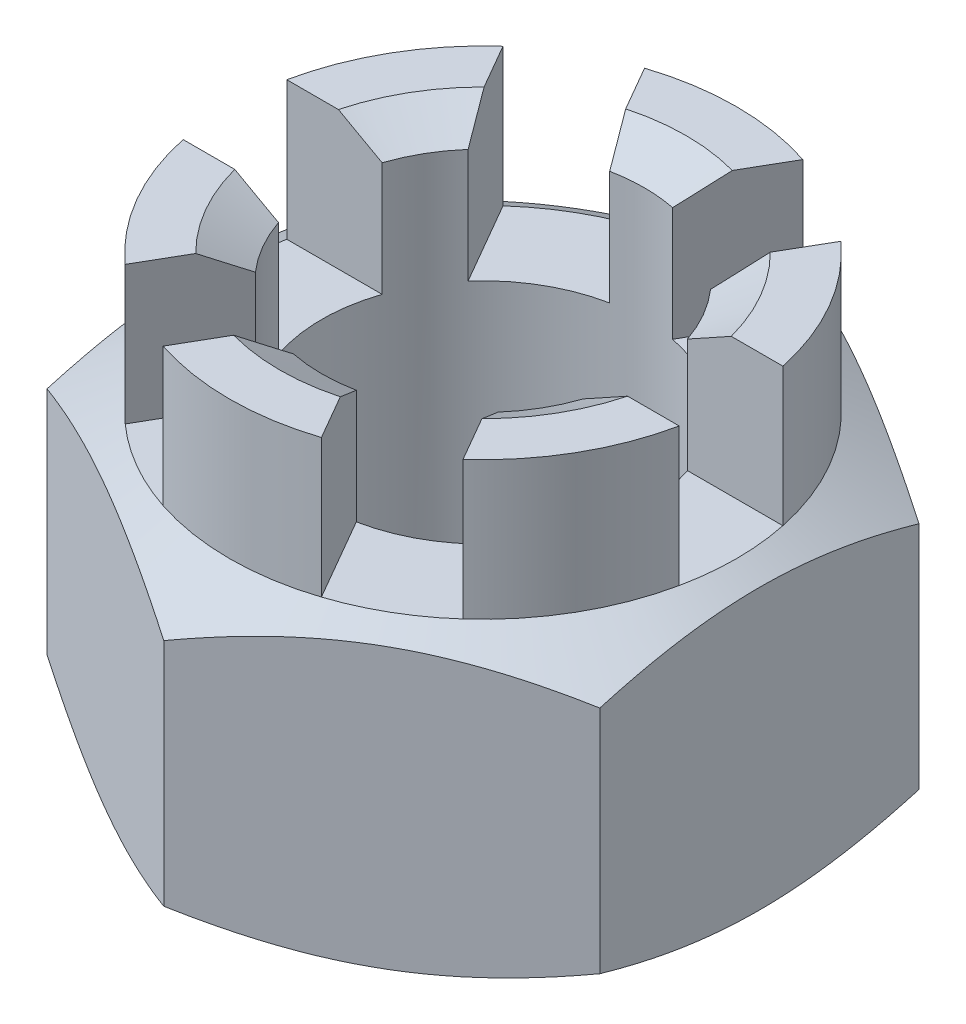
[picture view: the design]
ISO-10303-21;
HEADER;
FILE_DESCRIPTION(('STEP AP214'),'2;1');
FILE_NAME('part.step','',(''),(''),'','','');
FILE_SCHEMA(('AUTOMOTIVE_DESIGN { 1 0 10303 214 1 1 1 1 }'));
ENDSEC;
DATA;
#1=APPLICATION_CONTEXT('core data for automotive mechanical design processes');
#2=APPLICATION_PROTOCOL_DEFINITION('international standard','automotive_design',2000,#1);
#3=PRODUCT_CONTEXT('',#1,'mechanical');
#4=PRODUCT('Part','Part','',(#3));
#5=PRODUCT_RELATED_PRODUCT_CATEGORY('part','',(#4));
#6=PRODUCT_DEFINITION_FORMATION('','',#4);
#7=PRODUCT_DEFINITION_CONTEXT('part definition',#1,'design');
#8=PRODUCT_DEFINITION('design','',#6,#7);
#9=PRODUCT_DEFINITION_SHAPE('','',#8);
#10=(LENGTH_UNIT() NAMED_UNIT(*) SI_UNIT(.MILLI.,.METRE.));
#11=(NAMED_UNIT(*) PLANE_ANGLE_UNIT() SI_UNIT($,.RADIAN.));
#12=(NAMED_UNIT(*) SI_UNIT($,.STERADIAN.) SOLID_ANGLE_UNIT());
#13=UNCERTAINTY_MEASURE_WITH_UNIT(LENGTH_MEASURE(1.E-05),#10,'distance_accuracy_value','');
#14=(GEOMETRIC_REPRESENTATION_CONTEXT(3) GLOBAL_UNCERTAINTY_ASSIGNED_CONTEXT((#13)) GLOBAL_UNIT_ASSIGNED_CONTEXT((#10,
#11,#12)) REPRESENTATION_CONTEXT('',''));
#15=CARTESIAN_POINT('',(0.,0.,0.));
#16=DIRECTION('',(0.,0.,1.));
#17=DIRECTION('',(1.,0.,0.));
#18=AXIS2_PLACEMENT_3D('',#15,#16,#17);
#19=CARTESIAN_POINT('',(12.,19.,-6.92820323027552));
#20=DIRECTION('',(0.,-1.,0.));
#21=DIRECTION('',(0.,0.,-1.));
#22=AXIS2_PLACEMENT_3D('',#19,#20,#21);
#23=PLANE('',#22);
#24=CARTESIAN_POINT('',(0.,19.,0.));
#25=DIRECTION('',(0.,-1.,0.));
#26=DIRECTION('',(0.,0.,-1.));
#27=AXIS2_PLACEMENT_3D('',#24,#25,#26);
#28=CIRCLE('',#27,11.);
#29=CARTESIAN_POINT('',(3.43515670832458,19.,10.4498659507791));
#30=VERTEX_POINT('',#29);
#31=CARTESIAN_POINT('',(-3.4351567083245,19.,10.4498659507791));
#32=VERTEX_POINT('',#31);
#33=EDGE_CURVE('E822',#30,#32,#28,.T.);
#34=ORIENTED_EDGE('',*,*,#33,.F.);
#35=DIRECTION('',(-0.500000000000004,0.,-0.866025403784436));
#36=VECTOR('',#35,1.);
#37=CARTESIAN_POINT('',(-1.94855715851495,19.,1.12500000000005));
#38=LINE('',#37,#36);
#39=CARTESIAN_POINT('',(2.31483781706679,19.,8.50941671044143));
#40=VERTEX_POINT('',#39);
#41=EDGE_CURVE('E392',#30,#40,#38,.T.);
#42=ORIENTED_EDGE('',*,*,#41,.T.);
#43=CARTESIAN_POINT('',(0.,19.,0.));
#44=DIRECTION('',(0.,-1.,0.));
#45=DIRECTION('',(0.,0.,-1.));
#46=AXIS2_PLACEMENT_3D('',#43,#44,#45);
#47=CIRCLE('',#46,8.81865334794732);
#48=CARTESIAN_POINT('',(-2.31483781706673,19.,8.50941671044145));
#49=VERTEX_POINT('',#48);
#50=EDGE_CURVE('E629',#40,#49,#47,.T.);
#51=ORIENTED_EDGE('',*,*,#50,.T.);
#52=DIRECTION('',(-0.499999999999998,0.,0.86602540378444));
#53=VECTOR('',#52,1.);
#54=CARTESIAN_POINT('',(7.94855715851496,19.,-9.26730484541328));
#55=LINE('',#54,#53);
#56=EDGE_CURVE('E407',#49,#32,#55,.T.);
#57=ORIENTED_EDGE('',*,*,#56,.T.);
#58=EDGE_LOOP('',(#34,#42,#51,#57));
#59=FACE_BOUND('',#58,.T.);
#60=ADVANCED_FACE('F43',(#59),#23,.F.);
#61=CARTESIAN_POINT('',(0.,19.,0.));
#62=DIRECTION('',(0.,-1.,0.));
#63=DIRECTION('',(0.,0.,-1.));
#64=AXIS2_PLACEMENT_3D('',#61,#62,#63);
#65=CIRCLE('',#64,11.);
#66=CARTESIAN_POINT('',(-7.33227102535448,19.,8.19986595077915));
#67=VERTEX_POINT('',#66);
#68=CARTESIAN_POINT('',(-10.767427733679,19.,2.25));
#69=VERTEX_POINT('',#68);
#70=EDGE_CURVE('E308',#67,#69,#65,.T.);
#71=ORIENTED_EDGE('',*,*,#70,.F.);
#72=DIRECTION('',(0.499999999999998,0.,-0.86602540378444));
#73=VECTOR('',#72,1.);
#74=CARTESIAN_POINT('',(4.05144284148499,19.,-11.5173048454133));
#75=LINE('',#74,#73);
#76=CARTESIAN_POINT('',(-6.21195213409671,19.,6.25941671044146));
#77=VERTEX_POINT('',#76);
#78=EDGE_CURVE('E397',#67,#77,#75,.T.);
#79=ORIENTED_EDGE('',*,*,#78,.T.);
#80=CARTESIAN_POINT('',(-8.52678995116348,19.,2.25));
#81=VERTEX_POINT('',#80);
#82=EDGE_CURVE('E638',#77,#81,#47,.T.);
#83=ORIENTED_EDGE('',*,*,#82,.T.);
#84=DIRECTION('',(-1.,0.,0.));
#85=VECTOR('',#84,1.);
#86=CARTESIAN_POINT('',(12.,19.,2.25));
#87=LINE('',#86,#85);
#88=EDGE_CURVE('E427',#81,#69,#87,.T.);
#89=ORIENTED_EDGE('',*,*,#88,.T.);
#90=EDGE_LOOP('',(#71,#79,#83,#89));
#91=FACE_BOUND('',#90,.T.);
#92=ADVANCED_FACE('F576',(#91),#23,.F.);
#93=CARTESIAN_POINT('',(0.,19.,0.));
#94=DIRECTION('',(0.,-1.,0.));
#95=DIRECTION('',(0.,0.,-1.));
#96=AXIS2_PLACEMENT_3D('',#93,#94,#95);
#97=CIRCLE('',#96,11.);
#98=CARTESIAN_POINT('',(7.33227102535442,19.,-8.19986595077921));
#99=VERTEX_POINT('',#98);
#100=CARTESIAN_POINT('',(10.767427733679,19.,-2.25000000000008));
#101=VERTEX_POINT('',#100);
#102=EDGE_CURVE('E807',#99,#101,#97,.T.);
#103=ORIENTED_EDGE('',*,*,#102,.F.);
#104=DIRECTION('',(-0.499999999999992,0.,0.866025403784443));
#105=VECTOR('',#104,1.);
#106=CARTESIAN_POINT('',(7.94855715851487,19.,-9.26730484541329));
#107=LINE('',#106,#105);
#108=CARTESIAN_POINT('',(6.21195213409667,19.,-6.2594167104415));
#109=VERTEX_POINT('',#108);
#110=EDGE_CURVE('E354',#99,#109,#107,.T.);
#111=ORIENTED_EDGE('',*,*,#110,.T.);
#112=CARTESIAN_POINT('',(8.52678995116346,19.,-2.25000000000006));
#113=VERTEX_POINT('',#112);
#114=EDGE_CURVE('E630',#109,#113,#47,.T.);
#115=ORIENTED_EDGE('',*,*,#114,.T.);
#116=DIRECTION('',(1.,0.,0.));
#117=VECTOR('',#116,1.);
#118=CARTESIAN_POINT('',(12.,19.,-2.25000000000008));
#119=LINE('',#118,#117);
#120=EDGE_CURVE('E375',#113,#101,#119,.T.);
#121=ORIENTED_EDGE('',*,*,#120,.T.);
#122=EDGE_LOOP('',(#103,#111,#115,#121));
#123=FACE_BOUND('',#122,.T.);
#124=ADVANCED_FACE('F584',(#123),#23,.F.);
#125=CARTESIAN_POINT('',(0.,19.,0.));
#126=DIRECTION('',(0.,-1.,0.));
#127=DIRECTION('',(0.,0.,-1.));
#128=AXIS2_PLACEMENT_3D('',#125,#126,#127);
#129=CIRCLE('',#128,11.);
#130=CARTESIAN_POINT('',(-3.43515670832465,19.,-10.4498659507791));
#131=VERTEX_POINT('',#130);
#132=CARTESIAN_POINT('',(3.43515670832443,19.,-10.4498659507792));
#133=VERTEX_POINT('',#132);
#134=EDGE_CURVE('E284',#131,#133,#129,.T.);
#135=ORIENTED_EDGE('',*,*,#134,.F.);
#136=DIRECTION('',(0.50000000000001,0.,0.866025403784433));
#137=VECTOR('',#136,1.);
#138=CARTESIAN_POINT('',(1.94855715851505,19.,-1.12499999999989));
#139=LINE('',#138,#137);
#140=CARTESIAN_POINT('',(-2.31483781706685,19.,-8.50941671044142));
#141=VERTEX_POINT('',#140);
#142=EDGE_CURVE('E347',#131,#141,#139,.T.);
#143=ORIENTED_EDGE('',*,*,#142,.T.);
#144=CARTESIAN_POINT('',(2.31483781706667,19.,-8.50941671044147));
#145=VERTEX_POINT('',#144);
#146=EDGE_CURVE('E635',#141,#145,#47,.T.);
#147=ORIENTED_EDGE('',*,*,#146,.T.);
#148=DIRECTION('',(0.499999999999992,0.,-0.866025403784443));
#149=VECTOR('',#148,1.);
#150=CARTESIAN_POINT('',(4.05144284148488,19.,-11.5173048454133));
#151=LINE('',#150,#149);
#152=EDGE_CURVE('E358',#145,#133,#151,.T.);
#153=ORIENTED_EDGE('',*,*,#152,.T.);
#154=EDGE_LOOP('',(#135,#143,#147,#153));
#155=FACE_BOUND('',#154,.T.);
#156=ADVANCED_FACE('F592',(#155),#23,.F.);
#157=CARTESIAN_POINT('',(0.,19.,0.));
#158=DIRECTION('',(0.,-1.,0.));
#159=DIRECTION('',(0.,0.,-1.));
#160=AXIS2_PLACEMENT_3D('',#157,#158,#159);
#161=CIRCLE('',#160,11.);
#162=CARTESIAN_POINT('',(-10.767427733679,19.,-2.25));
#163=VERTEX_POINT('',#162);
#164=CARTESIAN_POINT('',(-7.33227102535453,19.,-8.1998659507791));
#165=VERTEX_POINT('',#164);
#166=EDGE_CURVE('E786',#163,#165,#161,.T.);
#167=ORIENTED_EDGE('',*,*,#166,.F.);
#168=DIRECTION('',(1.,0.,0.));
#169=VECTOR('',#168,1.);
#170=CARTESIAN_POINT('',(12.,19.,-2.25));
#171=LINE('',#170,#169);
#172=CARTESIAN_POINT('',(-8.52678995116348,19.,-2.25));
#173=VERTEX_POINT('',#172);
#174=EDGE_CURVE('E421',#163,#173,#171,.T.);
#175=ORIENTED_EDGE('',*,*,#174,.T.);
#176=CARTESIAN_POINT('',(-6.21195213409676,19.,-6.25941671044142));
#177=VERTEX_POINT('',#176);
#178=EDGE_CURVE('E640',#173,#177,#47,.T.);
#179=ORIENTED_EDGE('',*,*,#178,.T.);
#180=DIRECTION('',(-0.500000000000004,0.,-0.866025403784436));
#181=VECTOR('',#180,1.);
#182=CARTESIAN_POINT('',(-1.94855715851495,19.,1.12500000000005));
#183=LINE('',#182,#181);
#184=EDGE_CURVE('E376',#177,#165,#183,.T.);
#185=ORIENTED_EDGE('',*,*,#184,.T.);
#186=EDGE_LOOP('',(#167,#175,#179,#185));
#187=FACE_BOUND('',#186,.T.);
#188=ADVANCED_FACE('F590',(#187),#23,.F.);
#189=CARTESIAN_POINT('',(0.,19.,0.));
#190=DIRECTION('',(0.,-1.,0.));
#191=DIRECTION('',(0.,0.,-1.));
#192=AXIS2_PLACEMENT_3D('',#189,#190,#191);
#193=CIRCLE('',#192,11.);
#194=CARTESIAN_POINT('',(10.767427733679,19.,2.24999999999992));
#195=VERTEX_POINT('',#194);
#196=CARTESIAN_POINT('',(7.33227102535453,19.,8.1998659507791));
#197=VERTEX_POINT('',#196);
#198=EDGE_CURVE('E600',#195,#197,#193,.T.);
#199=ORIENTED_EDGE('',*,*,#198,.F.);
#200=DIRECTION('',(-1.,0.,0.));
#201=VECTOR('',#200,1.);
#202=CARTESIAN_POINT('',(12.0000000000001,19.,2.24999999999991));
#203=LINE('',#202,#201);
#204=CARTESIAN_POINT('',(8.52678995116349,19.,2.24999999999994));
#205=VERTEX_POINT('',#204);
#206=EDGE_CURVE('E366',#195,#205,#203,.T.);
#207=ORIENTED_EDGE('',*,*,#206,.T.);
#208=CARTESIAN_POINT('',(6.21195213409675,19.,6.25941671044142));
#209=VERTEX_POINT('',#208);
#210=EDGE_CURVE('E621',#205,#209,#47,.T.);
#211=ORIENTED_EDGE('',*,*,#210,.T.);
#212=DIRECTION('',(0.500000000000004,0.,0.866025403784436));
#213=VECTOR('',#212,1.);
#214=CARTESIAN_POINT('',(1.94855715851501,19.,-1.12499999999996));
#215=LINE('',#214,#213);
#216=EDGE_CURVE('E390',#209,#197,#215,.T.);
#217=ORIENTED_EDGE('',*,*,#216,.T.);
#218=EDGE_LOOP('',(#199,#207,#211,#217));
#219=FACE_BOUND('',#218,.T.);
#220=ADVANCED_FACE('F577',(#219),#23,.F.);
#221=CARTESIAN_POINT('',(12.,19.,-6.92820323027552));
#222=DIRECTION('',(-0.5,0.,0.866025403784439));
#223=DIRECTION('',(0.866025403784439,0.,0.5));
#224=AXIS2_PLACEMENT_3D('',#221,#222,#223);
#225=PLANE('',#224);
#226=CARTESIAN_POINT('',(12.0002,11.3507862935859,-6.92808776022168));
#227=CARTESIAN_POINT('',(11.7364142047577,11.4387000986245,-7.0803845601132));
#228=CARTESIAN_POINT('',(11.4716448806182,11.5226237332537,-7.23324920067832));
#229=CARTESIAN_POINT('',(10.9399829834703,11.6813835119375,-7.54020434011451));
#230=CARTESIAN_POINT('',(10.6730897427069,11.7562166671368,-7.69429522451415));
#231=CARTESIAN_POINT('',(9.86810959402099,11.9656321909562,-8.15905073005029));
#232=CARTESIAN_POINT('',(9.32684492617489,12.0847464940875,-8.47155003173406));
#233=CARTESIAN_POINT('',(8.51686717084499,12.2244186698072,-8.93919090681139));
#234=CARTESIAN_POINT('',(8.25057389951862,12.2642059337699,-9.09293539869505));
#235=CARTESIAN_POINT('',(7.71675440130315,12.3309263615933,-9.40113622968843));
#236=CARTESIAN_POINT('',(7.44922815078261,12.3578592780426,-9.55559258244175));
#237=CARTESIAN_POINT('',(6.91372963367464,12.3981811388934,-9.86476279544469));
#238=CARTESIAN_POINT('',(6.64575827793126,12.411586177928,-10.0194761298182));
#239=CARTESIAN_POINT('',(6.10956726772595,12.4245666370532,-10.3290461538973));
#240=CARTESIAN_POINT('',(5.84134762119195,12.4241424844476,-10.4839028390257));
#241=CARTESIAN_POINT('',(5.33991062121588,12.4104297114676,-10.7734076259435));
#242=CARTESIAN_POINT('',(5.10665750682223,12.3988137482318,-10.908076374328));
#243=CARTESIAN_POINT('',(4.64068775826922,12.365341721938,-11.1771041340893));
#244=CARTESIAN_POINT('',(4.40797116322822,12.3434849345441,-11.3114631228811));
#245=CARTESIAN_POINT('',(3.94320092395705,12.2899123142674,-11.5797983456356));
#246=CARTESIAN_POINT('',(3.71114798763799,12.2581883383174,-11.7137741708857));
#247=CARTESIAN_POINT('',(3.24813003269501,12.1854379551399,-11.9810977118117));
#248=CARTESIAN_POINT('',(3.01716508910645,12.1444109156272,-12.1144453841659));
#249=CARTESIAN_POINT('',(2.31605804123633,12.0063380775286,-12.5192297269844));
#250=CARTESIAN_POINT('',(1.84794625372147,11.895524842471,-12.789494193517));
#251=CARTESIAN_POINT('',(0.918702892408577,11.6440239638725,-13.3259930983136));
#252=CARTESIAN_POINT('',(0.457559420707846,11.503395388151,-13.5922344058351));
#253=CARTESIAN_POINT('',(-0.000199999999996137,11.3507862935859,-13.8565219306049));
#254=B_SPLINE_CURVE_WITH_KNOTS('',3,(#226,#227,#228,#229,#230,#231,#232,#233,#234,#235,#236,
#237,#238,#239,#240,#241,#242,#243,#244,#245,#246,#247,#248,#249,#250,#251,#252,#253),
.UNSPECIFIED.,.F.,.F.,(4,2,2,2,2,2,2,2,2,2,2,2,2,4),(0.,0.95100487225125,1.90232158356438,
3.8090046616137,4.73894551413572,5.66890426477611,6.59775529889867,7.52657763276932,
8.3351464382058,9.14377244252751,9.95306755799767,10.7624176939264,12.4167102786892,
14.0677556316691),.UNSPECIFIED.);
#255=CARTESIAN_POINT('',(12.,11.3508529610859,-6.92820323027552));
#256=VERTEX_POINT('',#255);
#257=CARTESIAN_POINT('',(0.,11.3508529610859,-13.856406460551));
#258=VERTEX_POINT('',#257);
#259=EDGE_CURVE('E322',#256,#258,#254,.T.);
#260=ORIENTED_EDGE('',*,*,#259,.F.);
#261=DIRECTION('',(0.,-1.,0.));
#262=VECTOR('',#261,1.);
#263=CARTESIAN_POINT('',(12.,19.,-6.92820323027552));
#264=LINE('',#263,#262);
#265=CARTESIAN_POINT('',(12.,1.36047190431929,-6.92820323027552));
#266=VERTEX_POINT('',#265);
#267=EDGE_CURVE('E741',#256,#266,#264,.T.);
#268=ORIENTED_EDGE('',*,*,#267,.T.);
#269=CARTESIAN_POINT('',(-0.000199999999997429,1.36053857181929,-13.8565219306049));
#270=CARTESIAN_POINT('',(0.263585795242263,1.27262476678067,-13.7042251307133));
#271=CARTESIAN_POINT('',(0.528355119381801,1.18870113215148,-13.5513604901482));
#272=CARTESIAN_POINT('',(1.06001701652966,1.02994135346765,-13.244405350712));
#273=CARTESIAN_POINT('',(1.32691025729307,0.955108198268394,-13.0903144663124));
#274=CARTESIAN_POINT('',(2.13189040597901,0.745692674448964,-12.6255589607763));
#275=CARTESIAN_POINT('',(2.6731550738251,0.626578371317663,-12.3130596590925));
#276=CARTESIAN_POINT('',(3.483132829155,0.486906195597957,-11.8454187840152));
#277=CARTESIAN_POINT('',(3.74942610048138,0.447118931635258,-11.6916742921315));
#278=CARTESIAN_POINT('',(4.28324559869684,0.380398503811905,-11.3834734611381));
#279=CARTESIAN_POINT('',(4.55077184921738,0.35346558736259,-11.2290171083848));
#280=CARTESIAN_POINT('',(5.08627036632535,0.313143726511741,-10.9198468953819));
#281=CARTESIAN_POINT('',(5.35424172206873,0.299738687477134,-10.7651335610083));
#282=CARTESIAN_POINT('',(5.89043273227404,0.286758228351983,-10.4555635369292));
#283=CARTESIAN_POINT('',(6.15865237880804,0.287182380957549,-10.3007068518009));
#284=CARTESIAN_POINT('',(6.66008937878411,0.300895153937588,-10.0112020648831));
#285=CARTESIAN_POINT('',(6.89334249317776,0.312511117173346,-9.87653331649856));
#286=CARTESIAN_POINT('',(7.35931224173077,0.345983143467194,-9.60750555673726));
#287=CARTESIAN_POINT('',(7.59202883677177,0.367839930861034,-9.47314656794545));
#288=CARTESIAN_POINT('',(8.05679907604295,0.421412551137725,-9.20481134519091));
#289=CARTESIAN_POINT('',(8.28885201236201,0.453136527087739,-9.07083551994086));
#290=CARTESIAN_POINT('',(8.75186996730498,0.525886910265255,-8.8035119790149));
#291=CARTESIAN_POINT('',(8.98283491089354,0.566913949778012,-8.67016430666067));
#292=CARTESIAN_POINT('',(9.68394195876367,0.704986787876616,-8.26537996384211));
#293=CARTESIAN_POINT('',(10.1520537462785,0.815800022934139,-7.99511549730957));
#294=CARTESIAN_POINT('',(11.0812971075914,1.0673009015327,-7.4586165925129));
#295=CARTESIAN_POINT('',(11.5424405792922,1.20792947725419,-7.19237528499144));
#296=CARTESIAN_POINT('',(12.0002,1.36053857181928,-6.92808776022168));
#297=B_SPLINE_CURVE_WITH_KNOTS('',3,(#269,#270,#271,#272,#273,#274,#275,#276,#277,#278,#279,
#280,#281,#282,#283,#284,#285,#286,#287,#288,#289,#290,#291,#292,#293,#294,#295,#296),
.UNSPECIFIED.,.F.,.F.,(4,2,2,2,2,2,2,2,2,2,2,2,2,4),(0.,0.951004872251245,1.90232158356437,
3.80900466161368,4.7389455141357,5.66890426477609,6.59775529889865,7.5265776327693,
8.33514643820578,9.14377244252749,9.95306755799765,10.7624176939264,12.4167102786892,
14.0677556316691),.UNSPECIFIED.);
#298=CARTESIAN_POINT('',(0.,1.36047190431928,-13.856406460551));
#299=VERTEX_POINT('',#298);
#300=EDGE_CURVE('E493',#299,#266,#297,.T.);
#301=ORIENTED_EDGE('',*,*,#300,.F.);
#302=DIRECTION('',(0.,-1.,0.));
#303=VECTOR('',#302,1.);
#304=CARTESIAN_POINT('',(0.,19.,-13.856406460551));
#305=LINE('',#304,#303);
#306=EDGE_CURVE('E723',#258,#299,#305,.T.);
#307=ORIENTED_EDGE('',*,*,#306,.F.);
#308=EDGE_LOOP('',(#260,#268,#301,#307));
#309=FACE_BOUND('',#308,.T.);
#310=ADVANCED_FACE('F503',(#309),#225,.F.);
#311=CARTESIAN_POINT('',(0.,19.,-13.856406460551));
#312=DIRECTION('',(0.5,0.,0.866025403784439));
#313=DIRECTION('',(0.866025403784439,0.,-0.5));
#314=AXIS2_PLACEMENT_3D('',#311,#312,#313);
#315=PLANE('',#314);
#316=CARTESIAN_POINT('',(0.000200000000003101,11.3507862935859,-13.8565219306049));
#317=CARTESIAN_POINT('',(-0.26358579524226,11.4387000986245,-13.7042251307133));
#318=CARTESIAN_POINT('',(-0.528355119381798,11.5226237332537,-13.5513604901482));
#319=CARTESIAN_POINT('',(-1.06001701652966,11.6813835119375,-13.244405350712));
#320=CARTESIAN_POINT('',(-1.32691025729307,11.7562166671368,-13.0903144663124));
#321=CARTESIAN_POINT('',(-2.13189040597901,11.9656321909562,-12.6255589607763));
#322=CARTESIAN_POINT('',(-2.67315507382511,12.0847464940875,-12.3130596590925));
#323=CARTESIAN_POINT('',(-3.483132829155,12.2244186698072,-11.8454187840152));
#324=CARTESIAN_POINT('',(-3.74942610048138,12.2642059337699,-11.6916742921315));
#325=CARTESIAN_POINT('',(-4.28324559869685,12.3309263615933,-11.3834734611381));
#326=CARTESIAN_POINT('',(-4.55077184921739,12.3578592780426,-11.2290171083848));
#327=CARTESIAN_POINT('',(-5.08627036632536,12.3981811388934,-10.9198468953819));
#328=CARTESIAN_POINT('',(-5.35424172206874,12.411586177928,-10.7651335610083));
#329=CARTESIAN_POINT('',(-5.89043273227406,12.4245666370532,-10.4555635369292));
#330=CARTESIAN_POINT('',(-6.15865237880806,12.4241424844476,-10.3007068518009));
#331=CARTESIAN_POINT('',(-6.66008937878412,12.4104297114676,-10.011202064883));
#332=CARTESIAN_POINT('',(-6.89334249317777,12.3988137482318,-9.87653331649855));
#333=CARTESIAN_POINT('',(-7.35931224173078,12.365341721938,-9.60750555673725));
#334=CARTESIAN_POINT('',(-7.59202883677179,12.3434849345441,-9.47314656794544));
#335=CARTESIAN_POINT('',(-8.05679907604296,12.2899123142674,-9.2048113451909));
#336=CARTESIAN_POINT('',(-8.28885201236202,12.2581883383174,-9.07083551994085));
#337=CARTESIAN_POINT('',(-8.75186996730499,12.1854379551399,-8.80351197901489));
#338=CARTESIAN_POINT('',(-8.98283491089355,12.1444109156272,-8.67016430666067));
#339=CARTESIAN_POINT('',(-9.68394195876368,12.0063380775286,-8.26537996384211));
#340=CARTESIAN_POINT('',(-10.1520537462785,11.895524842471,-7.99511549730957));
#341=CARTESIAN_POINT('',(-11.0812971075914,11.6440239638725,-7.4586165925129));
#342=CARTESIAN_POINT('',(-11.5424405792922,11.503395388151,-7.19237528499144));
#343=CARTESIAN_POINT('',(-12.0002,11.3507862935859,-6.92808776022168));
#344=B_SPLINE_CURVE_WITH_KNOTS('',3,(#316,#317,#318,#319,#320,#321,#322,#323,#324,#325,#326,
#327,#328,#329,#330,#331,#332,#333,#334,#335,#336,#337,#338,#339,#340,#341,#342,#343),
.UNSPECIFIED.,.F.,.F.,(4,2,2,2,2,2,2,2,2,2,2,2,2,4),(0.,0.951004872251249,1.90232158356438,
3.8090046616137,4.73894551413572,5.66890426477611,6.59775529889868,7.52657763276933,
8.33514643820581,9.14377244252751,9.95306755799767,10.7624176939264,12.4167102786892,
14.0677556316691),.UNSPECIFIED.);
#345=CARTESIAN_POINT('',(-12.,11.3508529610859,-6.92820323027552));
#346=VERTEX_POINT('',#345);
#347=EDGE_CURVE('E508',#258,#346,#344,.T.);
#348=ORIENTED_EDGE('',*,*,#347,.F.);
#349=ORIENTED_EDGE('',*,*,#306,.T.);
#350=CARTESIAN_POINT('',(-12.0002,1.36053857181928,-6.92808776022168));
#351=CARTESIAN_POINT('',(-11.7364142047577,1.27262476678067,-7.0803845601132));
#352=CARTESIAN_POINT('',(-11.4716448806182,1.18870113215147,-7.23324920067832));
#353=CARTESIAN_POINT('',(-10.9399829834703,1.02994135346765,-7.5402043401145));
#354=CARTESIAN_POINT('',(-10.6730897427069,0.955108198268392,-7.69429522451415));
#355=CARTESIAN_POINT('',(-9.86810959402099,0.745692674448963,-8.15905073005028));
#356=CARTESIAN_POINT('',(-9.3268449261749,0.626578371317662,-8.47155003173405));
#357=CARTESIAN_POINT('',(-8.51686717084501,0.486906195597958,-8.93919090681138));
#358=CARTESIAN_POINT('',(-8.25057389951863,0.447118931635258,-9.09293539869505));
#359=CARTESIAN_POINT('',(-7.71675440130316,0.380398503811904,-9.40113622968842));
#360=CARTESIAN_POINT('',(-7.44922815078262,0.353465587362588,-9.55559258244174));
#361=CARTESIAN_POINT('',(-6.91372963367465,0.313143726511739,-9.86476279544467));
#362=CARTESIAN_POINT('',(-6.64575827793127,0.299738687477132,-10.0194761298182));
#363=CARTESIAN_POINT('',(-6.10956726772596,0.286758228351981,-10.3290461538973));
#364=CARTESIAN_POINT('',(-5.84134762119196,0.287182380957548,-10.4839028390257));
#365=CARTESIAN_POINT('',(-5.3399106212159,0.300895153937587,-10.7734076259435));
#366=CARTESIAN_POINT('',(-5.10665750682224,0.312511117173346,-10.908076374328));
#367=CARTESIAN_POINT('',(-4.64068775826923,0.345983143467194,-11.1771041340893));
#368=CARTESIAN_POINT('',(-4.40797116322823,0.367839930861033,-11.3114631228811));
#369=CARTESIAN_POINT('',(-3.94320092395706,0.421412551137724,-11.5797983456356));
#370=CARTESIAN_POINT('',(-3.711147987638,0.453136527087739,-11.7137741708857));
#371=CARTESIAN_POINT('',(-3.24813003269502,0.525886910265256,-11.9810977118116));
#372=CARTESIAN_POINT('',(-3.01716508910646,0.566913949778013,-12.1144453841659));
#373=CARTESIAN_POINT('',(-2.31605804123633,0.704986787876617,-12.5192297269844));
#374=CARTESIAN_POINT('',(-1.84794625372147,0.815800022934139,-12.789494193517));
#375=CARTESIAN_POINT('',(-0.918702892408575,1.0673009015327,-13.3259930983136));
#376=CARTESIAN_POINT('',(-0.457559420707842,1.2079294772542,-13.5922344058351));
#377=CARTESIAN_POINT('',(0.000200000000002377,1.36053857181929,-13.8565219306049));
#378=B_SPLINE_CURVE_WITH_KNOTS('',3,(#350,#351,#352,#353,#354,#355,#356,#357,#358,#359,#360,
#361,#362,#363,#364,#365,#366,#367,#368,#369,#370,#371,#372,#373,#374,#375,#376,#377),
.UNSPECIFIED.,.F.,.F.,(4,2,2,2,2,2,2,2,2,2,2,2,2,4),(0.,0.951004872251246,1.90232158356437,
3.80900466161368,4.7389455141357,5.66890426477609,6.59775529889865,7.5265776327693,
8.33514643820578,9.14377244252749,9.95306755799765,10.7624176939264,12.4167102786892,
14.0677556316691),.UNSPECIFIED.);
#379=CARTESIAN_POINT('',(-12.,1.36047190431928,-6.9282032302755));
#380=VERTEX_POINT('',#379);
#381=EDGE_CURVE('E484',#380,#299,#378,.T.);
#382=ORIENTED_EDGE('',*,*,#381,.F.);
#383=DIRECTION('',(0.,-1.,0.));
#384=VECTOR('',#383,1.);
#385=CARTESIAN_POINT('',(-12.,19.,-6.92820323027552));
#386=LINE('',#385,#384);
#387=EDGE_CURVE('E727',#346,#380,#386,.T.);
#388=ORIENTED_EDGE('',*,*,#387,.F.);
#389=EDGE_LOOP('',(#348,#349,#382,#388));
#390=FACE_BOUND('',#389,.T.);
#391=ADVANCED_FACE('F499',(#390),#315,.F.);
#392=CARTESIAN_POINT('',(-12.,19.,-6.92820323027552));
#393=DIRECTION('',(1.,0.,0.));
#394=DIRECTION('',(0.,0.,-1.));
#395=AXIS2_PLACEMENT_3D('',#392,#393,#394);
#396=PLANE('',#395);
#397=CARTESIAN_POINT('',(-12.,6.61631705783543,-18.5068963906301));
#398=CARTESIAN_POINT('',(-12.,6.74309926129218,-18.2451758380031));
#399=CARTESIAN_POINT('',(-12.,6.86924113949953,-17.9831452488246));
#400=CARTESIAN_POINT('',(-12.,7.12009895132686,-17.4583992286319));
#401=CARTESIAN_POINT('',(-12.,7.24481487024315,-17.1956837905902));
#402=CARTESIAN_POINT('',(-12.,7.61663935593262,-16.406341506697));
#403=CARTESIAN_POINT('',(-12.,7.8613861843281,-15.8785978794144));
#404=CARTESIAN_POINT('',(-12.,8.3444197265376,-14.8166225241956));
#405=CARTESIAN_POINT('',(-12.,8.58266313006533,-14.2823710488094));
#406=CARTESIAN_POINT('',(-12.,9.04925865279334,-13.2095807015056));
#407=CARTESIAN_POINT('',(-12.,9.27761124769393,-12.6710420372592));
#408=CARTESIAN_POINT('',(-12.,9.72860337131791,-11.5722513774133));
#409=CARTESIAN_POINT('',(-12.,9.95085446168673,-11.0118391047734));
#410=CARTESIAN_POINT('',(-12.,10.3782855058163,-9.88441748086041));
#411=CARTESIAN_POINT('',(-12.,10.58346353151,-9.31740739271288));
#412=CARTESIAN_POINT('',(-12.,10.9712865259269,-8.17699991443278));
#413=CARTESIAN_POINT('',(-12.,11.1539779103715,-7.60361843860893));
#414=CARTESIAN_POINT('',(-12.,11.4909093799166,-6.44857974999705));
#415=CARTESIAN_POINT('',(-12.,11.6451585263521,-5.86692523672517));
#416=CARTESIAN_POINT('',(-12.,11.8491769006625,-4.98964275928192));
#417=CARTESIAN_POINT('',(-12.,11.9125002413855,-4.69714706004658));
#418=CARTESIAN_POINT('',(-12.,12.0292491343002,-4.1101766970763));
#419=CARTESIAN_POINT('',(-12.,12.0826748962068,-3.81570207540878));
#420=CARTESIAN_POINT('',(-12.,12.178679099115,-3.22498620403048));
#421=CARTESIAN_POINT('',(-12.,12.2212577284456,-2.92874498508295));
#422=CARTESIAN_POINT('',(-12.,12.2947149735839,-2.33481663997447));
#423=CARTESIAN_POINT('',(-12.,12.3255940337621,-2.03712956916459));
#424=CARTESIAN_POINT('',(-12.,12.3746572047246,-1.4445675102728));
#425=CARTESIAN_POINT('',(-12.,12.39299979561,-1.14970572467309));
#426=CARTESIAN_POINT('',(-12.,12.4172064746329,-0.559471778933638));
#427=CARTESIAN_POINT('',(-12.,12.4230707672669,-0.264099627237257));
#428=CARTESIAN_POINT('',(-12.,12.4221816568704,0.326634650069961));
#429=CARTESIAN_POINT('',(-12.,12.4154279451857,0.6219967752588));
#430=CARTESIAN_POINT('',(-12.,12.3894654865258,1.21217665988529));
#431=CARTESIAN_POINT('',(-12.,12.3702561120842,1.50699439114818));
#432=CARTESIAN_POINT('',(-12.,12.3092804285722,2.21836923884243));
#433=CARTESIAN_POINT('',(-12.,12.2614476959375,2.63441698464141));
#434=CARTESIAN_POINT('',(-12.,12.1436078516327,3.46333964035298));
#435=CARTESIAN_POINT('',(-12.,12.0735976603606,3.87621410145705));
#436=CARTESIAN_POINT('',(-12.,11.8340215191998,5.10962525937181));
#437=CARTESIAN_POINT('',(-12.,11.6349533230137,5.92450248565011));
#438=CARTESIAN_POINT('',(-12.,11.29067134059,7.14347200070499));
#439=CARTESIAN_POINT('',(-12.,11.1666089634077,7.5538994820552));
#440=CARTESIAN_POINT('',(-12.,10.9058568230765,8.37076322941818));
#441=CARTESIAN_POINT('',(-12.,10.769166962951,8.7771994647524));
#442=CARTESIAN_POINT('',(-12.,10.485330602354,9.58622174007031));
#443=CARTESIAN_POINT('',(-12.,10.3381875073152,9.98880898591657));
#444=CARTESIAN_POINT('',(-12.,10.0351583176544,10.7906604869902));
#445=CARTESIAN_POINT('',(-12.,9.87927243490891,11.1899248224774));
#446=CARTESIAN_POINT('',(-12.,9.57772538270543,11.9418144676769));
#447=CARTESIAN_POINT('',(-12.,9.43282221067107,12.2947449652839));
#448=CARTESIAN_POINT('',(-12.,9.13806186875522,12.9985340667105));
#449=CARTESIAN_POINT('',(-12.,8.98820461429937,13.3493926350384));
#450=CARTESIAN_POINT('',(-12.,8.53226371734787,14.3992708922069));
#451=CARTESIAN_POINT('',(-12.,8.21983424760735,15.0955357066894));
#452=CARTESIAN_POINT('',(-12.,7.58228245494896,16.4825193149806));
#453=CARTESIAN_POINT('',(-12.,7.25715523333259,17.1732358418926));
#454=CARTESIAN_POINT('',(-12.,6.59733543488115,18.5500383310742));
#455=CARTESIAN_POINT('',(-12.,6.26264326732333,19.2361244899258));
#456=CARTESIAN_POINT('',(-12.,5.58530906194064,20.6057159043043));
#457=CARTESIAN_POINT('',(-12.,5.24265518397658,21.2892152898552));
#458=CARTESIAN_POINT('',(-12.,4.55149468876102,22.653251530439));
#459=CARTESIAN_POINT('',(-12.,4.20298801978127,23.333788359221));
#460=CARTESIAN_POINT('',(-12.,3.50138060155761,24.6922957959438));
#461=CARTESIAN_POINT('',(-12.,3.14828088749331,25.3702669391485));
#462=CARTESIAN_POINT('',(-12.,2.43829526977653,26.7242189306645));
#463=CARTESIAN_POINT('',(-12.,2.08140937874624,27.4001997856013));
#464=CARTESIAN_POINT('',(-12.,1.08478172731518,29.2775044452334));
#465=CARTESIAN_POINT('',(-12.,0.44168723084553,30.4770479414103));
#466=CARTESIAN_POINT('',(-12.,-0.85158493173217,32.8724004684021));
#467=CARTESIAN_POINT('',(-12.,-1.50176304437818,34.0682092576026));
#468=CARTESIAN_POINT('',(-12.,-2.80525676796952,36.4530745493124));
#469=CARTESIAN_POINT('',(-12.,-3.45855534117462,37.6421403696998));
#470=CARTESIAN_POINT('',(-12.,-4.44147274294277,39.4240388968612));
#471=CARTESIAN_POINT('',(-12.,-4.76959400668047,40.0176986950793));
#472=CARTESIAN_POINT('',(-12.,-5.42672288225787,41.2045267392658));
#473=CARTESIAN_POINT('',(-12.,-5.75573049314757,41.7976949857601));
#474=CARTESIAN_POINT('',(-12.,-6.08512571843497,42.3906479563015));
#475=B_SPLINE_CURVE_WITH_KNOTS('',3,(#397,#398,#399,#400,#401,#402,#403,#404,#405,#406,#407,
#408,#409,#410,#411,#412,#413,#414,#415,#416,#417,#418,#419,#420,#421,#422,#423,#424,#425,#426,
#427,#428,#429,#430,#431,#432,#433,#434,#435,#436,#437,#438,#439,#440,#441,#442,#443,#444,#445,
#446,#447,#448,#449,#450,#451,#452,#453,#454,#455,#456,#457,#458,#459,#460,#461,#462,#463,#464,
#465,#466,#467,#468,#469,#470,#471,#472,#473,#474),.UNSPECIFIED.,.F.,.F.,(4,2,2,2,2,2,2,2,2,2,2,
2,2,2,2,2,2,2,2,2,2,2,2,2,2,2,2,2,2,2,2,2,2,2,2,2,2,2,4),(0.,0.872433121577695,1.74487523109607,
3.49002354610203,5.24484180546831,6.99957557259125,8.80798621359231,10.6166008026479,
12.4214172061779,14.2256576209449,15.1233324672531,16.0209882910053,16.9186285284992,
17.8162346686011,18.702272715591,19.5882962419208,20.4743414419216,21.3604312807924,
22.6160857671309,23.871914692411,26.3849145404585,27.6711149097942,28.9573251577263,
30.2431182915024,31.5288802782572,32.6733957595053,33.8179307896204,36.1071867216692,
38.3973347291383,40.6873848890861,42.9810915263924,45.2748184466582,47.568037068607,
49.8612480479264,53.9443807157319,58.0277722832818,62.097907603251,64.1328172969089,
66.1677248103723),.UNSPECIFIED.);
#476=CARTESIAN_POINT('',(-12.,11.3508529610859,6.9282032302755));
#477=VERTEX_POINT('',#476);
#478=EDGE_CURVE('E517',#346,#477,#475,.T.);
#479=ORIENTED_EDGE('',*,*,#478,.F.);
#480=ORIENTED_EDGE('',*,*,#387,.T.);
#481=CARTESIAN_POINT('',(-12.,6.0116615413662,-18.3346065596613));
#482=CARTESIAN_POINT('',(-12.,5.88448426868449,-18.071337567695));
#483=CARTESIAN_POINT('',(-12.,5.75796841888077,-17.8077492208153));
#484=CARTESIAN_POINT('',(-12.,5.50641147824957,-17.2798663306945));
#485=CARTESIAN_POINT('',(-12.,5.38137040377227,-17.0155717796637));
#486=CARTESIAN_POINT('',(-12.,5.00865069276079,-16.221449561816));
#487=CARTESIAN_POINT('',(-12.,4.76341736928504,-15.6904696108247));
#488=CARTESIAN_POINT('',(-12.,4.27965104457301,-14.6217679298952));
#489=CARTESIAN_POINT('',(-12.,4.04116479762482,-14.0840249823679));
#490=CARTESIAN_POINT('',(-12.,3.57448957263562,-13.004105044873));
#491=CARTESIAN_POINT('',(-12.,3.34630005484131,-12.461928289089));
#492=CARTESIAN_POINT('',(-12.,2.90033193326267,-11.3657346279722));
#493=CARTESIAN_POINT('',(-12.,2.68271002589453,-10.8116536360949));
#494=CARTESIAN_POINT('',(-12.,2.26460970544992,-9.69693816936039));
#495=CARTESIAN_POINT('',(-12.,2.06413320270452,-9.13630297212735));
#496=CARTESIAN_POINT('',(-12.,1.68574234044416,-8.00877063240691));
#497=CARTESIAN_POINT('',(-12.,1.50777966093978,-7.44188984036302));
#498=CARTESIAN_POINT('',(-12.,1.1802133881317,-6.30001630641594));
#499=CARTESIAN_POINT('',(-12.,1.03060079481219,-5.72502620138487));
#500=CARTESIAN_POINT('',(-12.,0.832938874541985,-4.85634692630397));
#501=CARTESIAN_POINT('',(-12.,0.771499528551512,-4.56568429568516));
#502=CARTESIAN_POINT('',(-12.,0.658515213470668,-3.98243264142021));
#503=CARTESIAN_POINT('',(-12.,0.606970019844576,-3.68984366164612));
#504=CARTESIAN_POINT('',(-12.,0.514689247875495,-3.10293318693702));
#505=CARTESIAN_POINT('',(-12.,0.473954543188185,-2.80861155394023));
#506=CARTESIAN_POINT('',(-12.,0.404116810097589,-2.21859253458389));
#507=CARTESIAN_POINT('',(-12.,0.375013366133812,-1.92289519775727));
#508=CARTESIAN_POINT('',(-12.,0.329216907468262,-1.33239351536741));
#509=CARTESIAN_POINT('',(-12.,0.312447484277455,-1.03759513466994));
#510=CARTESIAN_POINT('',(-12.,0.291407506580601,-0.44755424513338));
#511=CARTESIAN_POINT('',(-12.,0.28713676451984,-0.152311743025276));
#512=CARTESIAN_POINT('',(-12.,0.291195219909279,0.438005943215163));
#513=CARTESIAN_POINT('',(-12.,0.299520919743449,0.733081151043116));
#514=CARTESIAN_POINT('',(-12.,0.328566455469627,1.32262470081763));
#515=CARTESIAN_POINT('',(-12.,0.349286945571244,1.6170930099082));
#516=CARTESIAN_POINT('',(-12.,0.414195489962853,2.33186551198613));
#517=CARTESIAN_POINT('',(-12.,0.464653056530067,2.75161135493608));
#518=CARTESIAN_POINT('',(-12.,0.587933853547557,3.58778782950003));
#519=CARTESIAN_POINT('',(-12.,0.66076043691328,4.00421795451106));
#520=CARTESIAN_POINT('',(-12.,0.909137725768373,5.24927450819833));
#521=CARTESIAN_POINT('',(-12.,1.11441917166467,6.07203707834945));
#522=CARTESIAN_POINT('',(-12.,1.46805079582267,7.30267412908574));
#523=CARTESIAN_POINT('',(-12.,1.59526318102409,7.71698679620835));
#524=CARTESIAN_POINT('',(-12.,1.86228669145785,8.54160931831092));
#525=CARTESIAN_POINT('',(-12.,2.00209894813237,8.9519188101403));
#526=CARTESIAN_POINT('',(-12.,2.29134955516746,9.76648835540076));
#527=CARTESIAN_POINT('',(-12.,2.44072902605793,10.1707694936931));
#528=CARTESIAN_POINT('',(-12.,2.67122411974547,10.7746497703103));
#529=CARTESIAN_POINT('',(-12.,2.74911366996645,10.9754873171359));
#530=CARTESIAN_POINT('',(-12.,2.90686066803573,11.3763838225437));
#531=CARTESIAN_POINT('',(-12.,2.9867180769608,11.5764427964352));
#532=CARTESIAN_POINT('',(-12.,3.06747047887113,11.7761396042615));
#533=B_SPLINE_CURVE_WITH_KNOTS('',3,(#481,#482,#483,#484,#485,#486,#487,#488,#489,#490,#491,
#492,#493,#494,#495,#496,#497,#498,#499,#500,#501,#502,#503,#504,#505,#506,#507,#508,#509,#510,
#511,#512,#513,#514,#515,#516,#517,#518,#519,#520,#521,#522,#523,#524,#525,#526,#527,#528,#529,
#530,#531,#532),.UNSPECIFIED.,.F.,.F.,(4,2,2,2,2,2,2,2,2,2,2,2,2,2,2,2,2,2,2,2,2,2,2,2,2,4),(0.,
0.877130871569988,1.75427145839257,3.50884023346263,5.2735197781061,7.03810671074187,
8.82374707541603,10.609586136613,12.3915248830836,14.172896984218,15.0640109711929,
15.9551047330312,16.846270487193,17.737404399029,18.6229701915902,19.5085226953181,
20.393829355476,21.2791827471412,22.5467648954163,23.8145371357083,26.3549754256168,
27.6550829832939,28.9553074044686,30.2481822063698,30.8944104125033,31.5406258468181),.UNSPECIFIED.);
#534=CARTESIAN_POINT('',(-12.,1.36047190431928,6.92820323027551));
#535=VERTEX_POINT('',#534);
#536=EDGE_CURVE('E479',#535,#380,#533,.F.);
#537=ORIENTED_EDGE('',*,*,#536,.F.);
#538=DIRECTION('',(0.,-1.,0.));
#539=VECTOR('',#538,1.);
#540=CARTESIAN_POINT('',(-12.,19.,6.9282032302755));
#541=LINE('',#540,#539);
#542=EDGE_CURVE('E734',#477,#535,#541,.T.);
#543=ORIENTED_EDGE('',*,*,#542,.F.);
#544=EDGE_LOOP('',(#479,#480,#537,#543));
#545=FACE_BOUND('',#544,.T.);
#546=ADVANCED_FACE('F502',(#545),#396,.F.);
#547=CARTESIAN_POINT('',(-12.,19.,6.9282032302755));
#548=DIRECTION('',(0.5,0.,-0.866025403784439));
#549=DIRECTION('',(-0.866025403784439,0.,-0.5));
#550=AXIS2_PLACEMENT_3D('',#547,#548,#549);
#551=PLANE('',#550);
#552=CARTESIAN_POINT('',(-12.0002,11.3507862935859,6.92808776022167));
#553=CARTESIAN_POINT('',(-11.7364142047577,11.4387000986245,7.08038456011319));
#554=CARTESIAN_POINT('',(-11.4716448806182,11.5226237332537,7.2332492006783));
#555=CARTESIAN_POINT('',(-10.9399829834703,11.6813835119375,7.54020434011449));
#556=CARTESIAN_POINT('',(-10.6730897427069,11.7562166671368,7.69429522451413));
#557=CARTESIAN_POINT('',(-9.86810959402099,11.9656321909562,8.15905073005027));
#558=CARTESIAN_POINT('',(-9.32684492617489,12.0847464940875,8.47155003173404));
#559=CARTESIAN_POINT('',(-8.516867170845,12.2244186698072,8.93919090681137));
#560=CARTESIAN_POINT('',(-8.25057389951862,12.2642059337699,9.09293539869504));
#561=CARTESIAN_POINT('',(-7.71675440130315,12.3309263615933,9.40113622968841));
#562=CARTESIAN_POINT('',(-7.44922815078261,12.3578592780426,9.55559258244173));
#563=CARTESIAN_POINT('',(-6.91372963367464,12.3981811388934,9.86476279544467));
#564=CARTESIAN_POINT('',(-6.64575827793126,12.4115861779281,10.0194761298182));
#565=CARTESIAN_POINT('',(-6.10956726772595,12.4245666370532,10.3290461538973));
#566=CARTESIAN_POINT('',(-5.84134762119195,12.4241424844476,10.4839028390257));
#567=CARTESIAN_POINT('',(-5.33991062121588,12.4104297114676,10.7734076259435));
#568=CARTESIAN_POINT('',(-5.10665750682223,12.3988137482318,10.908076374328));
#569=CARTESIAN_POINT('',(-4.64068775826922,12.365341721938,11.1771041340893));
#570=CARTESIAN_POINT('',(-4.40797116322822,12.3434849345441,11.3114631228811));
#571=CARTESIAN_POINT('',(-3.94320092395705,12.2899123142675,11.5797983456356));
#572=CARTESIAN_POINT('',(-3.71114798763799,12.2581883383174,11.7137741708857));
#573=CARTESIAN_POINT('',(-3.24813003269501,12.1854379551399,11.9810977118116));
#574=CARTESIAN_POINT('',(-3.01716508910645,12.1444109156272,12.1144453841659));
#575=CARTESIAN_POINT('',(-2.31605804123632,12.0063380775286,12.5192297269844));
#576=CARTESIAN_POINT('',(-1.84794625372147,11.895524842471,12.789494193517));
#577=CARTESIAN_POINT('',(-0.918702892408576,11.6440239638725,13.3259930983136));
#578=CARTESIAN_POINT('',(-0.457559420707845,11.503395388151,13.5922344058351));
#579=CARTESIAN_POINT('',(0.000199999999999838,11.3507862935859,13.8565219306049));
#580=B_SPLINE_CURVE_WITH_KNOTS('',3,(#552,#553,#554,#555,#556,#557,#558,#559,#560,#561,#562,
#563,#564,#565,#566,#567,#568,#569,#570,#571,#572,#573,#574,#575,#576,#577,#578,#579),
.UNSPECIFIED.,.F.,.F.,(4,2,2,2,2,2,2,2,2,2,2,2,2,4),(0.,0.951004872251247,1.90232158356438,
3.8090046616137,4.73894551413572,5.66890426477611,6.59775529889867,7.52657763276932,
8.3351464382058,9.14377244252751,9.95306755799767,10.7624176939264,12.4167102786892,
14.0677556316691),.UNSPECIFIED.);
#581=CARTESIAN_POINT('',(0.,11.3508529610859,13.856406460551));
#582=VERTEX_POINT('',#581);
#583=EDGE_CURVE('E551',#477,#582,#580,.T.);
#584=ORIENTED_EDGE('',*,*,#583,.F.);
#585=ORIENTED_EDGE('',*,*,#542,.T.);
#586=CARTESIAN_POINT('',(0.000199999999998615,1.36053857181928,13.8565219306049));
#587=CARTESIAN_POINT('',(-0.263585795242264,1.27262476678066,13.7042251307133));
#588=CARTESIAN_POINT('',(-0.528355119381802,1.18870113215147,13.5513604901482));
#589=CARTESIAN_POINT('',(-1.06001701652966,1.02994135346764,13.244405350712));
#590=CARTESIAN_POINT('',(-1.32691025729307,0.955108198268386,13.0903144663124));
#591=CARTESIAN_POINT('',(-2.13189040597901,0.745692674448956,12.6255589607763));
#592=CARTESIAN_POINT('',(-2.6731550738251,0.626578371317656,12.3130596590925));
#593=CARTESIAN_POINT('',(-3.48313282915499,0.486906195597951,11.8454187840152));
#594=CARTESIAN_POINT('',(-3.74942610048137,0.447118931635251,11.6916742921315));
#595=CARTESIAN_POINT('',(-4.28324559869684,0.380398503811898,11.3834734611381));
#596=CARTESIAN_POINT('',(-4.55077184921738,0.353465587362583,11.2290171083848));
#597=CARTESIAN_POINT('',(-5.08627036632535,0.313143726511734,10.9198468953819));
#598=CARTESIAN_POINT('',(-5.35424172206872,0.299738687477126,10.7651335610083));
#599=CARTESIAN_POINT('',(-5.89043273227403,0.286758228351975,10.4555635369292));
#600=CARTESIAN_POINT('',(-6.15865237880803,0.287182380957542,10.3007068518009));
#601=CARTESIAN_POINT('',(-6.6600893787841,0.300895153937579,10.011202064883));
#602=CARTESIAN_POINT('',(-6.89334249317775,0.312511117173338,9.87653331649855));
#603=CARTESIAN_POINT('',(-7.35931224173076,0.345983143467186,9.60750555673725));
#604=CARTESIAN_POINT('',(-7.59202883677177,0.367839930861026,9.47314656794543));
#605=CARTESIAN_POINT('',(-8.05679907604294,0.421412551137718,9.20481134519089));
#606=CARTESIAN_POINT('',(-8.288852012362,0.453136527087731,9.07083551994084));
#607=CARTESIAN_POINT('',(-8.75186996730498,0.525886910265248,8.80351197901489));
#608=CARTESIAN_POINT('',(-8.98283491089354,0.566913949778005,8.67016430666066));
#609=CARTESIAN_POINT('',(-9.68394195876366,0.70498678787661,8.2653799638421));
#610=CARTESIAN_POINT('',(-10.1520537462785,0.815800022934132,7.99511549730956));
#611=CARTESIAN_POINT('',(-11.0812971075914,1.06730090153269,7.45861659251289));
#612=CARTESIAN_POINT('',(-11.5424405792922,1.20792947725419,7.19237528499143));
#613=CARTESIAN_POINT('',(-12.0002,1.36053857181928,6.92808776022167));
#614=B_SPLINE_CURVE_WITH_KNOTS('',3,(#586,#587,#588,#589,#590,#591,#592,#593,#594,#595,#596,
#597,#598,#599,#600,#601,#602,#603,#604,#605,#606,#607,#608,#609,#610,#611,#612,#613),
.UNSPECIFIED.,.F.,.F.,(4,2,2,2,2,2,2,2,2,2,2,2,2,4),(0.,0.951004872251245,1.90232158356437,
3.80900466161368,4.7389455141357,5.66890426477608,6.59775529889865,7.52657763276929,
8.33514643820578,9.14377244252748,9.95306755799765,10.7624176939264,12.4167102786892,
14.0677556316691),.UNSPECIFIED.);
#615=CARTESIAN_POINT('',(0.,1.36047190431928,13.856406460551));
#616=VERTEX_POINT('',#615);
#617=EDGE_CURVE('E473',#616,#535,#614,.T.);
#618=ORIENTED_EDGE('',*,*,#617,.F.);
#619=DIRECTION('',(0.,-1.,0.));
#620=VECTOR('',#619,1.);
#621=CARTESIAN_POINT('',(0.,19.,13.856406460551));
#622=LINE('',#621,#620);
#623=EDGE_CURVE('E737',#582,#616,#622,.T.);
#624=ORIENTED_EDGE('',*,*,#623,.F.);
#625=EDGE_LOOP('',(#584,#585,#618,#624));
#626=FACE_BOUND('',#625,.T.);
#627=ADVANCED_FACE('F559',(#626),#551,.F.);
#628=CARTESIAN_POINT('',(0.,19.,13.856406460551));
#629=DIRECTION('',(-0.5,0.,-0.866025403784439));
#630=DIRECTION('',(-0.866025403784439,0.,0.5));
#631=AXIS2_PLACEMENT_3D('',#628,#629,#630);
#632=PLANE('',#631);
#633=CARTESIAN_POINT('',(-0.000200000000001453,11.3507862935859,13.8565219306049));
#634=CARTESIAN_POINT('',(0.263585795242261,11.4387000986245,13.7042251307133));
#635=CARTESIAN_POINT('',(0.528355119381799,11.5226237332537,13.5513604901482));
#636=CARTESIAN_POINT('',(1.06001701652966,11.6813835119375,13.244405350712));
#637=CARTESIAN_POINT('',(1.32691025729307,11.7562166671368,13.0903144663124));
#638=CARTESIAN_POINT('',(2.13189040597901,11.9656321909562,12.6255589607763));
#639=CARTESIAN_POINT('',(2.6731550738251,12.0847464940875,12.3130596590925));
#640=CARTESIAN_POINT('',(3.483132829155,12.2244186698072,11.8454187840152));
#641=CARTESIAN_POINT('',(3.74942610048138,12.2642059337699,11.6916742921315));
#642=CARTESIAN_POINT('',(4.28324559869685,12.3309263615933,11.3834734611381));
#643=CARTESIAN_POINT('',(4.55077184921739,12.3578592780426,11.2290171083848));
#644=CARTESIAN_POINT('',(5.08627036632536,12.3981811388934,10.9198468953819));
#645=CARTESIAN_POINT('',(5.35424172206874,12.4115861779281,10.7651335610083));
#646=CARTESIAN_POINT('',(5.89043273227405,12.4245666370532,10.4555635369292));
#647=CARTESIAN_POINT('',(6.15865237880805,12.4241424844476,10.3007068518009));
#648=CARTESIAN_POINT('',(6.66008937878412,12.4104297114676,10.011202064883));
#649=CARTESIAN_POINT('',(6.89334249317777,12.3988137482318,9.87653331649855));
#650=CARTESIAN_POINT('',(7.35931224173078,12.365341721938,9.60750555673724));
#651=CARTESIAN_POINT('',(7.59202883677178,12.3434849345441,9.47314656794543));
#652=CARTESIAN_POINT('',(8.05679907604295,12.2899123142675,9.20481134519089));
#653=CARTESIAN_POINT('',(8.28885201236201,12.2581883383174,9.07083551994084));
#654=CARTESIAN_POINT('',(8.75186996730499,12.1854379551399,8.80351197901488));
#655=CARTESIAN_POINT('',(8.98283491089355,12.1444109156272,8.67016430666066));
#656=CARTESIAN_POINT('',(9.68394195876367,12.0063380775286,8.2653799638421));
#657=CARTESIAN_POINT('',(10.1520537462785,11.895524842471,7.99511549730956));
#658=CARTESIAN_POINT('',(11.0812971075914,11.6440239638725,7.45861659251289));
#659=CARTESIAN_POINT('',(11.5424405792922,11.503395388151,7.19237528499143));
#660=CARTESIAN_POINT('',(12.0002,11.3507862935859,6.92808776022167));
#661=B_SPLINE_CURVE_WITH_KNOTS('',3,(#633,#634,#635,#636,#637,#638,#639,#640,#641,#642,#643,
#644,#645,#646,#647,#648,#649,#650,#651,#652,#653,#654,#655,#656,#657,#658,#659,#660),
.UNSPECIFIED.,.F.,.F.,(4,2,2,2,2,2,2,2,2,2,2,2,2,4),(0.,0.951004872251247,1.90232158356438,
3.8090046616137,4.73894551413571,5.66890426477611,6.59775529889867,7.52657763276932,
8.3351464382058,9.14377244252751,9.95306755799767,10.7624176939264,12.4167102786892,
14.0677556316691),.UNSPECIFIED.);
#662=CARTESIAN_POINT('',(12.,11.3508529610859,6.92820323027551));
#663=VERTEX_POINT('',#662);
#664=EDGE_CURVE('E56',#582,#663,#661,.T.);
#665=ORIENTED_EDGE('',*,*,#664,.F.);
#666=ORIENTED_EDGE('',*,*,#623,.T.);
#667=CARTESIAN_POINT('',(12.0002,1.36053857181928,6.92808776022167));
#668=CARTESIAN_POINT('',(11.7364142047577,1.27262476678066,7.08038456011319));
#669=CARTESIAN_POINT('',(11.4716448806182,1.18870113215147,7.23324920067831));
#670=CARTESIAN_POINT('',(10.9399829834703,1.02994135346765,7.54020434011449));
#671=CARTESIAN_POINT('',(10.6730897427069,0.955108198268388,7.69429522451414));
#672=CARTESIAN_POINT('',(9.86810959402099,0.745692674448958,8.15905073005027));
#673=CARTESIAN_POINT('',(9.3268449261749,0.626578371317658,8.47155003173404));
#674=CARTESIAN_POINT('',(8.516867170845,0.486906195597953,8.93919090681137));
#675=CARTESIAN_POINT('',(8.25057389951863,0.447118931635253,9.09293539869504));
#676=CARTESIAN_POINT('',(7.71675440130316,0.380398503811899,9.40113622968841));
#677=CARTESIAN_POINT('',(7.44922815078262,0.353465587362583,9.55559258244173));
#678=CARTESIAN_POINT('',(6.91372963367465,0.313143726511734,9.86476279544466));
#679=CARTESIAN_POINT('',(6.64575827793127,0.299738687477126,10.0194761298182));
#680=CARTESIAN_POINT('',(6.10956726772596,0.286758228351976,10.3290461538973));
#681=CARTESIAN_POINT('',(5.84134762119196,0.287182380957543,10.4839028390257));
#682=CARTESIAN_POINT('',(5.3399106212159,0.300895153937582,10.7734076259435));
#683=CARTESIAN_POINT('',(5.10665750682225,0.31251111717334,10.908076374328));
#684=CARTESIAN_POINT('',(4.64068775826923,0.345983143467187,11.1771041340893));
#685=CARTESIAN_POINT('',(4.40797116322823,0.367839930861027,11.3114631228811));
#686=CARTESIAN_POINT('',(3.94320092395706,0.421412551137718,11.5797983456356));
#687=CARTESIAN_POINT('',(3.711147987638,0.453136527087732,11.7137741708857));
#688=CARTESIAN_POINT('',(3.24813003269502,0.525886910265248,11.9810977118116));
#689=CARTESIAN_POINT('',(3.01716508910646,0.566913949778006,12.1144453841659));
#690=CARTESIAN_POINT('',(2.31605804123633,0.704986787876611,12.5192297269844));
#691=CARTESIAN_POINT('',(1.84794625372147,0.815800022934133,12.789494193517));
#692=CARTESIAN_POINT('',(0.918702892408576,1.06730090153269,13.3259930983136));
#693=CARTESIAN_POINT('',(0.457559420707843,1.20792947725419,13.5922344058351));
#694=CARTESIAN_POINT('',(-0.000200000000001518,1.36053857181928,13.8565219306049));
#695=B_SPLINE_CURVE_WITH_KNOTS('',3,(#667,#668,#669,#670,#671,#672,#673,#674,#675,#676,#677,
#678,#679,#680,#681,#682,#683,#684,#685,#686,#687,#688,#689,#690,#691,#692,#693,#694),
.UNSPECIFIED.,.F.,.F.,(4,2,2,2,2,2,2,2,2,2,2,2,2,4),(0.,0.951004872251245,1.90232158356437,
3.80900466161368,4.7389455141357,5.66890426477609,6.59775529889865,7.5265776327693,
8.33514643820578,9.14377244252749,9.95306755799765,10.7624176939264,12.4167102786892,
14.0677556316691),.UNSPECIFIED.);
#696=CARTESIAN_POINT('',(12.,1.36047190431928,6.9282032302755));
#697=VERTEX_POINT('',#696);
#698=EDGE_CURVE('E448',#697,#616,#695,.T.);
#699=ORIENTED_EDGE('',*,*,#698,.F.);
#700=DIRECTION('',(0.,-1.,0.));
#701=VECTOR('',#700,1.);
#702=CARTESIAN_POINT('',(12.,19.,6.92820323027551));
#703=LINE('',#702,#701);
#704=EDGE_CURVE('E736',#663,#697,#703,.T.);
#705=ORIENTED_EDGE('',*,*,#704,.F.);
#706=EDGE_LOOP('',(#665,#666,#699,#705));
#707=FACE_BOUND('',#706,.T.);
#708=ADVANCED_FACE('F561',(#707),#632,.F.);
#709=CARTESIAN_POINT('',(12.,19.,6.92820323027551));
#710=DIRECTION('',(-1.,0.,0.));
#711=DIRECTION('',(0.,0.,1.));
#712=AXIS2_PLACEMENT_3D('',#709,#710,#711);
#713=PLANE('',#712);
#714=CARTESIAN_POINT('',(12.,6.61631705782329,-18.5068963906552));
#715=CARTESIAN_POINT('',(12.,6.7430992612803,-18.2451758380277));
#716=CARTESIAN_POINT('',(12.,6.8692411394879,-17.9831452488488));
#717=CARTESIAN_POINT('',(12.,7.12009895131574,-17.4583992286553));
#718=CARTESIAN_POINT('',(12.,7.24481487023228,-17.1956837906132));
#719=CARTESIAN_POINT('',(12.,7.61663935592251,-16.4063415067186));
#720=CARTESIAN_POINT('',(12.,7.8613861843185,-15.8785978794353));
#721=CARTESIAN_POINT('',(12.,8.34441972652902,-14.8166225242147));
#722=CARTESIAN_POINT('',(12.,8.58266313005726,-14.2823710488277));
#723=CARTESIAN_POINT('',(12.,9.04925865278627,-13.2095807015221));
#724=CARTESIAN_POINT('',(12.,9.27761124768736,-12.6710420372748));
#725=CARTESIAN_POINT('',(12.,9.72860337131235,-11.5722513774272));
#726=CARTESIAN_POINT('',(12.,9.95085446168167,-11.0118391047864));
#727=CARTESIAN_POINT('',(12.,10.3782855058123,-9.88441748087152));
#728=CARTESIAN_POINT('',(12.,10.5834635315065,-9.31740739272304));
#729=CARTESIAN_POINT('',(12.,10.9712865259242,-8.17699991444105));
#730=CARTESIAN_POINT('',(12.,11.1539779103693,-7.60361843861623));
#731=CARTESIAN_POINT('',(12.,11.4909093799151,-6.44857975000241));
#732=CARTESIAN_POINT('',(12.,11.645158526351,-5.86692523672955));
#733=CARTESIAN_POINT('',(12.,11.849176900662,-4.98964275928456));
#734=CARTESIAN_POINT('',(12.,11.9125002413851,-4.69714706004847));
#735=CARTESIAN_POINT('',(12.,12.0292491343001,-4.11017669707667));
#736=CARTESIAN_POINT('',(12.,12.0826748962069,-3.81570207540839));
#737=CARTESIAN_POINT('',(12.,12.1786790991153,-3.22498620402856));
#738=CARTESIAN_POINT('',(12.,12.221257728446,-2.92874498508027));
#739=CARTESIAN_POINT('',(12.,12.2947149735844,-2.33481663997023));
#740=CARTESIAN_POINT('',(12.,12.3255940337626,-2.03712956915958));
#741=CARTESIAN_POINT('',(12.,12.374657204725,-1.44456751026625));
#742=CARTESIAN_POINT('',(12.,12.3929997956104,-1.14970572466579));
#743=CARTESIAN_POINT('',(12.,12.4172064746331,-0.559471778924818));
#744=CARTESIAN_POINT('',(12.,12.423070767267,-0.264099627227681));
#745=CARTESIAN_POINT('',(12.,12.4221816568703,0.326634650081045));
#746=CARTESIAN_POINT('',(12.,12.4154279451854,0.621996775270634));
#747=CARTESIAN_POINT('',(12.,12.389465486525,1.21217665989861));
#748=CARTESIAN_POINT('',(12.,12.3702561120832,1.50699439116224));
#749=CARTESIAN_POINT('',(12.,12.3092804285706,2.21836923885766));
#750=CARTESIAN_POINT('',(12.,12.2614476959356,2.63441698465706));
#751=CARTESIAN_POINT('',(12.,12.14360785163,3.46333964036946));
#752=CARTESIAN_POINT('',(12.,12.0735976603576,3.87621410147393));
#753=CARTESIAN_POINT('',(12.,11.8340215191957,5.10962525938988));
#754=CARTESIAN_POINT('',(12.,11.6349533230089,5.92450248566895));
#755=CARTESIAN_POINT('',(12.,11.2906713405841,7.14347200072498));
#756=CARTESIAN_POINT('',(12.,11.1666089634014,7.55389948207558));
#757=CARTESIAN_POINT('',(12.,10.9058568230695,8.37076322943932));
#758=CARTESIAN_POINT('',(12.,10.7691669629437,8.77719946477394));
#759=CARTESIAN_POINT('',(12.,10.4853306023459,9.58622174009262));
#760=CARTESIAN_POINT('',(12.,10.3381875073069,9.98880898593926));
#761=CARTESIAN_POINT('',(12.,10.0351583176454,10.7906604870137));
#762=CARTESIAN_POINT('',(12.,9.87927243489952,11.1899248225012));
#763=CARTESIAN_POINT('',(12.,9.57772538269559,11.9418144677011));
#764=CARTESIAN_POINT('',(12.,9.43282221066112,12.2947449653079));
#765=CARTESIAN_POINT('',(12.,9.13806186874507,12.9985340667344));
#766=CARTESIAN_POINT('',(12.,8.98820461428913,13.3493926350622));
#767=CARTESIAN_POINT('',(12.,8.53226371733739,14.3992708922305));
#768=CARTESIAN_POINT('',(12.,8.21983424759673,15.0955357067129));
#769=CARTESIAN_POINT('',(12.,7.58228245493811,16.4825193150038));
#770=CARTESIAN_POINT('',(12.,7.25715523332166,17.1732358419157));
#771=CARTESIAN_POINT('',(12.,6.59733543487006,18.5500383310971));
#772=CARTESIAN_POINT('',(12.,6.26264326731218,19.2361244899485));
#773=CARTESIAN_POINT('',(12.,5.58530906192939,20.6057159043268));
#774=CARTESIAN_POINT('',(12.,5.24265518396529,21.2892152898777));
#775=CARTESIAN_POINT('',(12.,4.55149468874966,22.6532515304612));
#776=CARTESIAN_POINT('',(12.,4.2029880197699,23.3337883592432));
#777=CARTESIAN_POINT('',(12.,3.50138060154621,24.6922957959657));
#778=CARTESIAN_POINT('',(12.,3.14828088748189,25.3702669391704));
#779=CARTESIAN_POINT('',(12.,2.4382952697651,26.7242189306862));
#780=CARTESIAN_POINT('',(12.,2.08140937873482,27.4001997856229));
#781=CARTESIAN_POINT('',(12.,1.08478172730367,29.2775044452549));
#782=CARTESIAN_POINT('',(12.,0.441687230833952,30.4770479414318));
#783=CARTESIAN_POINT('',(12.,-0.851584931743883,32.8724004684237));
#784=CARTESIAN_POINT('',(12.,-1.50176304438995,34.0682092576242));
#785=CARTESIAN_POINT('',(12.,-2.80525676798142,36.4530745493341));
#786=CARTESIAN_POINT('',(12.,-3.45855534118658,37.6421403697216));
#787=CARTESIAN_POINT('',(12.,-4.44147274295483,39.424038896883));
#788=CARTESIAN_POINT('',(12.,-4.76959400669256,40.0176986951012));
#789=CARTESIAN_POINT('',(12.,-5.42672288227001,41.2045267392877));
#790=CARTESIAN_POINT('',(12.,-5.75573049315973,41.7976949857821));
#791=CARTESIAN_POINT('',(12.,-6.08512571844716,42.3906479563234));
#792=B_SPLINE_CURVE_WITH_KNOTS('',3,(#714,#715,#716,#717,#718,#719,#720,#721,#722,#723,#724,
#725,#726,#727,#728,#729,#730,#731,#732,#733,#734,#735,#736,#737,#738,#739,#740,#741,#742,#743,
#744,#745,#746,#747,#748,#749,#750,#751,#752,#753,#754,#755,#756,#757,#758,#759,#760,#761,#762,
#763,#764,#765,#766,#767,#768,#769,#770,#771,#772,#773,#774,#775,#776,#777,#778,#779,#780,#781,
#782,#783,#784,#785,#786,#787,#788,#789,#790,#791),.UNSPECIFIED.,.F.,.F.,(4,2,2,2,2,2,2,2,2,2,2,
2,2,2,2,2,2,2,2,2,2,2,2,2,2,2,2,2,2,2,2,2,2,2,2,2,2,2,4),(0.,0.872433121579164,1.74487523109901,
3.49002354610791,5.24484180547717,6.99957557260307,8.80798621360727,10.6166008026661,
12.4214172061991,14.2256576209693,15.1233324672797,16.0209882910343,16.9186285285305,
17.8162346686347,18.7022727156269,19.5882962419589,20.4743414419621,21.3604312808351,
22.616085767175,23.8719146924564,26.3849145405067,27.6711149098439,28.9573251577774,
30.2431182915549,31.5288802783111,32.6733957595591,33.8179307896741,36.1071867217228,
38.3973347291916,40.6873848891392,42.9810915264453,45.2748184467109,47.5680370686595,
49.8612480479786,53.9443807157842,58.0277722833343,62.0979076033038,64.1328172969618,
66.1677248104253),.UNSPECIFIED.);
#793=EDGE_CURVE('E538',#663,#256,#792,.F.);
#794=ORIENTED_EDGE('',*,*,#793,.F.);
#795=ORIENTED_EDGE('',*,*,#704,.T.);
#796=CARTESIAN_POINT('',(12.,6.0116615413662,-18.3346065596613));
#797=CARTESIAN_POINT('',(12.,5.88448426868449,-18.071337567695));
#798=CARTESIAN_POINT('',(12.,5.75796841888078,-17.8077492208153));
#799=CARTESIAN_POINT('',(12.,5.50641147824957,-17.2798663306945));
#800=CARTESIAN_POINT('',(12.,5.38137040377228,-17.0155717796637));
#801=CARTESIAN_POINT('',(12.,5.00865069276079,-16.221449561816));
#802=CARTESIAN_POINT('',(12.,4.76341736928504,-15.6904696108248));
#803=CARTESIAN_POINT('',(12.,4.27965104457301,-14.6217679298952));
#804=CARTESIAN_POINT('',(12.,4.04116479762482,-14.0840249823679));
#805=CARTESIAN_POINT('',(12.,3.57448957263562,-13.004105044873));
#806=CARTESIAN_POINT('',(12.,3.34630005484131,-12.461928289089));
#807=CARTESIAN_POINT('',(12.,2.90033193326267,-11.3657346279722));
#808=CARTESIAN_POINT('',(12.,2.68271002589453,-10.8116536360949));
#809=CARTESIAN_POINT('',(12.,2.26460970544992,-9.69693816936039));
#810=CARTESIAN_POINT('',(12.,2.06413320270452,-9.13630297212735));
#811=CARTESIAN_POINT('',(12.,1.68574234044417,-8.0087706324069));
#812=CARTESIAN_POINT('',(12.,1.50777966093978,-7.44188984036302));
#813=CARTESIAN_POINT('',(12.,1.1802133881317,-6.30001630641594));
#814=CARTESIAN_POINT('',(12.,1.03060079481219,-5.72502620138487));
#815=CARTESIAN_POINT('',(12.,0.832938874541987,-4.85634692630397));
#816=CARTESIAN_POINT('',(12.,0.771499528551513,-4.56568429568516));
#817=CARTESIAN_POINT('',(12.,0.658515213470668,-3.98243264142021));
#818=CARTESIAN_POINT('',(12.,0.606970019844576,-3.68984366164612));
#819=CARTESIAN_POINT('',(12.,0.514689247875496,-3.10293318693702));
#820=CARTESIAN_POINT('',(12.,0.473954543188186,-2.80861155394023));
#821=CARTESIAN_POINT('',(12.,0.404116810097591,-2.21859253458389));
#822=CARTESIAN_POINT('',(12.,0.375013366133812,-1.92289519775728));
#823=CARTESIAN_POINT('',(12.,0.329216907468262,-1.33239351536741));
#824=CARTESIAN_POINT('',(12.,0.312447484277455,-1.03759513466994));
#825=CARTESIAN_POINT('',(12.,0.291407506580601,-0.44755424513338));
#826=CARTESIAN_POINT('',(12.,0.28713676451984,-0.152311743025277));
#827=CARTESIAN_POINT('',(12.,0.291195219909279,0.438005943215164));
#828=CARTESIAN_POINT('',(12.,0.299520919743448,0.733081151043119));
#829=CARTESIAN_POINT('',(12.,0.328566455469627,1.32262470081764));
#830=CARTESIAN_POINT('',(12.,0.349286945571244,1.6170930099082));
#831=CARTESIAN_POINT('',(12.,0.414195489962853,2.33186551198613));
#832=CARTESIAN_POINT('',(12.,0.464653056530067,2.75161135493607));
#833=CARTESIAN_POINT('',(12.,0.587933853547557,3.58778782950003));
#834=CARTESIAN_POINT('',(12.,0.66076043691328,4.00421795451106));
#835=CARTESIAN_POINT('',(12.,0.909137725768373,5.24927450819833));
#836=CARTESIAN_POINT('',(12.,1.11441917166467,6.07203707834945));
#837=CARTESIAN_POINT('',(12.,1.46805079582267,7.30267412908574));
#838=CARTESIAN_POINT('',(12.,1.59526318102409,7.71698679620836));
#839=CARTESIAN_POINT('',(12.,1.86228669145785,8.54160931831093));
#840=CARTESIAN_POINT('',(12.,2.00209894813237,8.95191881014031));
#841=CARTESIAN_POINT('',(12.,2.29134955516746,9.76648835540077));
#842=CARTESIAN_POINT('',(12.,2.44072902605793,10.1707694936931));
#843=CARTESIAN_POINT('',(12.,2.67122411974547,10.7746497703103));
#844=CARTESIAN_POINT('',(12.,2.74911366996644,10.9754873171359));
#845=CARTESIAN_POINT('',(12.,2.90686066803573,11.3763838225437));
#846=CARTESIAN_POINT('',(12.,2.9867180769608,11.5764427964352));
#847=CARTESIAN_POINT('',(12.,3.06747047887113,11.7761396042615));
#848=B_SPLINE_CURVE_WITH_KNOTS('',3,(#796,#797,#798,#799,#800,#801,#802,#803,#804,#805,#806,
#807,#808,#809,#810,#811,#812,#813,#814,#815,#816,#817,#818,#819,#820,#821,#822,#823,#824,#825,
#826,#827,#828,#829,#830,#831,#832,#833,#834,#835,#836,#837,#838,#839,#840,#841,#842,#843,#844,
#845,#846,#847),.UNSPECIFIED.,.F.,.F.,(4,2,2,2,2,2,2,2,2,2,2,2,2,2,2,2,2,2,2,2,2,2,2,2,2,4),(0.,
0.877130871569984,1.75427145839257,3.50884023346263,5.2735197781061,7.03810671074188,
8.82374707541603,10.609586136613,12.3915248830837,14.172896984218,15.0640109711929,
15.9551047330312,16.846270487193,17.737404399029,18.6229701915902,19.5085226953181,
20.393829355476,21.2791827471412,22.5467648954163,23.8145371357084,26.3549754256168,
27.6550829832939,28.9553074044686,30.2481822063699,30.8944104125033,31.5406258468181),.UNSPECIFIED.);
#849=EDGE_CURVE('E437',#266,#697,#848,.T.);
#850=ORIENTED_EDGE('',*,*,#849,.F.);
#851=ORIENTED_EDGE('',*,*,#267,.F.);
#852=EDGE_LOOP('',(#794,#795,#850,#851));
#853=FACE_BOUND('',#852,.T.);
#854=ADVANCED_FACE('F454',(#853),#713,.F.);
#855=CARTESIAN_POINT('',(-28.8,13.,2.25));
#856=DIRECTION('',(0.,-1.,0.));
#857=DIRECTION('',(0.,0.,-1.));
#858=AXIS2_PLACEMENT_3D('',#855,#856,#857);
#859=PLANE('',#858);
#860=CARTESIAN_POINT('',(0.,13.,0.));
#861=DIRECTION('',(0.,-1.,0.));
#862=DIRECTION('',(0.,0.,-1.));
#863=AXIS2_PLACEMENT_3D('',#860,#861,#862);
#864=CIRCLE('',#863,11.);
#865=CARTESIAN_POINT('',(-10.767427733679,13.,2.25));
#866=VERTEX_POINT('',#865);
#867=CARTESIAN_POINT('',(-10.767427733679,13.,-2.25));
#868=VERTEX_POINT('',#867);
#869=EDGE_CURVE('E1067',#866,#868,#864,.T.);
#870=ORIENTED_EDGE('',*,*,#869,.F.);
#871=DIRECTION('',(1.,0.,0.));
#872=VECTOR('',#871,1.);
#873=CARTESIAN_POINT('',(-28.8,13.,2.25));
#874=LINE('',#873,#872);
#875=CARTESIAN_POINT('',(-6.62853679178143,13.,2.25));
#876=VERTEX_POINT('',#875);
#877=EDGE_CURVE('E413',#866,#876,#874,.T.);
#878=ORIENTED_EDGE('',*,*,#877,.T.);
#879=CARTESIAN_POINT('',(0.,13.,0.));
#880=DIRECTION('',(0.,-1.,0.));
#881=DIRECTION('',(0.,0.,-1.));
#882=AXIS2_PLACEMENT_3D('',#879,#880,#881);
#883=CIRCLE('',#882,7.);
#884=CARTESIAN_POINT('',(-6.62853679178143,13.,-2.25));
#885=VERTEX_POINT('',#884);
#886=EDGE_CURVE('E963',#876,#885,#883,.T.);
#887=ORIENTED_EDGE('',*,*,#886,.T.);
#888=DIRECTION('',(1.,0.,0.));
#889=VECTOR('',#888,1.);
#890=CARTESIAN_POINT('',(-28.8,13.,-2.25));
#891=LINE('',#890,#889);
#892=EDGE_CURVE('E415',#868,#885,#891,.T.);
#893=ORIENTED_EDGE('',*,*,#892,.F.);
#894=EDGE_LOOP('',(#870,#878,#887,#893));
#895=FACE_BOUND('',#894,.T.);
#896=ADVANCED_FACE('F573',(#895),#859,.F.);
#897=CARTESIAN_POINT('',(-28.8,32.,2.25));
#898=DIRECTION('',(0.,0.,1.));
#899=DIRECTION('',(0.,-1.,0.));
#900=AXIS2_PLACEMENT_3D('',#897,#898,#899);
#901=PLANE('',#900);
#902=DIRECTION('',(0.,-1.,0.));
#903=VECTOR('',#902,1.);
#904=CARTESIAN_POINT('',(-10.767427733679,0.,2.25));
#905=LINE('',#904,#903);
#906=EDGE_CURVE('E684',#69,#866,#905,.T.);
#907=ORIENTED_EDGE('',*,*,#906,.F.);
#908=ORIENTED_EDGE('',*,*,#88,.F.);
#909=CARTESIAN_POINT('',(-14.147419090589,22.1792185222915,2.25));
#910=CARTESIAN_POINT('',(-13.8443868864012,22.0064365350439,2.25));
#911=CARTESIAN_POINT('',(-13.5412977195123,21.8337543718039,2.25));
#912=CARTESIAN_POINT('',(-12.9349753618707,21.4886424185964,2.25));
#913=CARTESIAN_POINT('',(-12.63174217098,21.3162126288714,2.25));
#914=CARTESIAN_POINT('',(-11.7217390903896,20.799356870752,2.25));
#915=CARTESIAN_POINT('',(-11.1147088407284,20.4553891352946,2.25));
#916=CARTESIAN_POINT('',(-9.90132730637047,19.7703569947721,2.25));
#917=CARTESIAN_POINT('',(-9.29497914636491,19.4292870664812,2.25));
#918=CARTESIAN_POINT('',(-8.3840753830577,18.9201863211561,2.25));
#919=CARTESIAN_POINT('',(-8.08021770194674,18.7509073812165,2.25));
#920=CARTESIAN_POINT('',(-7.47185991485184,18.4135078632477,2.25));
#921=CARTESIAN_POINT('',(-7.16735981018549,18.2453872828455,2.25));
#922=CARTESIAN_POINT('',(-6.5551718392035,17.909531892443,2.25));
#923=CARTESIAN_POINT('',(-6.24747719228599,17.7418094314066,2.25));
#924=CARTESIAN_POINT('',(-5.63072550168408,17.408810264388,2.25));
#925=CARTESIAN_POINT('',(-5.32166833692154,17.2435337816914,2.25));
#926=CARTESIAN_POINT('',(-4.85613880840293,16.9983482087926,2.25));
#927=CARTESIAN_POINT('',(-4.70043929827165,16.9169729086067,2.25));
#928=CARTESIAN_POINT('',(-4.38837610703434,16.7555073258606,2.25));
#929=CARTESIAN_POINT('',(-4.23201243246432,16.6754170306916,2.25));
#930=CARTESIAN_POINT('',(-3.91845474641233,16.5169347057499,2.25));
#931=CARTESIAN_POINT('',(-3.76126086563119,16.4385424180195,2.25));
#932=CARTESIAN_POINT('',(-3.44576161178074,16.2840328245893,2.25));
#933=CARTESIAN_POINT('',(-3.28745627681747,16.2079154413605,2.25));
#934=CARTESIAN_POINT('',(-2.96384426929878,16.0562302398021,2.25));
#935=CARTESIAN_POINT('',(-2.79848534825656,15.9807732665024,2.25));
#936=CARTESIAN_POINT('',(-2.46565316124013,15.8347040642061,2.25));
#937=CARTESIAN_POINT('',(-2.29818026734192,15.7640909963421,2.25));
#938=CARTESIAN_POINT('',(-1.96074475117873,15.6301755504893,2.25));
#939=CARTESIAN_POINT('',(-1.79078870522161,15.5668568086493,2.25));
#940=CARTESIAN_POINT('',(-1.44719648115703,15.4509970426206,2.25));
#941=CARTESIAN_POINT('',(-1.27356197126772,15.3984512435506,2.25));
#942=CARTESIAN_POINT('',(-0.975070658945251,15.3228966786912,2.25));
#943=CARTESIAN_POINT('',(-0.851276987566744,15.2957584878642,2.25));
#944=CARTESIAN_POINT('',(-0.601900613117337,15.2515224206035,2.25));
#945=CARTESIAN_POINT('',(-0.476318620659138,15.234420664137,2.25));
#946=CARTESIAN_POINT('',(-0.224633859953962,15.2120819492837,2.25));
#947=CARTESIAN_POINT('',(-0.0985359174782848,15.2067923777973,2.25));
#948=CARTESIAN_POINT('',(0.153582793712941,15.2085744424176,2.25));
#949=CARTESIAN_POINT('',(0.279603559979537,15.2156464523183,2.25));
#950=CARTESIAN_POINT('',(0.488082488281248,15.2369545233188,2.25));
#951=CARTESIAN_POINT('',(0.57089230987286,15.2479682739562,2.25));
#952=CARTESIAN_POINT('',(0.735789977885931,15.2745187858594,2.25));
#953=CARTESIAN_POINT('',(0.81787770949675,15.2900562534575,2.25));
#954=CARTESIAN_POINT('',(1.06301846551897,15.3425895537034,2.25));
#955=CARTESIAN_POINT('',(1.22481290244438,15.3854905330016,2.25));
#956=CARTESIAN_POINT('',(1.46622297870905,15.4585497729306,2.25));
#957=CARTESIAN_POINT('',(1.54715205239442,15.4846103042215,2.25));
#958=CARTESIAN_POINT('',(1.70815790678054,15.5390959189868,2.25));
#959=CARTESIAN_POINT('',(1.78823520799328,15.5675194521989,2.25));
#960=CARTESIAN_POINT('',(2.0273570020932,15.6556945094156,2.25));
#961=CARTESIAN_POINT('',(2.18532270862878,15.7183603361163,2.25));
#962=CARTESIAN_POINT('',(2.4732801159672,15.8382652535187,2.25));
#963=CARTESIAN_POINT('',(2.60360939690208,15.894707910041,2.25));
#964=CARTESIAN_POINT('',(2.86303828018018,16.0103477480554,2.25));
#965=CARTESIAN_POINT('',(2.99213787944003,16.0695449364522,2.25));
#966=CARTESIAN_POINT('',(3.24941407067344,16.1900344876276,2.25));
#967=CARTESIAN_POINT('',(3.37759027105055,16.2513276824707,2.25));
#968=CARTESIAN_POINT('',(3.63316929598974,16.3755069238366,2.25));
#969=CARTESIAN_POINT('',(3.76057210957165,16.438392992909,2.25));
#970=CARTESIAN_POINT('',(4.00870358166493,16.5623838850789,2.25));
#971=CARTESIAN_POINT('',(4.12946117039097,16.6234309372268,2.25));
#972=CARTESIAN_POINT('',(4.37051475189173,16.7464300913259,2.25));
#973=CARTESIAN_POINT('',(4.49081074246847,16.80838219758,2.25));
#974=CARTESIAN_POINT('',(4.7308989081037,16.9329560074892,2.25));
#975=CARTESIAN_POINT('',(4.85069147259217,16.9955769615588,2.25));
#976=CARTESIAN_POINT('',(5.08995439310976,17.1214250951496,2.25));
#977=CARTESIAN_POINT('',(5.20942475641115,17.184652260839,2.25));
#978=CARTESIAN_POINT('',(5.32876574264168,17.2481211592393,2.25));
#979=B_SPLINE_CURVE_WITH_KNOTS('',3,(#909,#910,#911,#912,#913,#914,#915,#916,#917,#918,#919,
#920,#921,#922,#923,#924,#925,#926,#927,#928,#929,#930,#931,#932,#933,#934,#935,#936,#937,#938,
#939,#940,#941,#942,#943,#944,#945,#946,#947,#948,#949,#950,#951,#952,#953,#954,#955,#956,#957,
#958,#959,#960,#961,#962,#963,#964,#965,#966,#967,#968,#969,#970,#971,#972,#973,#974,#975,#976,
#977,#978),.UNSPECIFIED.,.F.,.F.,(4,2,2,2,2,2,2,2,2,2,2,2,2,2,2,2,2,2,2,2,2,2,2,2,2,2,2,2,2,2,2,
2,2,2,4),(0.,1.04648901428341,2.09297903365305,4.18610810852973,6.27317553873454,
7.31666018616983,8.36014269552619,9.41145093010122,10.4628545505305,10.9898971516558,
11.5169345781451,12.0438913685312,12.5708301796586,13.1160648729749,13.661204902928,
14.2050971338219,14.7487477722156,15.128625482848,15.5083562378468,15.8863922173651,
16.2644396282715,16.5149309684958,16.765461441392,17.266931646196,17.5219788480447,
17.7768600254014,18.2865240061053,18.7125707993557,19.138618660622,19.5648376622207,
19.991062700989,20.3969919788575,20.8029231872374,21.208439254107,21.6139460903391),.UNSPECIFIED.);
#980=CARTESIAN_POINT('',(-6.62853679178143,17.95,2.25));
#981=VERTEX_POINT('',#980);
#982=EDGE_CURVE('E660',#81,#981,#979,.T.);
#983=ORIENTED_EDGE('',*,*,#982,.T.);
#984=DIRECTION('',(0.,-1.,0.));
#985=VECTOR('',#984,1.);
#986=CARTESIAN_POINT('',(-6.62853679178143,19.,2.25));
#987=LINE('',#986,#985);
#988=EDGE_CURVE('E422',#981,#876,#987,.T.);
#989=ORIENTED_EDGE('',*,*,#988,.T.);
#990=ORIENTED_EDGE('',*,*,#877,.F.);
#991=EDGE_LOOP('',(#907,#908,#983,#989,#990));
#992=FACE_BOUND('',#991,.T.);
#993=ADVANCED_FACE('F667',(#992),#901,.F.);
#994=CARTESIAN_POINT('',(-28.8,32.,-2.25));
#995=DIRECTION('',(0.,0.,-1.));
#996=DIRECTION('',(0.,1.,0.));
#997=AXIS2_PLACEMENT_3D('',#994,#995,#996);
#998=PLANE('',#997);
#999=DIRECTION('',(0.,-1.,0.));
#1000=VECTOR('',#999,1.);
#1001=CARTESIAN_POINT('',(-10.767427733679,0.,-2.25));
#1002=LINE('',#1001,#1000);
#1003=EDGE_CURVE('E784',#868,#163,#1002,.F.);
#1004=ORIENTED_EDGE('',*,*,#1003,.F.);
#1005=ORIENTED_EDGE('',*,*,#892,.T.);
#1006=DIRECTION('',(0.,-1.,0.));
#1007=VECTOR('',#1006,1.);
#1008=CARTESIAN_POINT('',(-6.62853679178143,19.,-2.25));
#1009=LINE('',#1008,#1007);
#1010=CARTESIAN_POINT('',(-6.62853679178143,17.95,-2.25));
#1011=VERTEX_POINT('',#1010);
#1012=EDGE_CURVE('E412',#885,#1011,#1009,.F.);
#1013=ORIENTED_EDGE('',*,*,#1012,.T.);
#1014=CARTESIAN_POINT('',(5.32876574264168,17.2481211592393,-2.25));
#1015=CARTESIAN_POINT('',(5.20800255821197,17.1838961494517,-2.25));
#1016=CARTESIAN_POINT('',(5.08710701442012,17.1199183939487,-2.25));
#1017=CARTESIAN_POINT('',(4.84498706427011,16.9925860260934,-2.25));
#1018=CARTESIAN_POINT('',(4.72376265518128,16.9292314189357,-2.25));
#1019=CARTESIAN_POINT('',(4.48078757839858,16.8032048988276,-2.25));
#1020=CARTESIAN_POINT('',(4.35903647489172,16.7405338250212,-2.25));
#1021=CARTESIAN_POINT('',(4.11505637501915,16.6161246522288,-2.25));
#1022=CARTESIAN_POINT('',(3.99282737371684,16.5543865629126,-2.25));
#1023=CARTESIAN_POINT('',(3.74137518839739,16.4288777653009,-2.25));
#1024=CARTESIAN_POINT('',(3.61212066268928,16.3651697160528,-2.25));
#1025=CARTESIAN_POINT('',(3.35280551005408,16.2394170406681,-2.25));
#1026=CARTESIAN_POINT('',(3.22274489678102,16.1773723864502,-2.25));
#1027=CARTESIAN_POINT('',(2.9616556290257,16.0554838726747,-2.25));
#1028=CARTESIAN_POINT('',(2.83062738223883,15.9956391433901,-2.25));
#1029=CARTESIAN_POINT('',(2.5672866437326,15.8788567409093,-2.25));
#1030=CARTESIAN_POINT('',(2.43497424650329,15.8219188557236,-2.25));
#1031=CARTESIAN_POINT('',(2.15820021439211,15.7076425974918,-2.25));
#1032=CARTESIAN_POINT('',(2.01360386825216,15.6506272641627,-2.25));
#1033=CARTESIAN_POINT('',(1.72203264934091,15.5431033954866,-2.25));
#1034=CARTESIAN_POINT('',(1.5750586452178,15.4925925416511,-2.25));
#1035=CARTESIAN_POINT('',(1.28071025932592,15.4015916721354,-2.25));
#1036=CARTESIAN_POINT('',(1.13338503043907,15.3609460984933,-2.25));
#1037=CARTESIAN_POINT('',(0.83582854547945,15.2920980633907,-2.25));
#1038=CARTESIAN_POINT('',(0.685599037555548,15.2638883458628,-2.25));
#1039=CARTESIAN_POINT('',(0.408772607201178,15.2269698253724,-2.25));
#1040=CARTESIAN_POINT('',(0.282518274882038,15.2157544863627,-2.25));
#1041=CARTESIAN_POINT('',(0.0295399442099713,15.2056574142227,-2.25));
#1042=CARTESIAN_POINT('',(-0.0971838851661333,15.2067716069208,-2.25));
#1043=CARTESIAN_POINT('',(-0.35078504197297,15.2212424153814,-2.25));
#1044=CARTESIAN_POINT('',(-0.477657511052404,15.2346825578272,-2.25));
#1045=CARTESIAN_POINT('',(-0.666704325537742,15.2629558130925,-2.25));
#1046=CARTESIAN_POINT('',(-0.729524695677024,15.2737360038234,-2.25));
#1047=CARTESIAN_POINT('',(-0.854693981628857,15.2977354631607,-2.25));
#1048=CARTESIAN_POINT('',(-0.917042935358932,15.3109545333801,-2.25));
#1049=CARTESIAN_POINT('',(-1.09019656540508,15.3508435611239,-2.25));
#1050=CARTESIAN_POINT('',(-1.20045176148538,15.3799019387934,-2.25));
#1051=CARTESIAN_POINT('',(-1.41938596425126,15.4434959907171,-2.25));
#1052=CARTESIAN_POINT('',(-1.52806432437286,15.4780338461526,-2.25));
#1053=CARTESIAN_POINT('',(-1.74413694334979,15.5513980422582,-2.25));
#1054=CARTESIAN_POINT('',(-1.85152897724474,15.590230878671,-2.25));
#1055=CARTESIAN_POINT('',(-2.065048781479,15.6711640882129,-2.25));
#1056=CARTESIAN_POINT('',(-2.1711767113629,15.7132640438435,-2.25));
#1057=CARTESIAN_POINT('',(-2.3829241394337,15.8002193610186,-2.25));
#1058=CARTESIAN_POINT('',(-2.48853829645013,15.845087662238,-2.25));
#1059=CARTESIAN_POINT('',(-2.69889363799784,15.9368309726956,-2.25));
#1060=CARTESIAN_POINT('',(-2.8036347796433,15.9837060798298,-2.25));
#1061=CARTESIAN_POINT('',(-3.11660279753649,16.126603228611,-2.25));
#1062=CARTESIAN_POINT('',(-3.32375573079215,16.2249734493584,-2.25));
#1063=CARTESIAN_POINT('',(-3.74071978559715,16.4279892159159,-2.25));
#1064=CARTESIAN_POINT('',(-3.95048595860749,16.5327261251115,-2.25));
#1065=CARTESIAN_POINT('',(-4.36860995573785,16.7450586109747,-2.25));
#1066=CARTESIAN_POINT('',(-4.57696752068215,16.8526546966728,-2.25));
#1067=CARTESIAN_POINT('',(-4.9919765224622,17.0694856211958,-2.25));
#1068=CARTESIAN_POINT('',(-5.19863128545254,17.1787141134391,-2.25));
#1069=CARTESIAN_POINT('',(-5.61117614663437,17.3986073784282,-2.25));
#1070=CARTESIAN_POINT('',(-5.81706623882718,17.5092721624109,-2.25));
#1071=CARTESIAN_POINT('',(-6.37287583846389,17.809869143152,-2.25));
#1072=CARTESIAN_POINT('',(-6.72224904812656,18.0008105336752,-2.25));
#1073=CARTESIAN_POINT('',(-7.41992205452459,18.3846578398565,-2.25));
#1074=CARTESIAN_POINT('',(-7.76822182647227,18.577563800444,-2.25));
#1075=CARTESIAN_POINT('',(-8.46449444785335,18.9649472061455,-2.25));
#1076=CARTESIAN_POINT('',(-8.81246640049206,19.1594262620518,-2.25));
#1077=CARTESIAN_POINT('',(-9.50787790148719,19.54933368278,-2.25));
#1078=CARTESIAN_POINT('',(-9.85531744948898,19.7447620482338,-2.25));
#1079=CARTESIAN_POINT('',(-10.5320210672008,20.1262900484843,-2.25));
#1080=CARTESIAN_POINT('',(-10.8613047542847,20.3123549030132,-2.25));
#1081=CARTESIAN_POINT('',(-11.519600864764,20.6849656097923,-2.25));
#1082=CARTESIAN_POINT('',(-11.8486132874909,20.8715114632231,-2.25));
#1083=CARTESIAN_POINT('',(-12.5060215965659,21.2447483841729,-2.25));
#1084=CARTESIAN_POINT('',(-12.8344177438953,21.4314389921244,-2.25));
#1085=CARTESIAN_POINT('',(-13.4910374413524,21.8051210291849,-2.25));
#1086=CARTESIAN_POINT('',(-13.8192609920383,21.992112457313,-2.25));
#1087=CARTESIAN_POINT('',(-14.147419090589,22.1792185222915,-2.25));
#1088=B_SPLINE_CURVE_WITH_KNOTS('',3,(#1014,#1015,#1016,#1017,#1018,#1019,#1020,#1021,#1022,
#1023,#1024,#1025,#1026,#1027,#1028,#1029,#1030,#1031,#1032,#1033,#1034,#1035,#1036,#1037,#1038,
#1039,#1040,#1041,#1042,#1043,#1044,#1045,#1046,#1047,#1048,#1049,#1050,#1051,#1052,#1053,#1054,
#1055,#1056,#1057,#1058,#1059,#1060,#1061,#1062,#1063,#1064,#1065,#1066,#1067,#1068,#1069,#1070,
#1071,#1072,#1073,#1074,#1075,#1076,#1077,#1078,#1079,#1080,#1081,#1082,#1083,#1084,#1085,#1086,
#1087),.UNSPECIFIED.,.F.,.F.,(4,2,2,2,2,2,2,2,2,2,2,2,2,2,2,2,2,2,2,2,2,2,2,2,2,2,2,2,2,2,2,2,2,
2,2,2,4),(0.,0.410338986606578,0.820681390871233,1.23148091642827,1.64228469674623,
2.07458218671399,2.50687237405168,2.93898977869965,3.37107562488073,3.83726250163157,
4.3032827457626,4.76139179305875,5.21923318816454,5.59893411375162,5.97850957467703,
6.3606763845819,6.5518525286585,6.74301312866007,7.08487496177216,7.42687322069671,
7.76939598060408,8.11187504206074,8.45609811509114,8.80033799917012,9.48822743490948,
10.19158267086,10.8950639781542,11.5962939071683,12.2975293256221,13.4919560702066,
14.6864101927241,15.8823006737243,17.0781919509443,18.2128415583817,19.3474939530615,
20.4807531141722,21.6140085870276),.UNSPECIFIED.);
#1089=EDGE_CURVE('E648',#1011,#173,#1088,.T.);
#1090=ORIENTED_EDGE('',*,*,#1089,.T.);
#1091=ORIENTED_EDGE('',*,*,#174,.F.);
#1092=EDGE_LOOP('',(#1004,#1005,#1013,#1090,#1091));
#1093=FACE_BOUND('',#1092,.T.);
#1094=ADVANCED_FACE('F661',(#1093),#998,.F.);
#1095=CARTESIAN_POINT('',(-12.4514428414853,32.,-26.0665316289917));
#1096=DIRECTION('',(0.866025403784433,0.,-0.50000000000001));
#1097=DIRECTION('',(-0.50000000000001,0.,-0.866025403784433));
#1098=AXIS2_PLACEMENT_3D('',#1095,#1096,#1097);
#1099=PLANE('',#1098);
#1100=DIRECTION('',(0.,-1.,0.));
#1101=VECTOR('',#1100,1.);
#1102=CARTESIAN_POINT('',(-3.43515670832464,0.,-10.4498659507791));
#1103=LINE('',#1102,#1101);
#1104=CARTESIAN_POINT('',(-3.43515670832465,13.,-10.4498659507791));
#1105=VERTEX_POINT('',#1104);
#1106=EDGE_CURVE('E794',#1105,#131,#1103,.F.);
#1107=ORIENTED_EDGE('',*,*,#1106,.F.);
#1108=DIRECTION('',(0.50000000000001,0.,0.866025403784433));
#1109=VECTOR('',#1108,1.);
#1110=CARTESIAN_POINT('',(-12.4514428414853,13.,-26.0665316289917));
#1111=LINE('',#1110,#1109);
#1112=CARTESIAN_POINT('',(-1.36571123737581,13.,-6.8654812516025));
#1113=VERTEX_POINT('',#1112);
#1114=EDGE_CURVE('E320',#1105,#1113,#1111,.T.);
#1115=ORIENTED_EDGE('',*,*,#1114,.T.);
#1116=DIRECTION('',(0.,-1.,0.));
#1117=VECTOR('',#1116,1.);
#1118=CARTESIAN_POINT('',(-1.36571123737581,19.,-6.8654812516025));
#1119=LINE('',#1118,#1117);
#1120=CARTESIAN_POINT('',(-1.36571123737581,17.95,-6.8654812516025));
#1121=VERTEX_POINT('',#1120);
#1122=EDGE_CURVE('E342',#1113,#1121,#1119,.F.);
#1123=ORIENTED_EDGE('',*,*,#1122,.T.);
#1124=CARTESIAN_POINT('',(3.33105071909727,15.9666745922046,1.26954908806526));
#1125=CARTESIAN_POINT('',(3.29073882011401,15.93057980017,1.19972683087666));
#1126=CARTESIAN_POINT('',(3.25031150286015,15.8949915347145,1.12970466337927));
#1127=CARTESIAN_POINT('',(3.16917661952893,15.8250727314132,0.989174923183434));
#1128=CARTESIAN_POINT('',(3.12846899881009,15.7907424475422,0.91866725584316));
#1129=CARTESIAN_POINT('',(3.04655270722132,15.7234449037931,0.77678407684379));
#1130=CARTESIAN_POINT('',(3.00534259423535,15.6904846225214,0.705406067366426));
#1131=CARTESIAN_POINT('',(2.92256240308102,15.6264422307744,0.562026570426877));
#1132=CARTESIAN_POINT('',(2.8809923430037,15.5953600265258,0.490025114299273));
#1133=CARTESIAN_POINT('',(2.75587250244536,15.5056655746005,0.273311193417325));
#1134=CARTESIAN_POINT('',(2.67170171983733,15.4504275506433,0.127523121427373));
#1135=CARTESIAN_POINT('',(2.50149967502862,15.3535060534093,-0.167275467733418));
#1136=CARTESIAN_POINT('',(2.415471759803,15.3118000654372,-0.316280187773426));
#1137=CARTESIAN_POINT('',(2.26503784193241,15.2562252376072,-0.576839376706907));
#1138=CARTESIAN_POINT('',(2.2010544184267,15.2378830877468,-0.687661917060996));
#1139=CARTESIAN_POINT('',(2.07250368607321,15.2134011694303,-0.910318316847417));
#1140=CARTESIAN_POINT('',(2.00793657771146,15.2072573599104,-1.02215182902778));
#1141=CARTESIAN_POINT('',(1.87920357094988,15.2079405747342,-1.24512393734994));
#1142=CARTESIAN_POINT('',(1.81503756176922,15.2146909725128,-1.35626272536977));
#1143=CARTESIAN_POINT('',(1.68730609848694,15.2401679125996,-1.57750010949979));
#1144=CARTESIAN_POINT('',(1.62374083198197,15.2588980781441,-1.68759838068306));
#1145=CARTESIAN_POINT('',(1.49253882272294,15.3082717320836,-1.91484692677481));
#1146=CARTESIAN_POINT('',(1.42498254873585,15.3397474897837,-2.03185782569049));
#1147=CARTESIAN_POINT('',(1.29104908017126,15.4116189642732,-2.26383739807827));
#1148=CARTESIAN_POINT('',(1.22467272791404,15.4520207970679,-2.37880461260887));
#1149=CARTESIAN_POINT('',(1.09285152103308,15.5394740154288,-2.60712564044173));
#1150=CARTESIAN_POINT('',(1.02740951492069,15.5865423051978,-2.72047451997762));
#1151=CARTESIAN_POINT('',(0.897461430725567,15.6854526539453,-2.94555120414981));
#1152=CARTESIAN_POINT('',(0.832955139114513,15.7372936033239,-3.057279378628));
#1153=CARTESIAN_POINT('',(0.702687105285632,15.8461533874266,-3.28291023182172));
#1154=CARTESIAN_POINT('',(0.636948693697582,15.9032831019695,-3.3967725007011));
#1155=CARTESIAN_POINT('',(0.506089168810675,16.020301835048,-3.62342784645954));
#1156=CARTESIAN_POINT('',(0.440968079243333,16.0801909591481,-3.73622088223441));
#1157=CARTESIAN_POINT('',(0.31132605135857,16.2019389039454,-3.96076746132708));
#1158=CARTESIAN_POINT('',(0.246804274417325,16.2637941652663,-4.07252245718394));
#1159=CARTESIAN_POINT('',(0.118150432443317,16.3890924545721,-4.29535744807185));
#1160=CARTESIAN_POINT('',(0.0540183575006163,16.45253544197,-4.40643746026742));
#1161=CARTESIAN_POINT('',(-0.142838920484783,16.6496292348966,-4.74740426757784));
#1162=CARTESIAN_POINT('',(-0.275055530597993,16.7853095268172,-4.97641015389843));
#1163=CARTESIAN_POINT('',(-0.538633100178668,17.059961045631,-5.43293989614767));
#1164=CARTESIAN_POINT('',(-0.669994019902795,17.1989324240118,-5.66046368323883));
#1165=CARTESIAN_POINT('',(-0.932143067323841,17.4790933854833,-6.11451915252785));
#1166=CARTESIAN_POINT('',(-1.0629311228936,17.6202832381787,-6.34105070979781));
#1167=CARTESIAN_POINT('',(-1.32408994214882,17.904199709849,-6.79339105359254));
#1168=CARTESIAN_POINT('',(-1.45446070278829,18.0469263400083,-7.0191998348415));
#1169=CARTESIAN_POINT('',(-1.84539963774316,18.4770484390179,-7.69632593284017));
#1170=CARTESIAN_POINT('',(-2.10551587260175,18.7660856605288,-8.14686046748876));
#1171=CARTESIAN_POINT('',(-2.62504170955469,19.3465903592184,-9.04670561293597));
#1172=CARTESIAN_POINT('',(-2.88445136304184,19.6380576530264,-9.49601631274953));
#1173=CARTESIAN_POINT('',(-3.36763009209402,20.1828498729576,-10.3329064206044));
#1174=CARTESIAN_POINT('',(-3.59145450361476,20.4359785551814,-10.7205816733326));
#1175=CARTESIAN_POINT('',(-4.03887884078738,20.9430521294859,-11.4955433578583));
#1176=CARTESIAN_POINT('',(-4.26247876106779,21.1969970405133,-11.8828297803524));
#1177=CARTESIAN_POINT('',(-4.70921022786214,21.7051292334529,-12.6565913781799));
#1178=CARTESIAN_POINT('',(-4.93234199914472,21.9593157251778,-13.0430669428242));
#1179=CARTESIAN_POINT('',(-5.37847269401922,22.4681285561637,-13.8157879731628));
#1180=CARTESIAN_POINT('',(-5.60147162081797,22.7227548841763,-14.2020334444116));
#1181=CARTESIAN_POINT('',(-5.82442639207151,22.9775354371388,-14.5882024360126));
#1182=B_SPLINE_CURVE_WITH_KNOTS('',3,(#1124,#1125,#1126,#1127,#1128,#1129,#1130,#1131,#1132,
#1133,#1134,#1135,#1136,#1137,#1138,#1139,#1140,#1141,#1142,#1143,#1144,#1145,#1146,#1147,#1148,
#1149,#1150,#1151,#1152,#1153,#1154,#1155,#1156,#1157,#1158,#1159,#1160,#1161,#1162,#1163,#1164,
#1165,#1166,#1167,#1168,#1169,#1170,#1171,#1172,#1173,#1174,#1175,#1176,#1177,#1178,#1179,#1180,
#1181),.UNSPECIFIED.,.F.,.F.,(4,2,2,2,2,2,2,2,2,2,2,2,2,2,2,2,2,2,2,2,2,2,2,2,2,2,2,2,4),(0.,
0.265007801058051,0.530068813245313,0.796346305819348,1.0626104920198,1.59376454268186,
2.12403026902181,2.5113581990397,2.89855779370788,3.2834635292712,3.66848573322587,
4.08426984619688,4.50033973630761,4.91748420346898,5.33453193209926,5.76454742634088,
6.19457938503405,6.62387281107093,7.05315527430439,7.94474247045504,8.83637078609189,
9.72810830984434,10.619852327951,12.4052393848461,14.1904929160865,15.7332723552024,
17.2760878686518,18.8168202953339,20.3575138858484),.UNSPECIFIED.);
#1183=EDGE_CURVE('E960',#1121,#141,#1182,.T.);
#1184=ORIENTED_EDGE('',*,*,#1183,.T.);
#1185=ORIENTED_EDGE('',*,*,#142,.F.);
#1186=EDGE_LOOP('',(#1107,#1115,#1123,#1184,#1185));
#1187=FACE_BOUND('',#1186,.T.);
#1188=ADVANCED_FACE('F534',(#1187),#1099,.F.);
#1189=CARTESIAN_POINT('',(12.4514428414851,32.,26.0665316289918));
#1190=DIRECTION('',(-0.866025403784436,0.,0.500000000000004));
#1191=DIRECTION('',(0.500000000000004,0.,0.866025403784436));
#1192=AXIS2_PLACEMENT_3D('',#1189,#1190,#1191);
#1193=PLANE('',#1192);
#1194=DIRECTION('',(0.,-1.,0.));
#1195=VECTOR('',#1194,1.);
#1196=CARTESIAN_POINT('',(-7.33227102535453,0.,-8.1998659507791));
#1197=LINE('',#1196,#1195);
#1198=CARTESIAN_POINT('',(-7.33227102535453,13.,-8.1998659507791));
#1199=VERTEX_POINT('',#1198);
#1200=EDGE_CURVE('E791',#165,#1199,#1197,.T.);
#1201=ORIENTED_EDGE('',*,*,#1200,.F.);
#1202=ORIENTED_EDGE('',*,*,#184,.F.);
#1203=CARTESIAN_POINT('',(-11.3886292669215,24.8861365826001,-15.2256845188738));
#1204=CARTESIAN_POINT('',(-11.188322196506,24.6564687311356,-14.8787424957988));
#1205=CARTESIAN_POINT('',(-10.9879937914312,24.4268752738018,-14.5317635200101));
#1206=CARTESIAN_POINT('',(-10.5872830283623,23.9678764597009,-13.8377121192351));
#1207=CARTESIAN_POINT('',(-10.3869006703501,23.738471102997,-13.4906396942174));
#1208=CARTESIAN_POINT('',(-9.78564480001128,23.0505836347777,-12.4492339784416));
#1209=CARTESIAN_POINT('',(-9.38467362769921,22.5924428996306,-11.7547315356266));
#1210=CARTESIAN_POINT('',(-8.58120917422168,21.6763096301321,-10.363090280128));
#1211=CARTESIAN_POINT('',(-8.1787147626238,21.2183210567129,-9.66594950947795));
#1212=CARTESIAN_POINT('',(-7.57444263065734,20.5332279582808,-8.61931947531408));
#1213=CARTESIAN_POINT('',(-7.37293216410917,20.3051807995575,-8.27029310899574));
#1214=CARTESIAN_POINT('',(-6.96966364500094,19.849964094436,-7.57181154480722));
#1215=CARTESIAN_POINT('',(-6.76790559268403,19.6227945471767,-7.22235634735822));
#1216=CARTESIAN_POINT('',(-6.36433776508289,19.1700390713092,-6.52335636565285));
#1217=CARTESIAN_POINT('',(-6.16252850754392,18.9444512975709,-6.1738124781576));
#1218=CARTESIAN_POINT('',(-5.75838769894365,18.4951114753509,-5.47382006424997));
#1219=CARTESIAN_POINT('',(-5.55605612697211,18.2713595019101,-5.12337150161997));
#1220=CARTESIAN_POINT('',(-5.25210093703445,17.9381112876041,-4.59690566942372));
#1221=CARTESIAN_POINT('',(-5.15078139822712,17.8275061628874,-4.42141508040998));
#1222=CARTESIAN_POINT('',(-4.94788037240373,17.6072617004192,-4.06998019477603));
#1223=CARTESIAN_POINT('',(-4.84629888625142,17.4976223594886,-3.89403589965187));
#1224=CARTESIAN_POINT('',(-4.64280198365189,17.2796284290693,-3.54156892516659));
#1225=CARTESIAN_POINT('',(-4.54088659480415,17.1712737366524,-3.36504629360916));
#1226=CARTESIAN_POINT('',(-4.33659948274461,16.9563008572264,-3.01121063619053));
#1227=CARTESIAN_POINT('',(-4.23422776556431,16.8496826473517,-2.83389762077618));
#1228=CARTESIAN_POINT('',(-4.02993905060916,16.6399964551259,-2.48005918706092));
#1229=CARTESIAN_POINT('',(-3.92802862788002,16.5369029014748,-2.30354515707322));
#1230=CARTESIAN_POINT('',(-3.72332951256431,16.3341484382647,-1.94899588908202));
#1231=CARTESIAN_POINT('',(-3.62054067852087,16.2344880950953,-1.77096040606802));
#1232=CARTESIAN_POINT('',(-3.46519356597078,16.0887334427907,-1.50189131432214));
#1233=CARTESIAN_POINT('',(-3.41309843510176,16.0406670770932,-1.41165990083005));
#1234=CARTESIAN_POINT('',(-3.30852822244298,15.9462205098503,-1.23053897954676));
#1235=CARTESIAN_POINT('',(-3.2560531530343,15.8998402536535,-1.13964949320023));
#1236=CARTESIAN_POINT('',(-3.15065145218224,15.8092209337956,-0.957088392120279));
#1237=CARTESIAN_POINT('',(-3.09772490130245,15.7649814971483,-0.865416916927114));
#1238=CARTESIAN_POINT('',(-2.99132130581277,15.6792468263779,-0.681120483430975));
#1239=CARTESIAN_POINT('',(-2.93784430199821,15.6377513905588,-0.588495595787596));
#1240=CARTESIAN_POINT('',(-2.81759088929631,15.5489658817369,-0.380210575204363));
#1241=CARTESIAN_POINT('',(-2.75064075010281,15.5026037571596,-0.264249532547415));
#1242=CARTESIAN_POINT('',(-2.61553722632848,15.417318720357,-0.0302433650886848));
#1243=CARTESIAN_POINT('',(-2.54738374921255,15.3783963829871,0.0878019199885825));
#1244=CARTESIAN_POINT('',(-2.41061860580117,15.3110932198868,0.324686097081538));
#1245=CARTESIAN_POINT('',(-2.34202209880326,15.2825922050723,0.44349873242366));
#1246=CARTESIAN_POINT('',(-2.20378856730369,15.2384041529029,0.682926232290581));
#1247=CARTESIAN_POINT('',(-2.13415212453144,15.2227102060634,0.803540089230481));
#1248=CARTESIAN_POINT('',(-2.02904533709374,15.2102707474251,0.985590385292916));
#1249=CARTESIAN_POINT('',(-1.99372549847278,15.2079911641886,1.04676614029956));
#1250=CARTESIAN_POINT('',(-1.9230737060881,15.2072807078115,1.16913863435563));
#1251=CARTESIAN_POINT('',(-1.88774175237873,15.2088498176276,1.23033537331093));
#1252=CARTESIAN_POINT('',(-1.81717050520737,15.2157846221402,1.35256835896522));
#1253=CARTESIAN_POINT('',(-1.78193121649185,15.2211505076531,1.4136045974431));
#1254=CARTESIAN_POINT('',(-1.71163382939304,15.2354790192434,1.53536324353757));
#1255=CARTESIAN_POINT('',(-1.67657576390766,15.2444422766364,1.59608559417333));
#1256=CARTESIAN_POINT('',(-1.57021807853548,15.2767703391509,1.78030250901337));
#1257=CARTESIAN_POINT('',(-1.49930858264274,15.305399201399,1.90312135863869));
#1258=CARTESIAN_POINT('',(-1.39396069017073,15.356387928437,2.08558926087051));
#1259=CARTESIAN_POINT('',(-1.35900448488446,15.3747313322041,2.14613518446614));
#1260=CARTESIAN_POINT('',(-1.2894140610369,15.4137262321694,2.26666933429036));
#1261=CARTESIAN_POINT('',(-1.25477983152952,15.4343776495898,2.32665757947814));
#1262=CARTESIAN_POINT('',(-1.16651161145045,15.4897616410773,2.47954262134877));
#1263=CARTESIAN_POINT('',(-1.11309960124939,15.5259031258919,2.57205493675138));
#1264=CARTESIAN_POINT('',(-1.00693372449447,15.6018862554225,2.755939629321));
#1265=CARTESIAN_POINT('',(-0.954179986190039,15.6417286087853,2.84731178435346));
#1266=CARTESIAN_POINT('',(-0.849203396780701,15.7243034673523,3.02913657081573));
#1267=CARTESIAN_POINT('',(-0.796980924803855,15.7670378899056,3.11958854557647));
#1268=CARTESIAN_POINT('',(-0.693007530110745,15.8547492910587,3.29967574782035));
#1269=CARTESIAN_POINT('',(-0.641256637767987,15.8997264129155,3.38931092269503));
#1270=CARTESIAN_POINT('',(-0.486304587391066,16.0375318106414,3.65769574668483));
#1271=CARTESIAN_POINT('',(-0.383691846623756,16.1330012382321,3.8354262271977));
#1272=CARTESIAN_POINT('',(-0.179537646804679,16.3284159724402,4.1890316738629));
#1273=CARTESIAN_POINT('',(-0.0779962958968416,16.4283617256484,4.36490645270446));
#1274=CARTESIAN_POINT('',(0.0686653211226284,16.5754588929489,4.61893182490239));
#1275=CARTESIAN_POINT('',(0.114089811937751,16.6214021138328,4.69760935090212));
#1276=CARTESIAN_POINT('',(0.204802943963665,16.7138116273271,4.85472910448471));
#1277=CARTESIAN_POINT('',(0.250091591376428,16.7602778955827,4.93317134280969));
#1278=CARTESIAN_POINT('',(0.385797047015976,16.9003562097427,5.16822008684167));
#1279=CARTESIAN_POINT('',(0.476041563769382,16.9946358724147,5.32452817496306));
#1280=CARTESIAN_POINT('',(0.655565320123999,17.1838582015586,5.63547244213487));
#1281=CARTESIAN_POINT('',(0.744846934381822,17.2787918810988,5.79011273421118));
#1282=CARTESIAN_POINT('',(0.923126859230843,17.4696539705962,6.09890262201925));
#1283=CARTESIAN_POINT('',(1.01212521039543,17.5655822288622,6.25305228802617));
#1284=CARTESIAN_POINT('',(1.10102495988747,17.6618712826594,6.40703117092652));
#1285=B_SPLINE_CURVE_WITH_KNOTS('',3,(#1203,#1204,#1205,#1206,#1207,#1208,#1209,#1210,#1211,
#1212,#1213,#1214,#1215,#1216,#1217,#1218,#1219,#1220,#1221,#1222,#1223,#1224,#1225,#1226,#1227,
#1228,#1229,#1230,#1231,#1232,#1233,#1234,#1235,#1236,#1237,#1238,#1239,#1240,#1241,#1242,#1243,
#1244,#1245,#1246,#1247,#1248,#1249,#1250,#1251,#1252,#1253,#1254,#1255,#1256,#1257,#1258,#1259,
#1260,#1261,#1262,#1263,#1264,#1265,#1266,#1267,#1268,#1269,#1270,#1271,#1272,#1273,#1274,#1275,
#1276,#1277,#1278,#1279,#1280,#1281,#1282,#1283,#1284),.UNSPECIFIED.,.F.,.F.,(4,2,2,2,2,2,2,2,2,
2,2,2,2,2,2,2,2,2,2,2,2,2,2,2,2,2,2,2,2,2,2,2,2,2,2,2,2,2,2,2,4),(0.,1.38533430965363,
2.77066908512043,5.54141566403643,8.31987338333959,9.70907475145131,11.0982747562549,
12.4854203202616,13.8726223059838,14.565198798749,15.2577730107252,15.9502913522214,
16.6428005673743,17.328012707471,18.0133373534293,18.3575554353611,18.7017623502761,
19.0459090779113,19.3900304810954,19.8149727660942,20.2399478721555,20.6598544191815,
21.0795342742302,21.2914719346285,21.5034086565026,21.715356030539,21.9273406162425,
22.3607245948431,22.5775378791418,22.7943437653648,23.1325669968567,23.4708551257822,
23.8093697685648,24.1479060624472,24.8268402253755,25.5058422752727,25.8112567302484,
26.1166570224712,26.7275369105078,27.334225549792,27.9408229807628),.UNSPECIFIED.);
#1286=CARTESIAN_POINT('',(-5.26282555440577,17.95,-4.61548125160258));
#1287=VERTEX_POINT('',#1286);
#1288=EDGE_CURVE('E1001',#177,#1287,#1285,.T.);
#1289=ORIENTED_EDGE('',*,*,#1288,.T.);
#1290=DIRECTION('',(0.,-1.,0.));
#1291=VECTOR('',#1290,1.);
#1292=CARTESIAN_POINT('',(-5.26282555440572,19.,-4.61548125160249));
#1293=LINE('',#1292,#1291);
#1294=CARTESIAN_POINT('',(-5.26282555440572,13.,-4.61548125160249));
#1295=VERTEX_POINT('',#1294);
#1296=EDGE_CURVE('E377',#1287,#1295,#1293,.T.);
#1297=ORIENTED_EDGE('',*,*,#1296,.T.);
#1298=DIRECTION('',(-0.500000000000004,0.,-0.866025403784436));
#1299=VECTOR('',#1298,1.);
#1300=CARTESIAN_POINT('',(12.4514428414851,13.,26.0665316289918));
#1301=LINE('',#1300,#1299);
#1302=EDGE_CURVE('E336',#1295,#1199,#1301,.T.);
#1303=ORIENTED_EDGE('',*,*,#1302,.T.);
#1304=EDGE_LOOP('',(#1201,#1202,#1289,#1297,#1303));
#1305=FACE_BOUND('',#1304,.T.);
#1306=ADVANCED_FACE('F889',(#1305),#1193,.F.);
#1307=CARTESIAN_POINT('',(-12.451442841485,13.,26.0665316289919));
#1308=DIRECTION('',(0.,-1.,0.));
#1309=DIRECTION('',(0.,0.,-1.));
#1310=AXIS2_PLACEMENT_3D('',#1307,#1308,#1309);
#1311=PLANE('',#1310);
#1312=EDGE_CURVE('E296',#1199,#1105,#864,.T.);
#1313=ORIENTED_EDGE('',*,*,#1312,.F.);
#1314=ORIENTED_EDGE('',*,*,#1302,.F.);
#1315=CARTESIAN_POINT('',(0.,13.,0.));
#1316=DIRECTION('',(0.,-1.,0.));
#1317=DIRECTION('',(0.,0.,-1.));
#1318=AXIS2_PLACEMENT_3D('',#1315,#1316,#1317);
#1319=CIRCLE('',#1318,7.);
#1320=EDGE_CURVE('E852',#1295,#1113,#1319,.T.);
#1321=ORIENTED_EDGE('',*,*,#1320,.T.);
#1322=ORIENTED_EDGE('',*,*,#1114,.F.);
#1323=EDGE_LOOP('',(#1313,#1314,#1321,#1322));
#1324=FACE_BOUND('',#1323,.T.);
#1325=ADVANCED_FACE('F883',(#1324),#1311,.F.);
#1326=CARTESIAN_POINT('',(16.3485571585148,32.,-23.816531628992));
#1327=DIRECTION('',(0.866025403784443,0.,0.499999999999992));
#1328=DIRECTION('',(0.499999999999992,0.,-0.866025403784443));
#1329=AXIS2_PLACEMENT_3D('',#1326,#1327,#1328);
#1330=PLANE('',#1329);
#1331=DIRECTION('',(0.,-1.,0.));
#1332=VECTOR('',#1331,1.);
#1333=CARTESIAN_POINT('',(7.33227102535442,0.,-8.1998659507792));
#1334=LINE('',#1333,#1332);
#1335=CARTESIAN_POINT('',(7.33227102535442,13.,-8.1998659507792));
#1336=VERTEX_POINT('',#1335);
#1337=EDGE_CURVE('E289',#1336,#99,#1334,.F.);
#1338=ORIENTED_EDGE('',*,*,#1337,.F.);
#1339=DIRECTION('',(-0.499999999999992,0.,0.866025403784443));
#1340=VECTOR('',#1339,1.);
#1341=CARTESIAN_POINT('',(16.3485571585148,13.,-23.816531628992));
#1342=LINE('',#1341,#1340);
#1343=CARTESIAN_POINT('',(5.26282555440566,13.,-4.61548125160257));
#1344=VERTEX_POINT('',#1343);
#1345=EDGE_CURVE('E306',#1336,#1344,#1342,.T.);
#1346=ORIENTED_EDGE('',*,*,#1345,.T.);
#1347=DIRECTION('',(0.,-1.,0.));
#1348=VECTOR('',#1347,1.);
#1349=CARTESIAN_POINT('',(5.26282555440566,19.,-4.61548125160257));
#1350=LINE('',#1349,#1348);
#1351=CARTESIAN_POINT('',(5.26282555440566,17.95,-4.61548125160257));
#1352=VERTEX_POINT('',#1351);
#1353=EDGE_CURVE('E355',#1344,#1352,#1350,.F.);
#1354=ORIENTED_EDGE('',*,*,#1353,.T.);
#1355=CARTESIAN_POINT('',(1.03054626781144,15.585199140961,2.71504150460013));
#1356=CARTESIAN_POINT('',(1.06965629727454,15.5566602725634,2.64730094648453));
#1357=CARTESIAN_POINT('',(1.10894535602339,15.529060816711,2.57925030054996));
#1358=CARTESIAN_POINT('',(1.18793974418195,15.4761871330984,2.44242800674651));
#1359=CARTESIAN_POINT('',(1.22764532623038,15.450914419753,2.37365592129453));
#1360=CARTESIAN_POINT('',(1.3077272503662,15.4030311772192,2.23494995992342));
#1361=CARTESIAN_POINT('',(1.348106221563,15.3804380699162,2.16501153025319));
#1362=CARTESIAN_POINT('',(1.42929987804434,15.338668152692,2.02437999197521));
#1363=CARTESIAN_POINT('',(1.47011448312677,15.3194907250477,1.95368702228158));
#1364=CARTESIAN_POINT('',(1.55029265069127,15.2859412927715,1.81481436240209));
#1365=CARTESIAN_POINT('',(1.58963724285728,15.2713896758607,1.74666752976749));
#1366=CARTESIAN_POINT('',(1.66865514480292,15.2464702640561,1.60980450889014));
#1367=CARTESIAN_POINT('',(1.70832841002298,15.2361019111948,1.54108839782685));
#1368=CARTESIAN_POINT('',(1.78780661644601,15.2200053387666,1.4034281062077));
#1369=CARTESIAN_POINT('',(1.82761093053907,15.2142649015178,1.3344850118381));
#1370=CARTESIAN_POINT('',(1.90732044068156,15.2076482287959,1.19642409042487));
#1371=CARTESIAN_POINT('',(1.94722563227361,15.2067717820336,1.12730627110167));
#1372=CARTESIAN_POINT('',(2.02448777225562,15.2098266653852,0.993484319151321));
#1373=CARTESIAN_POINT('',(2.06184773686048,15.2134602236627,0.928774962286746));
#1374=CARTESIAN_POINT('',(2.13641072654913,15.2248794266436,0.799628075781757));
#1375=CARTESIAN_POINT('',(2.1736137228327,15.2326658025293,0.735190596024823));
#1376=CARTESIAN_POINT('',(2.28492006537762,15.2618407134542,0.542402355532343));
#1377=CARTESIAN_POINT('',(2.35865445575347,15.2890415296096,0.41469064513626));
#1378=CARTESIAN_POINT('',(2.46853417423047,15.3390931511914,0.224373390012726));
#1379=CARTESIAN_POINT('',(2.50523009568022,15.3574392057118,0.160814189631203));
#1380=CARTESIAN_POINT('',(2.57826915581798,15.3967778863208,0.0343068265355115));
#1381=CARTESIAN_POINT('',(2.61461229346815,15.4177705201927,-0.0286413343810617));
#1382=CARTESIAN_POINT('',(2.6869401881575,15.4619926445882,-0.153916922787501));
#1383=CARTESIAN_POINT('',(2.72292505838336,15.4852214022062,-0.216244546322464));
#1384=CARTESIAN_POINT('',(2.79457259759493,15.5335706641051,-0.340341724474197));
#1385=CARTESIAN_POINT('',(2.83023527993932,15.5586910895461,-0.402111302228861));
#1386=CARTESIAN_POINT('',(2.9366055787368,15.6362972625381,-0.586350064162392));
#1387=CARTESIAN_POINT('',(3.00688211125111,15.691145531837,-0.70807258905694));
#1388=CARTESIAN_POINT('',(3.14652331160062,15.805325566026,-0.949938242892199));
#1389=CARTESIAN_POINT('',(3.21588777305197,15.8646583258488,-1.07008101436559));
#1390=CARTESIAN_POINT('',(3.35394240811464,15.9866102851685,-1.30919865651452));
#1391=CARTESIAN_POINT('',(3.42263210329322,16.0492316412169,-1.42817269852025));
#1392=CARTESIAN_POINT('',(3.5594526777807,16.1768769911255,-1.66515288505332));
#1393=CARTESIAN_POINT('',(3.6275835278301,16.2419011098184,-1.78315897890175));
#1394=CARTESIAN_POINT('',(3.76354338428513,16.3738927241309,-2.01864835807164));
#1395=CARTESIAN_POINT('',(3.83137149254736,16.440863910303,-2.1361300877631));
#1396=CARTESIAN_POINT('',(3.96667810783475,16.5762061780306,-2.37048802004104));
#1397=CARTESIAN_POINT('',(4.0341566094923,16.6445772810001,-2.48736421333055));
#1398=CARTESIAN_POINT('',(4.23611939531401,16.851256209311,-2.83717401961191));
#1399=CARTESIAN_POINT('',(4.37018832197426,16.9911860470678,-3.0693882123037));
#1400=CARTESIAN_POINT('',(4.63808878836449,17.274319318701,-3.53340543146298));
#1401=CARTESIAN_POINT('',(4.7719176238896,17.4175329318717,-3.76520377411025));
#1402=CARTESIAN_POINT('',(5.03907883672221,17.7058621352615,-4.22794056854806));
#1403=CARTESIAN_POINT('',(5.17241116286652,17.8509779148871,-4.45887893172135));
#1404=CARTESIAN_POINT('',(5.43854143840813,18.1423541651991,-4.91983009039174));
#1405=CARTESIAN_POINT('',(5.57133985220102,18.2886129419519,-5.14984369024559));
#1406=CARTESIAN_POINT('',(5.83666793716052,18.5821028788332,-5.60940541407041));
#1407=CARTESIAN_POINT('',(5.96919760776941,18.729334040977,-5.83895353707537));
#1408=CARTESIAN_POINT('',(6.2890166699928,19.0857806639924,-6.39289640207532));
#1409=CARTESIAN_POINT('',(6.47620446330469,19.2953605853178,-6.71711517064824));
#1410=CARTESIAN_POINT('',(6.85029740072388,19.7155344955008,-7.36506314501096));
#1411=CARTESIAN_POINT('',(7.03720254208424,19.9261284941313,-7.68879234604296));
#1412=CARTESIAN_POINT('',(7.59778389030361,20.5591852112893,-8.65974772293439));
#1413=CARTESIAN_POINT('',(7.97115434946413,20.9827305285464,-9.30644432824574));
#1414=CARTESIAN_POINT('',(8.71336446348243,21.8268176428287,-10.5919899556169));
#1415=CARTESIAN_POINT('',(9.08220913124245,22.2473418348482,-11.2308476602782));
#1416=CARTESIAN_POINT('',(9.63517089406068,22.8787890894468,-12.1886055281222));
#1417=CARTESIAN_POINT('',(9.81939671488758,23.0893313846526,-12.5076940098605));
#1418=CARTESIAN_POINT('',(10.1877882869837,23.5106250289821,-13.1457669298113));
#1419=CARTESIAN_POINT('',(10.3719540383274,23.7213763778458,-13.4647513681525));
#1420=CARTESIAN_POINT('',(10.5560961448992,23.9322102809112,-13.7836948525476));
#1421=B_SPLINE_CURVE_WITH_KNOTS('',3,(#1355,#1356,#1357,#1358,#1359,#1360,#1361,#1362,#1363,
#1364,#1365,#1366,#1367,#1368,#1369,#1370,#1371,#1372,#1373,#1374,#1375,#1376,#1377,#1378,#1379,
#1380,#1381,#1382,#1383,#1384,#1385,#1386,#1387,#1388,#1389,#1390,#1391,#1392,#1393,#1394,#1395,
#1396,#1397,#1398,#1399,#1400,#1401,#1402,#1403,#1404,#1405,#1406,#1407,#1408,#1409,#1410,#1411,
#1412,#1413,#1414,#1415,#1416,#1417,#1418,#1419,#1420),.UNSPECIFIED.,.F.,.F.,(4,2,2,2,2,2,2,2,2,
2,2,2,2,2,2,2,2,2,2,2,2,2,2,2,2,2,2,2,2,2,2,2,4),(0.,0.249806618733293,0.499774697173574,
0.751287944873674,1.00275566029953,1.24272666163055,1.48266564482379,1.72196909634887,
1.96126215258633,2.18556326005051,2.40990387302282,2.85898103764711,3.08590177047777,
3.31282317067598,3.53967044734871,3.7665082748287,4.21901087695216,4.67161416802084,
5.12451806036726,5.57744551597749,6.03129604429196,6.48515352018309,7.39248502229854,
8.30316661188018,9.21393958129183,10.1235521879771,11.0331666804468,12.320303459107,
13.6074526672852,16.1829313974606,18.7303283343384,20.0034197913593,21.2765096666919),.UNSPECIFIED.);
#1422=EDGE_CURVE('E961',#1352,#109,#1421,.T.);
#1423=ORIENTED_EDGE('',*,*,#1422,.T.);
#1424=ORIENTED_EDGE('',*,*,#110,.F.);
#1425=EDGE_LOOP('',(#1338,#1346,#1354,#1423,#1424));
#1426=FACE_BOUND('',#1425,.T.);
#1427=ADVANCED_FACE('F890',(#1426),#1330,.F.);
#1428=CARTESIAN_POINT('',(12.4514428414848,32.,-26.0665316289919));
#1429=DIRECTION('',(-0.866025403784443,0.,-0.499999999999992));
#1430=DIRECTION('',(-0.499999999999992,0.,0.866025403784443));
#1431=AXIS2_PLACEMENT_3D('',#1428,#1429,#1430);
#1432=PLANE('',#1431);
#1433=DIRECTION('',(0.,-1.,0.));
#1434=VECTOR('',#1433,1.);
#1435=CARTESIAN_POINT('',(3.43515670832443,0.,-10.4498659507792));
#1436=LINE('',#1435,#1434);
#1437=CARTESIAN_POINT('',(3.43515670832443,13.,-10.4498659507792));
#1438=VERTEX_POINT('',#1437);
#1439=EDGE_CURVE('E280',#133,#1438,#1436,.T.);
#1440=ORIENTED_EDGE('',*,*,#1439,.F.);
#1441=ORIENTED_EDGE('',*,*,#152,.F.);
#1442=CARTESIAN_POINT('',(5.91440178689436,23.0803707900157,-14.7440443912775));
#1443=CARTESIAN_POINT('',(5.746663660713,22.8886380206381,-14.453513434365));
#1444=CARTESIAN_POINT('',(5.57889991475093,22.6969948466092,-14.1629381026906));
#1445=CARTESIAN_POINT('',(5.24330763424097,22.3139350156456,-13.5816752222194));
#1446=CARTESIAN_POINT('',(5.0754790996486,22.1225183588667,-13.2909876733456));
#1447=CARTESIAN_POINT('',(4.571859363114,21.5486602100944,-12.4186927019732));
#1448=CARTESIAN_POINT('',(4.23595098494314,21.1666299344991,-11.8368823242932));
#1449=CARTESIAN_POINT('',(3.56380511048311,20.4044609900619,-10.6726915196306));
#1450=CARTESIAN_POINT('',(3.22756784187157,20.024321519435,-10.0903114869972));
#1451=CARTESIAN_POINT('',(2.72258387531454,19.4563720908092,-9.21565359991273));
#1452=CARTESIAN_POINT('',(2.55415409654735,19.2674354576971,-8.92392466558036));
#1453=CARTESIAN_POINT('',(2.2170020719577,18.8906093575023,-8.33996022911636));
#1454=CARTESIAN_POINT('',(2.04827982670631,18.702719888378,-8.04772472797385));
#1455=CARTESIAN_POINT('',(1.70981257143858,18.3277499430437,-7.46148224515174));
#1456=CARTESIAN_POINT('',(1.54006606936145,18.1406748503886,-7.16747267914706));
#1457=CARTESIAN_POINT('',(1.19995390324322,17.7687264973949,-6.57838112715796));
#1458=CARTESIAN_POINT('',(1.02958819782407,17.5838533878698,-6.28329906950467));
#1459=CARTESIAN_POINT('',(0.773261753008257,17.3091221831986,-5.83932864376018));
#1460=CARTESIAN_POINT('',(0.687656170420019,17.2179395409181,-5.69105542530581));
#1461=CARTESIAN_POINT('',(0.516139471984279,17.0367320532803,-5.39397978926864));
#1462=CARTESIAN_POINT('',(0.430228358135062,16.9467072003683,-5.24517737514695));
#1463=CARTESIAN_POINT('',(0.258020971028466,16.7681919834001,-4.94690543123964));
#1464=CARTESIAN_POINT('',(0.171724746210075,16.6797014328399,-4.7974359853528));
#1465=CARTESIAN_POINT('',(-0.00138795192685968,16.5047850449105,-4.49759599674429));
#1466=CARTESIAN_POINT('',(-0.0882044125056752,16.4183591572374,-4.34722547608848));
#1467=CARTESIAN_POINT('',(-0.263843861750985,16.2471034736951,-4.04300902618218));
#1468=CARTESIAN_POINT('',(-0.352677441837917,16.1623168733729,-3.88914475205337));
#1469=CARTESIAN_POINT('',(-0.531357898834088,15.9969976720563,-3.57966112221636));
#1470=CARTESIAN_POINT('',(-0.621205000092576,15.9164660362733,-3.42404137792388));
#1471=CARTESIAN_POINT('',(-0.80233777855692,15.7617278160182,-3.11031020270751));
#1472=CARTESIAN_POINT('',(-0.89362423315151,15.6875247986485,-2.95219742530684));
#1473=CARTESIAN_POINT('',(-1.03195229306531,15.5836905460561,-2.7126061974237));
#1474=CARTESIAN_POINT('',(-1.07829072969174,15.5503266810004,-2.63234567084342));
#1475=CARTESIAN_POINT('',(-1.17150113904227,15.4867428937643,-2.47090050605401));
#1476=CARTESIAN_POINT('',(-1.21837305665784,15.4565226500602,-2.38971596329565));
#1477=CARTESIAN_POINT('',(-1.32791743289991,15.3908773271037,-2.19997953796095));
#1478=CARTESIAN_POINT('',(-1.39081370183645,15.3569137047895,-2.09104000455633));
#1479=CARTESIAN_POINT('',(-1.51766354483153,15.2979993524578,-1.87132963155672));
#1480=CARTESIAN_POINT('',(-1.58161687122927,15.273046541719,-1.76055922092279));
#1481=CARTESIAN_POINT('',(-1.70996246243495,15.2345694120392,-1.53825813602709));
#1482=CARTESIAN_POINT('',(-1.77434880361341,15.2209686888,-1.42673772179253));
#1483=CARTESIAN_POINT('',(-1.90347554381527,15.2065139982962,-1.20308364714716));
#1484=CARTESIAN_POINT('',(-1.96821584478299,15.2056566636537,-1.09095015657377));
#1485=CARTESIAN_POINT('',(-2.0973607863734,15.2167877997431,-0.867264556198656));
#1486=CARTESIAN_POINT('',(-2.16176563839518,15.2287668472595,-0.755712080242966));
#1487=CARTESIAN_POINT('',(-2.28979031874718,15.2641234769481,-0.533966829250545));
#1488=CARTESIAN_POINT('',(-2.35340977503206,15.2875062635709,-0.423774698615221));
#1489=CARTESIAN_POINT('',(-2.4802640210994,15.3437548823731,-0.204056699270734));
#1490=CARTESIAN_POINT('',(-2.54348779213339,15.3767175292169,-0.0945499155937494));
#1491=CARTESIAN_POINT('',(-2.66887194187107,15.4497796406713,0.122621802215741));
#1492=CARTESIAN_POINT('',(-2.73103238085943,15.4898786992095,0.230286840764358));
#1493=CARTESIAN_POINT('',(-2.84674559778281,15.5700747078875,0.430708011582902));
#1494=CARTESIAN_POINT('',(-2.90040736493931,15.6095515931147,0.523652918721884));
#1495=CARTESIAN_POINT('',(-3.00712084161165,15.6916540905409,0.708486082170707));
#1496=CARTESIAN_POINT('',(-3.06017256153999,15.7342796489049,0.800374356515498));
#1497=CARTESIAN_POINT('',(-3.16475616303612,15.821126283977,0.981518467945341));
#1498=CARTESIAN_POINT('',(-3.21629769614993,15.8653011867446,1.07079102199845));
#1499=CARTESIAN_POINT('',(-3.31895637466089,15.9555068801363,1.24860106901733));
#1500=CARTESIAN_POINT('',(-3.37007363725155,16.0015371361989,1.33713876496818));
#1501=CARTESIAN_POINT('',(-3.42102611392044,16.0482645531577,1.42539104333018));
#1502=B_SPLINE_CURVE_WITH_KNOTS('',3,(#1442,#1443,#1444,#1445,#1446,#1447,#1448,#1449,#1450,
#1451,#1452,#1453,#1454,#1455,#1456,#1457,#1458,#1459,#1460,#1461,#1462,#1463,#1464,#1465,#1466,
#1467,#1468,#1469,#1470,#1471,#1472,#1473,#1474,#1475,#1476,#1477,#1478,#1479,#1480,#1481,#1482,
#1483,#1484,#1485,#1486,#1487,#1488,#1489,#1490,#1491,#1492,#1493,#1494,#1495,#1496,#1497,#1498,
#1499,#1500,#1501),.UNSPECIFIED.,.F.,.F.,(4,2,2,2,2,2,2,2,2,2,2,2,2,2,2,2,2,2,2,2,2,2,2,2,2,2,2,
2,2,4),(0.,1.15920317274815,2.31840714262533,4.63693228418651,6.9543720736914,8.11305231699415,
9.27173030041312,10.4345988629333,11.5975466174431,12.1794779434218,12.7614054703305,
13.3432617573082,13.92510385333,14.5156469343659,15.1063234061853,15.6973306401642,
15.9927842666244,16.2882076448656,16.6788413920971,17.0693848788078,17.457278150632,
17.8450689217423,18.2325752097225,18.6202585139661,19.0120047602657,19.4037287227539,
19.7467308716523,20.089727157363,20.4261563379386,20.7624892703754),.UNSPECIFIED.);
#1503=CARTESIAN_POINT('',(1.36571123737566,17.95,-6.86548125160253));
#1504=VERTEX_POINT('',#1503);
#1505=EDGE_CURVE('E619',#145,#1504,#1502,.T.);
#1506=ORIENTED_EDGE('',*,*,#1505,.T.);
#1507=DIRECTION('',(0.,-1.,0.));
#1508=VECTOR('',#1507,1.);
#1509=CARTESIAN_POINT('',(1.36571123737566,19.,-6.86548125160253));
#1510=LINE('',#1509,#1508);
#1511=CARTESIAN_POINT('',(1.36571123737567,13.,-6.86548125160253));
#1512=VERTEX_POINT('',#1511);
#1513=EDGE_CURVE('E311',#1504,#1512,#1510,.T.);
#1514=ORIENTED_EDGE('',*,*,#1513,.T.);
#1515=DIRECTION('',(-0.499999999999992,0.,0.866025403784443));
#1516=VECTOR('',#1515,1.);
#1517=CARTESIAN_POINT('',(12.4514428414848,13.,-26.0665316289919));
#1518=LINE('',#1517,#1516);
#1519=EDGE_CURVE('E307',#1438,#1512,#1518,.T.);
#1520=ORIENTED_EDGE('',*,*,#1519,.F.);
#1521=EDGE_LOOP('',(#1440,#1441,#1506,#1514,#1520));
#1522=FACE_BOUND('',#1521,.T.);
#1523=ADVANCED_FACE('F315',(#1522),#1432,.F.);
#1524=EDGE_CURVE('E292',#1438,#1336,#864,.T.);
#1525=ORIENTED_EDGE('',*,*,#1524,.F.);
#1526=ORIENTED_EDGE('',*,*,#1519,.T.);
#1527=EDGE_CURVE('E936',#1512,#1344,#1319,.T.);
#1528=ORIENTED_EDGE('',*,*,#1527,.T.);
#1529=ORIENTED_EDGE('',*,*,#1345,.F.);
#1530=EDGE_LOOP('',(#1525,#1526,#1528,#1529));
#1531=FACE_BOUND('',#1530,.T.);
#1532=ADVANCED_FACE('F301',(#1531),#1311,.F.);
#1533=CARTESIAN_POINT('',(28.8,32.,2.2499999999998));
#1534=DIRECTION('',(0.,0.,1.));
#1535=DIRECTION('',(1.,0.,0.));
#1536=AXIS2_PLACEMENT_3D('',#1533,#1534,#1535);
#1537=PLANE('',#1536);
#1538=DIRECTION('',(0.,-1.,0.));
#1539=VECTOR('',#1538,1.);
#1540=CARTESIAN_POINT('',(10.767427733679,0.,2.24999999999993));
#1541=LINE('',#1540,#1539);
#1542=CARTESIAN_POINT('',(10.767427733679,13.,2.24999999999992));
#1543=VERTEX_POINT('',#1542);
#1544=EDGE_CURVE('E601',#1543,#195,#1541,.F.);
#1545=ORIENTED_EDGE('',*,*,#1544,.F.);
#1546=DIRECTION('',(-1.,0.,0.));
#1547=VECTOR('',#1546,1.);
#1548=CARTESIAN_POINT('',(28.8,13.,2.2499999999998));
#1549=LINE('',#1548,#1547);
#1550=CARTESIAN_POINT('',(6.62853679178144,13.,2.24999999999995));
#1551=VERTEX_POINT('',#1550);
#1552=EDGE_CURVE('E329',#1543,#1551,#1549,.T.);
#1553=ORIENTED_EDGE('',*,*,#1552,.T.);
#1554=DIRECTION('',(0.,-1.,0.));
#1555=VECTOR('',#1554,1.);
#1556=CARTESIAN_POINT('',(6.62853679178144,19.,2.24999999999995));
#1557=LINE('',#1556,#1555);
#1558=CARTESIAN_POINT('',(6.62853679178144,17.95,2.24999999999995));
#1559=VERTEX_POINT('',#1558);
#1560=EDGE_CURVE('E364',#1551,#1559,#1557,.F.);
#1561=ORIENTED_EDGE('',*,*,#1560,.T.);
#1562=CARTESIAN_POINT('',(3.26198979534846,16.1964203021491,2.24999999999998));
#1563=CARTESIAN_POINT('',(3.34388579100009,16.2353459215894,2.24999999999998));
#1564=CARTESIAN_POINT('',(3.42560068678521,16.2746498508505,2.24999999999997));
#1565=CARTESIAN_POINT('',(3.58871135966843,16.353910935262,2.24999999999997));
#1566=CARTESIAN_POINT('',(3.67010714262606,16.3938680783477,2.24999999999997));
#1567=CARTESIAN_POINT('',(3.91387335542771,16.5145606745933,2.24999999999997));
#1568=CARTESIAN_POINT('',(4.07583433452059,16.59612288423,2.24999999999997));
#1569=CARTESIAN_POINT('',(4.39889503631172,16.7608601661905,2.24999999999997));
#1570=CARTESIAN_POINT('',(4.55999490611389,16.8440349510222,2.24999999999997));
#1571=CARTESIAN_POINT('',(4.88155104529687,17.0116259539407,2.24999999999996));
#1572=CARTESIAN_POINT('',(5.04200730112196,17.096042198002,2.24999999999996));
#1573=CARTESIAN_POINT('',(5.52254780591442,17.3506757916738,2.24999999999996));
#1574=CARTESIAN_POINT('',(5.84187748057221,17.5223159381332,2.24999999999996));
#1575=CARTESIAN_POINT('',(6.47925812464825,17.8679870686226,2.24999999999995));
#1576=CARTESIAN_POINT('',(6.79730902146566,18.0420181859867,2.24999999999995));
#1577=CARTESIAN_POINT('',(7.40682951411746,18.377548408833,2.24999999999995));
#1578=CARTESIAN_POINT('',(7.69836803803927,18.5389224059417,2.24999999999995));
#1579=CARTESIAN_POINT('',(8.28089704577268,18.8626562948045,2.24999999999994));
#1580=CARTESIAN_POINT('',(8.57188752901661,19.0250161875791,2.24999999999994));
#1581=CARTESIAN_POINT('',(9.44424004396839,19.5131733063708,2.24999999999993));
#1582=CARTESIAN_POINT('',(10.0249951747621,19.8400546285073,2.24999999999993));
#1583=CARTESIAN_POINT('',(11.1857225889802,20.4956217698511,2.24999999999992));
#1584=CARTESIAN_POINT('',(11.7656945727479,20.8243081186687,2.24999999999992));
#1585=CARTESIAN_POINT('',(12.6351800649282,21.3181726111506,2.24999999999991));
#1586=CARTESIAN_POINT('',(12.9249305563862,21.4829336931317,2.24999999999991));
#1587=CARTESIAN_POINT('',(13.5042994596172,21.8126874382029,2.2499999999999));
#1588=CARTESIAN_POINT('',(13.7939178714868,21.9776801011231,2.2499999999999));
#1589=CARTESIAN_POINT('',(14.0834834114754,22.1427654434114,2.2499999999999));
#1590=B_SPLINE_CURVE_WITH_KNOTS('',3,(#1562,#1563,#1564,#1565,#1566,#1567,#1568,#1569,#1570,
#1571,#1572,#1573,#1574,#1575,#1576,#1577,#1578,#1579,#1580,#1581,#1582,#1583,#1584,#1585,#1586,
#1587,#1588,#1589),.UNSPECIFIED.,.F.,.F.,(4,2,2,2,2,2,2,2,2,2,2,2,2,4),(0.,0.272025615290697,
0.544046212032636,1.08804854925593,1.63195477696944,2.17587240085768,3.26345902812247,
4.35110655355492,5.35076704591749,6.35042857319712,8.34971037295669,10.349613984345,
11.3495709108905,12.349527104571),.UNSPECIFIED.);
#1591=EDGE_CURVE('E615',#1559,#205,#1590,.T.);
#1592=ORIENTED_EDGE('',*,*,#1591,.T.);
#1593=ORIENTED_EDGE('',*,*,#206,.F.);
#1594=EDGE_LOOP('',(#1545,#1553,#1561,#1592,#1593));
#1595=FACE_BOUND('',#1594,.T.);
#1596=ADVANCED_FACE('F609',(#1595),#1537,.F.);
#1597=CARTESIAN_POINT('',(28.8,32.,-2.2500000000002));
#1598=DIRECTION('',(0.,0.,-1.));
#1599=DIRECTION('',(-1.,0.,0.));
#1600=AXIS2_PLACEMENT_3D('',#1597,#1598,#1599);
#1601=PLANE('',#1600);
#1602=DIRECTION('',(0.,-1.,0.));
#1603=VECTOR('',#1602,1.);
#1604=CARTESIAN_POINT('',(10.767427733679,0.,-2.25000000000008));
#1605=LINE('',#1604,#1603);
#1606=CARTESIAN_POINT('',(10.767427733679,13.,-2.25000000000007));
#1607=VERTEX_POINT('',#1606);
#1608=EDGE_CURVE('E808',#101,#1607,#1605,.T.);
#1609=ORIENTED_EDGE('',*,*,#1608,.F.);
#1610=ORIENTED_EDGE('',*,*,#120,.F.);
#1611=CARTESIAN_POINT('',(14.0834834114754,22.1427654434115,-2.2500000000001));
#1612=CARTESIAN_POINT('',(13.7939178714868,21.9776801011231,-2.25000000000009));
#1613=CARTESIAN_POINT('',(13.5042994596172,21.8126874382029,-2.25000000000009));
#1614=CARTESIAN_POINT('',(12.9249305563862,21.4829336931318,-2.25000000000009));
#1615=CARTESIAN_POINT('',(12.6351800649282,21.3181726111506,-2.25000000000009));
#1616=CARTESIAN_POINT('',(11.7656945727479,20.8243081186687,-2.25000000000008));
#1617=CARTESIAN_POINT('',(11.1857225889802,20.4956217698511,-2.25000000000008));
#1618=CARTESIAN_POINT('',(10.0249951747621,19.8400546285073,-2.25000000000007));
#1619=CARTESIAN_POINT('',(9.44424004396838,19.5131733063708,-2.25000000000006));
#1620=CARTESIAN_POINT('',(8.57188752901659,19.0250161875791,-2.25000000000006));
#1621=CARTESIAN_POINT('',(8.28089704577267,18.8626562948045,-2.25000000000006));
#1622=CARTESIAN_POINT('',(7.69836803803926,18.5389224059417,-2.25000000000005));
#1623=CARTESIAN_POINT('',(7.40682951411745,18.377548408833,-2.25000000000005));
#1624=CARTESIAN_POINT('',(6.79730902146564,18.0420181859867,-2.25000000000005));
#1625=CARTESIAN_POINT('',(6.47925812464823,17.8679870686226,-2.25000000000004));
#1626=CARTESIAN_POINT('',(5.8418774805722,17.5223159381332,-2.25000000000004));
#1627=CARTESIAN_POINT('',(5.5225478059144,17.3506757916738,-2.25000000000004));
#1628=CARTESIAN_POINT('',(5.04200730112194,17.096042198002,-2.25000000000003));
#1629=CARTESIAN_POINT('',(4.88155104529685,17.0116259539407,-2.25000000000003));
#1630=CARTESIAN_POINT('',(4.55999490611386,16.8440349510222,-2.25000000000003));
#1631=CARTESIAN_POINT('',(4.3988950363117,16.7608601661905,-2.25000000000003));
#1632=CARTESIAN_POINT('',(4.07583433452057,16.59612288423,-2.25000000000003));
#1633=CARTESIAN_POINT('',(3.91387335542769,16.5145606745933,-2.25000000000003));
#1634=CARTESIAN_POINT('',(3.67010714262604,16.3938680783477,-2.25000000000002));
#1635=CARTESIAN_POINT('',(3.5887113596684,16.353910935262,-2.25000000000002));
#1636=CARTESIAN_POINT('',(3.42560068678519,16.2746498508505,-2.25000000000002));
#1637=CARTESIAN_POINT('',(3.34388579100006,16.2353459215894,-2.25000000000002));
#1638=CARTESIAN_POINT('',(3.26198979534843,16.1964203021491,-2.25000000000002));
#1639=B_SPLINE_CURVE_WITH_KNOTS('',3,(#1611,#1612,#1613,#1614,#1615,#1616,#1617,#1618,#1619,
#1620,#1621,#1622,#1623,#1624,#1625,#1626,#1627,#1628,#1629,#1630,#1631,#1632,#1633,#1634,#1635,
#1636,#1637,#1638),.UNSPECIFIED.,.F.,.F.,(4,2,2,2,2,2,2,2,2,2,2,2,2,4),(0.,0.999956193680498,
1.99991312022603,3.9998167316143,5.99909853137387,6.99876005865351,7.99842055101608,
9.08606807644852,10.1736547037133,10.7175723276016,11.2614785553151,11.8054808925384,
12.0775014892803,12.349527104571),.UNSPECIFIED.);
#1640=CARTESIAN_POINT('',(6.62853679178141,17.95,-2.25000000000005));
#1641=VERTEX_POINT('',#1640);
#1642=EDGE_CURVE('E617',#113,#1641,#1639,.T.);
#1643=ORIENTED_EDGE('',*,*,#1642,.T.);
#1644=DIRECTION('',(0.,-1.,0.));
#1645=VECTOR('',#1644,1.);
#1646=CARTESIAN_POINT('',(6.62853679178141,19.,-2.25000000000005));
#1647=LINE('',#1646,#1645);
#1648=CARTESIAN_POINT('',(6.62853679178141,13.,-2.25000000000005));
#1649=VERTEX_POINT('',#1648);
#1650=EDGE_CURVE('E368',#1641,#1649,#1647,.T.);
#1651=ORIENTED_EDGE('',*,*,#1650,.T.);
#1652=DIRECTION('',(-1.,0.,0.));
#1653=VECTOR('',#1652,1.);
#1654=CARTESIAN_POINT('',(28.8,13.,-2.2500000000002));
#1655=LINE('',#1654,#1653);
#1656=EDGE_CURVE('E325',#1607,#1649,#1655,.T.);
#1657=ORIENTED_EDGE('',*,*,#1656,.F.);
#1658=EDGE_LOOP('',(#1609,#1610,#1643,#1651,#1657));
#1659=FACE_BOUND('',#1658,.T.);
#1660=ADVANCED_FACE('F914',(#1659),#1601,.F.);
#1661=EDGE_CURVE('E924',#1607,#1543,#864,.T.);
#1662=ORIENTED_EDGE('',*,*,#1661,.F.);
#1663=ORIENTED_EDGE('',*,*,#1656,.T.);
#1664=EDGE_CURVE('E938',#1649,#1551,#1319,.T.);
#1665=ORIENTED_EDGE('',*,*,#1664,.T.);
#1666=ORIENTED_EDGE('',*,*,#1552,.F.);
#1667=EDGE_LOOP('',(#1662,#1663,#1665,#1666));
#1668=FACE_BOUND('',#1667,.T.);
#1669=ADVANCED_FACE('F899',(#1668),#1311,.F.);
#1670=DIRECTION('',(0.,-1.,0.));
#1671=VECTOR('',#1670,1.);
#1672=CARTESIAN_POINT('',(3.43515670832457,0.,10.4498659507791));
#1673=LINE('',#1672,#1671);
#1674=CARTESIAN_POINT('',(3.43515670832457,13.,10.4498659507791));
#1675=VERTEX_POINT('',#1674);
#1676=EDGE_CURVE('E823',#1675,#30,#1673,.F.);
#1677=ORIENTED_EDGE('',*,*,#1676,.F.);
#1678=CARTESIAN_POINT('',(1.36571123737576,13.,6.86548125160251));
#1679=VERTEX_POINT('',#1678);
#1680=EDGE_CURVE('E335',#1675,#1679,#1301,.T.);
#1681=ORIENTED_EDGE('',*,*,#1680,.T.);
#1682=DIRECTION('',(0.,-1.,0.));
#1683=VECTOR('',#1682,1.);
#1684=CARTESIAN_POINT('',(1.36571123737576,19.,6.86548125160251));
#1685=LINE('',#1684,#1683);
#1686=CARTESIAN_POINT('',(1.36571123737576,17.95,6.86548125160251));
#1687=VERTEX_POINT('',#1686);
#1688=EDGE_CURVE('E391',#1679,#1687,#1685,.F.);
#1689=ORIENTED_EDGE('',*,*,#1688,.T.);
#1690=CARTESIAN_POINT('',(-3.42102611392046,16.0482645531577,-1.42539104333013));
#1691=CARTESIAN_POINT('',(-3.38059593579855,16.011176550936,-1.35536392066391));
#1692=CARTESIAN_POINT('',(-3.34006094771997,15.974538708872,-1.28515526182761));
#1693=CARTESIAN_POINT('',(-3.258736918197,15.9023759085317,-1.1442979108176));
#1694=CARTESIAN_POINT('',(-3.21794783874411,15.8668511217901,-1.07364915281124));
#1695=CARTESIAN_POINT('',(-3.13592786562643,15.7970059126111,-0.931586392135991));
#1696=CARTESIAN_POINT('',(-3.09469588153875,15.7626905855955,-0.860170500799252));
#1697=CARTESIAN_POINT('',(-3.01190107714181,15.6957082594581,-0.716765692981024));
#1698=CARTESIAN_POINT('',(-2.97033826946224,15.6630411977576,-0.644776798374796));
#1699=CARTESIAN_POINT('',(-2.84354349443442,15.5668552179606,-0.425161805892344));
#1700=CARTESIAN_POINT('',(-2.75770610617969,15.5064583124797,-0.276487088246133));
#1701=CARTESIAN_POINT('',(-2.58412848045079,15.3981863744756,0.0241581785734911));
#1702=CARTESIAN_POINT('',(-2.4963909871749,15.3502944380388,0.17612397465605));
#1703=CARTESIAN_POINT('',(-2.34514178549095,15.2843240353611,0.43809527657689));
#1704=CARTESIAN_POINT('',(-2.28214506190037,15.2616169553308,0.547208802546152));
#1705=CARTESIAN_POINT('',(-2.15538966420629,15.2274458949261,0.766755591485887));
#1706=CARTESIAN_POINT('',(-2.09163128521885,15.2159776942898,0.877188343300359));
#1707=CARTESIAN_POINT('',(-1.96459137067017,15.2056824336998,1.09722792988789));
#1708=CARTESIAN_POINT('',(-1.90131286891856,15.2067104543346,1.2068295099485));
#1709=CARTESIAN_POINT('',(-1.77509997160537,15.2209308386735,1.42543666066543));
#1710=CARTESIAN_POINT('',(-1.71216563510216,15.2341252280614,1.53444212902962));
#1711=CARTESIAN_POINT('',(-1.59256710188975,15.2695773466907,1.74159286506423));
#1712=CARTESIAN_POINT('',(-1.53583446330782,15.2909449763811,1.83985667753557));
#1713=CARTESIAN_POINT('',(-1.42317095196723,15.3410043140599,2.03499560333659));
#1714=CARTESIAN_POINT('',(-1.36724046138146,15.3696993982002,2.13187005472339));
#1715=CARTESIAN_POINT('',(-1.25609685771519,15.4329191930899,2.32437642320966));
#1716=CARTESIAN_POINT('',(-1.20088547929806,15.4674559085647,2.42000533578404));
#1717=CARTESIAN_POINT('',(-1.09122639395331,15.540989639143,2.60994044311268));
#1718=CARTESIAN_POINT('',(-1.03677859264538,15.5799860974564,2.70424680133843));
#1719=CARTESIAN_POINT('',(-0.92744900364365,15.6622233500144,2.89361120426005));
#1720=CARTESIAN_POINT('',(-0.872580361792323,15.7055335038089,2.98864647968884));
#1721=CARTESIAN_POINT('',(-0.763406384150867,15.7948941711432,3.17774135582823));
#1722=CARTESIAN_POINT('',(-0.709101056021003,15.8409447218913,3.27180094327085));
#1723=CARTESIAN_POINT('',(-0.601024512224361,15.9351094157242,3.45899500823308));
#1724=CARTESIAN_POINT('',(-0.547252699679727,15.9832208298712,3.55213051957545));
#1725=CARTESIAN_POINT('',(-0.44009264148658,16.0811106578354,3.73773718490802));
#1726=CARTESIAN_POINT('',(-0.386704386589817,16.1308890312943,3.83020835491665));
#1727=CARTESIAN_POINT('',(-0.215396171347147,16.2931876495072,4.1269228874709));
#1728=CARTESIAN_POINT('',(-0.0980850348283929,16.4082750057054,4.33011173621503));
#1729=CARTESIAN_POINT('',(0.135533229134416,16.6424665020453,4.73475043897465));
#1730=CARTESIAN_POINT('',(0.251840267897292,16.7615709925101,4.93620013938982));
#1731=CARTESIAN_POINT('',(0.48378361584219,17.0024867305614,5.33793780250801));
#1732=CARTESIAN_POINT('',(0.599419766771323,17.1242985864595,5.53822549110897));
#1733=CARTESIAN_POINT('',(0.830198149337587,17.369780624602,5.9379453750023));
#1734=CARTESIAN_POINT('',(0.94534037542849,17.4934508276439,6.13737756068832));
#1735=CARTESIAN_POINT('',(1.17537082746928,17.7422458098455,6.53580199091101));
#1736=CARTESIAN_POINT('',(1.29025871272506,17.8673718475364,6.73479364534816));
#1737=CARTESIAN_POINT('',(1.51976232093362,18.1186218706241,7.13230555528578));
#1738=CARTESIAN_POINT('',(1.63437804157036,18.2447458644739,7.33082580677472));
#1739=CARTESIAN_POINT('',(1.97788141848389,18.6242041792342,7.92579110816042));
#1740=CARTESIAN_POINT('',(2.2064588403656,18.8786613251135,8.32169881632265));
#1741=CARTESIAN_POINT('',(2.66091036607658,19.3869544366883,9.10883194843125));
#1742=CARTESIAN_POINT('',(2.88678936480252,19.6407729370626,9.50006585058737));
#1743=CARTESIAN_POINT('',(3.33821757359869,20.1496179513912,10.2819624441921));
#1744=CARTESIAN_POINT('',(3.5637667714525,20.4046445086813,10.6726251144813));
#1745=CARTESIAN_POINT('',(4.01455001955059,20.9154399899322,11.4534046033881));
#1746=CARTESIAN_POINT('',(4.23978415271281,21.1712086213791,11.8435215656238));
#1747=CARTESIAN_POINT('',(4.69007935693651,21.6833457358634,12.6234557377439));
#1748=CARTESIAN_POINT('',(4.9151404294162,21.9397142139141,13.0132729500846));
#1749=CARTESIAN_POINT('',(5.20460906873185,22.2698328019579,13.5146473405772));
#1750=CARTESIAN_POINT('',(5.26907547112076,22.343376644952,13.6263064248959));
#1751=CARTESIAN_POINT('',(5.39800089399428,22.4905015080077,13.8496118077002));
#1752=CARTESIAN_POINT('',(5.46245991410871,22.5640825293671,13.9612581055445));
#1753=CARTESIAN_POINT('',(5.59150553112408,22.711432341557,14.1847716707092));
#1754=CARTESIAN_POINT('',(5.65609210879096,22.7852011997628,14.2966389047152));
#1755=CARTESIAN_POINT('',(5.78525435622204,22.932765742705,14.5203544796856));
#1756=CARTESIAN_POINT('',(5.84983002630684,23.0065614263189,14.6322028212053));
#1757=CARTESIAN_POINT('',(5.9144017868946,23.0803707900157,14.7440443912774));
#1758=B_SPLINE_CURVE_WITH_KNOTS('',3,(#1690,#1691,#1692,#1693,#1694,#1695,#1696,#1697,#1698,
#1699,#1700,#1701,#1702,#1703,#1704,#1705,#1706,#1707,#1708,#1709,#1710,#1711,#1712,#1713,#1714,
#1715,#1716,#1717,#1718,#1719,#1720,#1721,#1722,#1723,#1724,#1725,#1726,#1727,#1728,#1729,#1730,
#1731,#1732,#1733,#1734,#1735,#1736,#1737,#1738,#1739,#1740,#1741,#1742,#1743,#1744,#1745,#1746,
#1747,#1748,#1749,#1750,#1751,#1752,#1753,#1754,#1755,#1756,#1757),.UNSPECIFIED.,.F.,.F.,(4,2,2,
2,2,2,2,2,2,2,2,2,2,2,2,2,2,2,2,2,2,2,2,2,2,2,2,2,2,2,2,2,2,4),(0.,0.266883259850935,
0.533807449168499,0.801747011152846,1.06967639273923,1.61534861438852,2.16027934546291,
2.54393793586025,2.92745240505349,3.30652351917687,3.68565775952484,4.03174990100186,
4.37800179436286,4.72497408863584,5.07190311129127,5.42577994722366,5.77966158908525,
6.1330883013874,6.48650646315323,7.27041860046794,8.05439927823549,8.83855792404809,
9.62272535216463,10.4076302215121,11.1925417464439,12.7621356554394,14.3166696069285,
15.8712597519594,17.4253033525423,18.9793340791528,19.4246331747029,19.8699490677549,
20.3162090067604,20.7624520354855),.UNSPECIFIED.);
#1759=EDGE_CURVE('E858',#1687,#40,#1758,.T.);
#1760=ORIENTED_EDGE('',*,*,#1759,.T.);
#1761=ORIENTED_EDGE('',*,*,#41,.F.);
#1762=EDGE_LOOP('',(#1677,#1681,#1689,#1760,#1761));
#1763=FACE_BOUND('',#1762,.T.);
#1764=ADVANCED_FACE('F896',(#1763),#1193,.F.);
#1765=CARTESIAN_POINT('',(16.3485571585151,32.,23.8165316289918));
#1766=DIRECTION('',(0.866025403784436,0.,-0.500000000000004));
#1767=DIRECTION('',(-0.500000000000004,0.,-0.866025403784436));
#1768=AXIS2_PLACEMENT_3D('',#1765,#1766,#1767);
#1769=PLANE('',#1768);
#1770=DIRECTION('',(0.,-1.,0.));
#1771=VECTOR('',#1770,1.);
#1772=CARTESIAN_POINT('',(7.33227102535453,0.,8.1998659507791));
#1773=LINE('',#1772,#1771);
#1774=CARTESIAN_POINT('',(7.33227102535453,13.,8.1998659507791));
#1775=VERTEX_POINT('',#1774);
#1776=EDGE_CURVE('E603',#197,#1775,#1773,.T.);
#1777=ORIENTED_EDGE('',*,*,#1776,.F.);
#1778=ORIENTED_EDGE('',*,*,#216,.F.);
#1779=CARTESIAN_POINT('',(10.5560961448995,23.9322102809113,13.7836948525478));
#1780=CARTESIAN_POINT('',(10.3729618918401,23.7225302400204,13.4664970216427));
#1781=CARTESIAN_POINT('',(10.189804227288,23.5129319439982,13.1492586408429));
#1782=CARTESIAN_POINT('',(9.82342969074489,23.093942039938,12.5146793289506));
#1783=CARTESIAN_POINT('',(9.64021281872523,22.884550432,12.1973383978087));
#1784=CARTESIAN_POINT('',(9.09044124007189,22.256734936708,11.2451060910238));
#1785=CARTESIAN_POINT('',(8.72377940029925,21.8386862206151,10.6100291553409));
#1786=CARTESIAN_POINT('',(7.98970714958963,21.0038061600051,9.33857872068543));
#1787=CARTESIAN_POINT('',(7.62229637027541,20.58697610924,8.70220458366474));
#1788=CARTESIAN_POINT('',(7.07060233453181,19.9637992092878,7.74664248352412));
#1789=CARTESIAN_POINT('',(6.88661043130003,19.7564209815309,7.42795915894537));
#1790=CARTESIAN_POINT('',(6.51835720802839,19.3426239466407,6.79012586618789));
#1791=CARTESIAN_POINT('',(6.33409588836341,19.136205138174,6.47097589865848));
#1792=CARTESIAN_POINT('',(5.96501756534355,18.7245351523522,5.83171349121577));
#1793=CARTESIAN_POINT('',(5.78020020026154,18.5192852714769,5.51160042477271));
#1794=CARTESIAN_POINT('',(5.40999605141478,18.1107971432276,4.87038802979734));
#1795=CARTESIAN_POINT('',(5.22460923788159,17.9075590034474,4.54928864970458));
#1796=CARTESIAN_POINT('',(4.94588541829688,17.6051425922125,4.06652483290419));
#1797=CARTESIAN_POINT('',(4.85287752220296,17.5047516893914,3.90543043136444));
#1798=CARTESIAN_POINT('',(4.66657816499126,17.3050285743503,3.58275047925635));
#1799=CARTESIAN_POINT('',(4.57328670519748,17.2056963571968,3.42116493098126));
#1800=CARTESIAN_POINT('',(4.3863443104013,17.0084382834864,3.09737120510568));
#1801=CARTESIAN_POINT('',(4.29269341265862,16.9105122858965,2.93516309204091));
#1802=CARTESIAN_POINT('',(4.10490262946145,16.7165564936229,2.60989991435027));
#1803=CARTESIAN_POINT('',(4.01076275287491,16.6205266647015,2.44684486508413));
#1804=CARTESIAN_POINT('',(3.82160291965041,16.430905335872,2.11921042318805));
#1805=CARTESIAN_POINT('',(3.72658145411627,16.3373198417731,1.95462841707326));
#1806=CARTESIAN_POINT('',(3.53558771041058,16.1539742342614,1.62381754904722));
#1807=CARTESIAN_POINT('',(3.43961524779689,16.0642148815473,1.4575883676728));
#1808=CARTESIAN_POINT('',(3.29456763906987,15.9338730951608,1.20635853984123));
#1809=CARTESIAN_POINT('',(3.24598544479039,15.8910994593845,1.122211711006));
#1810=CARTESIAN_POINT('',(3.14842500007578,15.8074033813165,0.953232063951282));
#1811=CARTESIAN_POINT('',(3.09944676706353,15.7664808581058,0.868399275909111));
#1812=CARTESIAN_POINT('',(3.00102762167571,15.6869680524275,0.697932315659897));
#1813=CARTESIAN_POINT('',(2.95158680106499,15.6483773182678,0.612298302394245));
#1814=CARTESIAN_POINT('',(2.85215613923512,15.5741523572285,0.440079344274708));
#1815=CARTESIAN_POINT('',(2.80216634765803,15.538517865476,0.353494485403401));
#1816=CARTESIAN_POINT('',(2.68791870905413,15.4618535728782,0.155611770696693));
#1817=CARTESIAN_POINT('',(2.62346392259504,15.4219769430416,0.0439728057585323));
#1818=CARTESIAN_POINT('',(2.49340652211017,15.3504094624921,-0.181293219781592));
#1819=CARTESIAN_POINT('',(2.42780395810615,15.3187182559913,-0.294920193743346));
#1820=CARTESIAN_POINT('',(2.29596307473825,15.2662542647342,-0.523275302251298));
#1821=CARTESIAN_POINT('',(2.22973248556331,15.2454061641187,-0.637990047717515));
#1822=CARTESIAN_POINT('',(2.09658064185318,15.2166126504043,-0.868615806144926));
#1823=CARTESIAN_POINT('',(2.02965976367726,15.2086605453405,-0.984526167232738));
#1824=CARTESIAN_POINT('',(1.89519574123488,15.206709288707,-1.21742468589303));
#1825=CARTESIAN_POINT('',(1.82765213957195,15.2128292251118,-1.33441363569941));
#1826=CARTESIAN_POINT('',(1.69318897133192,15.2384225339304,-1.56731067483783));
#1827=CARTESIAN_POINT('',(1.62626977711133,15.2579034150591,-1.68321811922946));
#1828=CARTESIAN_POINT('',(1.49315005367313,15.3080855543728,-1.91378824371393));
#1829=CARTESIAN_POINT('',(1.42695542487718,15.338847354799,-2.02844070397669));
#1830=CARTESIAN_POINT('',(1.2957473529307,15.4089467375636,-2.25569975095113));
#1831=CARTESIAN_POINT('',(1.23073371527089,15.4482828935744,-2.3683066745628));
#1832=CARTESIAN_POINT('',(1.14346443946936,15.505817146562,-2.51946149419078));
#1833=CARTESIAN_POINT('',(1.12073843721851,15.5212403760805,-2.55882408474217));
#1834=CARTESIAN_POINT('',(1.07550504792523,15.5527381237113,-2.63717061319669));
#1835=CARTESIAN_POINT('',(1.05299714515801,15.56880967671,-2.67615544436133));
#1836=CARTESIAN_POINT('',(1.03054626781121,15.5851991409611,-2.71504150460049));
#1837=B_SPLINE_CURVE_WITH_KNOTS('',3,(#1779,#1780,#1781,#1782,#1783,#1784,#1785,#1786,#1787,
#1788,#1789,#1790,#1791,#1792,#1793,#1794,#1795,#1796,#1797,#1798,#1799,#1800,#1801,#1802,#1803,
#1804,#1805,#1806,#1807,#1808,#1809,#1810,#1811,#1812,#1813,#1814,#1815,#1816,#1817,#1818,#1819,
#1820,#1821,#1822,#1823,#1824,#1825,#1826,#1827,#1828,#1829,#1830,#1831,#1832,#1833,#1834,#1835,
#1836),.UNSPECIFIED.,.F.,.F.,(4,2,2,2,2,2,2,2,2,2,2,2,2,2,2,2,2,2,2,2,2,2,2,2,2,2,2,2,4),(0.,
1.26612206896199,2.53224474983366,5.0645857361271,7.59902238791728,8.86620743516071,
10.1333907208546,11.4017785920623,12.6702339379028,13.3043622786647,13.9384876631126,
14.5725489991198,15.2065988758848,15.8420827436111,16.4776923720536,16.7961656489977,
17.1146249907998,17.4330224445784,17.751391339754,18.1559985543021,18.5605881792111,
18.9623286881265,19.3638606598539,19.7688031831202,20.1739734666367,20.5813508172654,
20.9886604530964,21.1326499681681,21.2760425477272),.UNSPECIFIED.);
#1838=CARTESIAN_POINT('',(5.26282555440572,17.95,4.61548125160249));
#1839=VERTEX_POINT('',#1838);
#1840=EDGE_CURVE('E622',#209,#1839,#1837,.T.);
#1841=ORIENTED_EDGE('',*,*,#1840,.T.);
#1842=DIRECTION('',(0.,-1.,0.));
#1843=VECTOR('',#1842,1.);
#1844=CARTESIAN_POINT('',(5.26282555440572,19.,4.61548125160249));
#1845=LINE('',#1844,#1843);
#1846=CARTESIAN_POINT('',(5.26282555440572,13.,4.61548125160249));
#1847=VERTEX_POINT('',#1846);
#1848=EDGE_CURVE('E381',#1839,#1847,#1845,.T.);
#1849=ORIENTED_EDGE('',*,*,#1848,.T.);
#1850=DIRECTION('',(-0.500000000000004,0.,-0.866025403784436));
#1851=VECTOR('',#1850,1.);
#1852=CARTESIAN_POINT('',(16.3485571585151,13.,23.8165316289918));
#1853=LINE('',#1852,#1851);
#1854=EDGE_CURVE('E333',#1775,#1847,#1853,.T.);
#1855=ORIENTED_EDGE('',*,*,#1854,.F.);
#1856=EDGE_LOOP('',(#1777,#1778,#1841,#1849,#1855));
#1857=FACE_BOUND('',#1856,.T.);
#1858=ADVANCED_FACE('F884',(#1857),#1769,.F.);
#1859=EDGE_CURVE('E1116',#1775,#1675,#864,.T.);
#1860=ORIENTED_EDGE('',*,*,#1859,.F.);
#1861=ORIENTED_EDGE('',*,*,#1854,.T.);
#1862=EDGE_CURVE('E847',#1847,#1679,#1319,.T.);
#1863=ORIENTED_EDGE('',*,*,#1862,.T.);
#1864=ORIENTED_EDGE('',*,*,#1680,.F.);
#1865=EDGE_LOOP('',(#1860,#1861,#1863,#1864));
#1866=FACE_BOUND('',#1865,.T.);
#1867=ADVANCED_FACE('F897',(#1866),#1311,.F.);
#1868=CARTESIAN_POINT('',(-3.4351567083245,13.,10.4498659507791));
#1869=VERTEX_POINT('',#1868);
#1870=CARTESIAN_POINT('',(-7.33227102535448,13.,8.19986595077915));
#1871=VERTEX_POINT('',#1870);
#1872=EDGE_CURVE('E70',#1869,#1871,#864,.T.);
#1873=ORIENTED_EDGE('',*,*,#1872,.F.);
#1874=DIRECTION('',(0.499999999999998,0.,-0.86602540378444));
#1875=VECTOR('',#1874,1.);
#1876=CARTESIAN_POINT('',(-12.451442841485,13.,26.0665316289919));
#1877=LINE('',#1876,#1875);
#1878=CARTESIAN_POINT('',(-1.36571123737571,13.,6.86548125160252));
#1879=VERTEX_POINT('',#1878);
#1880=EDGE_CURVE('E340',#1869,#1879,#1877,.T.);
#1881=ORIENTED_EDGE('',*,*,#1880,.T.);
#1882=CARTESIAN_POINT('',(-5.26282555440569,13.,4.61548125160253));
#1883=VERTEX_POINT('',#1882);
#1884=EDGE_CURVE('E55',#1879,#1883,#1319,.T.);
#1885=ORIENTED_EDGE('',*,*,#1884,.T.);
#1886=DIRECTION('',(0.499999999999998,0.,-0.86602540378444));
#1887=VECTOR('',#1886,1.);
#1888=CARTESIAN_POINT('',(-16.3485571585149,13.,23.8165316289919));
#1889=LINE('',#1888,#1887);
#1890=EDGE_CURVE('E341',#1871,#1883,#1889,.T.);
#1891=ORIENTED_EDGE('',*,*,#1890,.F.);
#1892=EDGE_LOOP('',(#1873,#1881,#1885,#1891));
#1893=FACE_BOUND('',#1892,.T.);
#1894=ADVANCED_FACE('F844',(#1893),#1311,.F.);
#1895=CARTESIAN_POINT('',(-12.451442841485,32.,26.0665316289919));
#1896=DIRECTION('',(0.86602540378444,0.,0.499999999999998));
#1897=DIRECTION('',(0.499999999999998,0.,-0.86602540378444));
#1898=AXIS2_PLACEMENT_3D('',#1895,#1896,#1897);
#1899=PLANE('',#1898);
#1900=DIRECTION('',(0.,-1.,0.));
#1901=VECTOR('',#1900,1.);
#1902=CARTESIAN_POINT('',(-3.4351567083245,0.,10.4498659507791));
#1903=LINE('',#1902,#1901);
#1904=EDGE_CURVE('E689',#32,#1869,#1903,.T.);
#1905=ORIENTED_EDGE('',*,*,#1904,.F.);
#1906=ORIENTED_EDGE('',*,*,#56,.F.);
#1907=CARTESIAN_POINT('',(-5.82442639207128,22.9775354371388,14.5882024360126));
#1908=CARTESIAN_POINT('',(-5.65854217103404,22.7879660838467,14.3008825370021));
#1909=CARTESIAN_POINT('',(-5.49263203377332,22.5984873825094,14.0135177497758));
#1910=CARTESIAN_POINT('',(-5.1607462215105,22.2197591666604,13.4386746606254));
#1911=CARTESIAN_POINT('',(-4.99477054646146,22.0305096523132,13.1511963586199));
#1912=CARTESIAN_POINT('',(-4.49670758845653,21.4631572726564,12.2885260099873));
#1913=CARTESIAN_POINT('',(-4.1645017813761,21.0854704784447,11.7131286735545));
#1914=CARTESIAN_POINT('',(-3.49982856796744,20.3320915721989,10.5618808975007));
#1915=CARTESIAN_POINT('',(-3.16736150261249,19.9563982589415,9.98603104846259));
#1916=CARTESIAN_POINT('',(-2.66802623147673,19.3951435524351,9.12115698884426));
#1917=CARTESIAN_POINT('',(-2.50147831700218,19.2084428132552,8.83268753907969));
#1918=CARTESIAN_POINT('',(-2.16808699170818,18.8361001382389,8.25523682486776));
#1919=CARTESIAN_POINT('',(-2.00124358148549,18.6504582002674,7.966255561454));
#1920=CARTESIAN_POINT('',(-1.66647304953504,18.2799372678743,7.38641599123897));
#1921=CARTESIAN_POINT('',(-1.49854426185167,18.0950642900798,7.09555479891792));
#1922=CARTESIAN_POINT('',(-1.16206097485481,17.727545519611,6.51274864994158));
#1923=CARTESIAN_POINT('',(-0.993506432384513,17.5448998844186,6.22080361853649));
#1924=CARTESIAN_POINT('',(-0.739876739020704,17.2735258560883,5.78150410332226));
#1925=CARTESIAN_POINT('',(-0.655160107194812,17.1834580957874,5.63477059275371));
#1926=CARTESIAN_POINT('',(-0.485418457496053,17.0044936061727,5.3407694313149));
#1927=CARTESIAN_POINT('',(-0.400393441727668,16.9155968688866,5.19350178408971));
#1928=CARTESIAN_POINT('',(-0.229955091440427,16.739355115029,4.89829390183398));
#1929=CARTESIAN_POINT('',(-0.144541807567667,16.6520099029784,4.75035375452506));
#1930=CARTESIAN_POINT('',(0.0268091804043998,16.4794061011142,4.45356513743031));
#1931=CARTESIAN_POINT('',(0.112746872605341,16.3941474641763,4.30471668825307));
#1932=CARTESIAN_POINT('',(0.28678651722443,16.2251109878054,4.00327118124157));
#1933=CARTESIAN_POINT('',(0.374900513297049,16.1413824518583,3.85065326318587));
#1934=CARTESIAN_POINT('',(0.55215027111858,15.9782366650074,3.5436476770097));
#1935=CARTESIAN_POINT('',(0.641286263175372,15.8988204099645,3.38925960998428));
#1936=CARTESIAN_POINT('',(0.820977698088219,15.7464165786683,3.07802491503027));
#1937=CARTESIAN_POINT('',(0.911533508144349,15.6734306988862,2.92117765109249));
#1938=CARTESIAN_POINT('',(1.04875480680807,15.5715003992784,2.68350338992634));
#1939=CARTESIAN_POINT('',(1.09471770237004,15.5387871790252,2.60389331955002));
#1940=CARTESIAN_POINT('',(1.1871927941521,15.476513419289,2.44372176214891));
#1941=CARTESIAN_POINT('',(1.23370515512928,15.4469538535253,2.36315998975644));
#1942=CARTESIAN_POINT('',(1.34273833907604,15.3826707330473,2.17430897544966));
#1943=CARTESIAN_POINT('',(1.40548617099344,15.3494529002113,2.06562654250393));
#1944=CARTESIAN_POINT('',(1.53200170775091,15.2921510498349,1.84649520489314));
#1945=CARTESIAN_POINT('',(1.59576876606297,15.2680614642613,1.73604742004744));
#1946=CARTESIAN_POINT('',(1.72374753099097,15.2313519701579,1.51438169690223));
#1947=CARTESIAN_POINT('',(1.78795402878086,15.2186618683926,1.40317278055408));
#1948=CARTESIAN_POINT('',(1.91667748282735,15.20600018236,1.1802172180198));
#1949=CARTESIAN_POINT('',(1.98119436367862,15.2060256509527,1.06847070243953));
#1950=CARTESIAN_POINT('',(2.10982144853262,15.2187765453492,0.845682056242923));
#1951=CARTESIAN_POINT('',(2.1739320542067,15.2314863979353,0.734639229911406));
#1952=CARTESIAN_POINT('',(2.30135143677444,15.2680911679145,0.513942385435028));
#1953=CARTESIAN_POINT('',(2.36465984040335,15.2919911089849,0.404289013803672));
#1954=CARTESIAN_POINT('',(2.49082727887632,15.3490451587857,0.185760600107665));
#1955=CARTESIAN_POINT('',(2.55367642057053,15.3822845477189,0.0769026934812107));
#1956=CARTESIAN_POINT('',(2.67832595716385,15.4557223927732,-0.138996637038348));
#1957=CARTESIAN_POINT('',(2.74012643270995,15.4959203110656,-0.246038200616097));
#1958=CARTESIAN_POINT('',(2.84678353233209,15.5703283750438,-0.430773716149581));
#1959=CARTESIAN_POINT('',(2.89184905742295,15.6033595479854,-0.508829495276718));
#1960=CARTESIAN_POINT('',(2.98154013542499,15.6717057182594,-0.664178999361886));
#1961=CARTESIAN_POINT('',(3.02616572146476,15.7070205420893,-0.741472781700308));
#1962=CARTESIAN_POINT('',(3.11434482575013,15.7789222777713,-0.894203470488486));
#1963=CARTESIAN_POINT('',(3.15790419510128,15.815480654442,-0.969650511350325));
#1964=CARTESIAN_POINT('',(3.24470318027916,15.8900592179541,-1.11999076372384));
#1965=CARTESIAN_POINT('',(3.28794283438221,15.9280792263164,-1.19488404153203));
#1966=CARTESIAN_POINT('',(3.33105071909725,15.9666745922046,-1.2695490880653));
#1967=B_SPLINE_CURVE_WITH_KNOTS('',3,(#1907,#1908,#1909,#1910,#1911,#1912,#1913,#1914,#1915,
#1916,#1917,#1918,#1919,#1920,#1921,#1922,#1923,#1924,#1925,#1926,#1927,#1928,#1929,#1930,#1931,
#1932,#1933,#1934,#1935,#1936,#1937,#1938,#1939,#1940,#1941,#1942,#1943,#1944,#1945,#1946,#1947,
#1948,#1949,#1950,#1951,#1952,#1953,#1954,#1955,#1956,#1957,#1958,#1959,#1960,#1961,#1962,#1963,
#1964,#1965,#1966),.UNSPECIFIED.,.F.,.F.,(4,2,2,2,2,2,2,2,2,2,2,2,2,2,2,2,2,2,2,2,2,2,2,2,2,2,2,
2,2,4),(0.,1.14632526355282,2.29265134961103,4.58542384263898,6.87660698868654,8.02215799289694,
9.16770668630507,10.3178348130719,11.4680437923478,12.0436952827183,12.6193428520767,
13.1949173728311,13.7704788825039,14.3557577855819,14.941171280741,15.5267387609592,
15.8194121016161,16.112175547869,16.5013629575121,16.8903125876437,17.2768504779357,
17.6632987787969,18.0492732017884,18.4354210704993,18.8252163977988,19.2149816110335,
19.5029282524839,19.7908530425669,20.0742745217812,20.3576615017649),.UNSPECIFIED.);
#1968=CARTESIAN_POINT('',(-1.36571123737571,17.95,6.86548125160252));
#1969=VERTEX_POINT('',#1968);
#1970=EDGE_CURVE('E853',#49,#1969,#1967,.T.);
#1971=ORIENTED_EDGE('',*,*,#1970,.T.);
#1972=DIRECTION('',(0.,-1.,0.));
#1973=VECTOR('',#1972,1.);
#1974=CARTESIAN_POINT('',(-1.36571123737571,19.,6.86548125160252));
#1975=LINE('',#1974,#1973);
#1976=EDGE_CURVE('E404',#1969,#1879,#1975,.T.);
#1977=ORIENTED_EDGE('',*,*,#1976,.T.);
#1978=ORIENTED_EDGE('',*,*,#1880,.F.);
#1979=EDGE_LOOP('',(#1905,#1906,#1971,#1977,#1978));
#1980=FACE_BOUND('',#1979,.T.);
#1981=ADVANCED_FACE('F673',(#1980),#1899,.F.);
#1982=CARTESIAN_POINT('',(-16.3485571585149,32.,23.8165316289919));
#1983=DIRECTION('',(-0.86602540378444,0.,-0.499999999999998));
#1984=DIRECTION('',(-0.499999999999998,0.,0.86602540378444));
#1985=AXIS2_PLACEMENT_3D('',#1982,#1983,#1984);
#1986=PLANE('',#1985);
#1987=DIRECTION('',(0.,-1.,0.));
#1988=VECTOR('',#1987,1.);
#1989=CARTESIAN_POINT('',(-7.33227102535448,0.,8.19986595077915));
#1990=LINE('',#1989,#1988);
#1991=EDGE_CURVE('E11',#1871,#67,#1990,.F.);
#1992=ORIENTED_EDGE('',*,*,#1991,.F.);
#1993=ORIENTED_EDGE('',*,*,#1890,.T.);
#1994=DIRECTION('',(0.,-1.,0.));
#1995=VECTOR('',#1994,1.);
#1996=CARTESIAN_POINT('',(-5.26282555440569,19.,4.61548125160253));
#1997=LINE('',#1996,#1995);
#1998=CARTESIAN_POINT('',(-5.26282555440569,17.95,4.61548125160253));
#1999=VERTEX_POINT('',#1998);
#2000=EDGE_CURVE('E400',#1883,#1999,#1997,.F.);
#2001=ORIENTED_EDGE('',*,*,#2000,.T.);
#2002=CARTESIAN_POINT('',(1.1010249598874,17.6618712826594,-6.40703117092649));
#2003=CARTESIAN_POINT('',(1.03279892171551,17.5879658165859,-6.28886020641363));
#2004=CARTESIAN_POINT('',(0.964512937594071,17.5142805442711,-6.17058541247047));
#2005=CARTESIAN_POINT('',(0.827789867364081,17.3674663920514,-5.93377410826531));
#2006=CARTESIAN_POINT('',(0.759352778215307,17.2943375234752,-5.81523759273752));
#2007=CARTESIAN_POINT('',(0.622244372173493,17.1486971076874,-5.57775886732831));
#2008=CARTESIAN_POINT('',(0.553572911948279,17.0761860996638,-5.4588164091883));
#2009=CARTESIAN_POINT('',(0.416010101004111,16.932005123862,-5.220550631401));
#2010=CARTESIAN_POINT('',(0.34711875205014,16.8603351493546,-5.10122731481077));
#2011=CARTESIAN_POINT('',(0.206719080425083,16.7156352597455,-4.85804795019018));
#2012=CARTESIAN_POINT('',(0.135201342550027,16.6426418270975,-4.73417559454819));
#2013=CARTESIAN_POINT('',(-0.00820106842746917,16.4981120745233,-4.48579533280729));
#2014=CARTESIAN_POINT('',(-0.0800857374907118,16.4265757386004,-4.36128743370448));
#2015=CARTESIAN_POINT('',(-0.224302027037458,16.2854408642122,-4.11149749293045));
#2016=CARTESIAN_POINT('',(-0.29663349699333,16.2158417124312,-3.98621571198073));
#2017=CARTESIAN_POINT('',(-0.441900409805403,16.0792198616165,-3.73460603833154));
#2018=CARTESIAN_POINT('',(-0.514835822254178,16.0121970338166,-3.60827819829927));
#2019=CARTESIAN_POINT('',(-0.664950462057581,15.8786143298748,-3.34827201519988));
#2020=CARTESIAN_POINT('',(-0.742167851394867,15.812224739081,-3.21452757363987));
#2021=CARTESIAN_POINT('',(-0.897772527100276,15.6849682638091,-2.94501236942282));
#2022=CARTESIAN_POINT('',(-0.976160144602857,15.6241029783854,-2.80924103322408));
#2023=CARTESIAN_POINT('',(-1.13369367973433,15.5109845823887,-2.53638494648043));
#2024=CARTESIAN_POINT('',(-1.2128262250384,15.458658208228,-2.39932335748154));
#2025=CARTESIAN_POINT('',(-1.37280299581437,15.3656500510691,-2.12223546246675));
#2026=CARTESIAN_POINT('',(-1.45364627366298,15.3249619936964,-1.98221079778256));
#2027=CARTESIAN_POINT('',(-1.59674379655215,15.2680003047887,-1.73435861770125));
#2028=CARTESIAN_POINT('',(-1.65863734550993,15.2481746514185,-1.62715584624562));
#2029=CARTESIAN_POINT('',(-1.78306000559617,15.2196836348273,-1.41164947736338));
#2030=CARTESIAN_POINT('',(-1.8455888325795,15.2110134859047,-1.30334637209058));
#2031=CARTESIAN_POINT('',(-1.97067203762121,15.2058358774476,-1.08669590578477));
#2032=CARTESIAN_POINT('',(-2.03322619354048,15.2093078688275,-0.978348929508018));
#2033=CARTESIAN_POINT('',(-2.15788909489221,15.2279503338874,-0.762426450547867));
#2034=CARTESIAN_POINT('',(-2.21999774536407,15.2431232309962,-0.654851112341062));
#2035=CARTESIAN_POINT('',(-2.40347402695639,15.303258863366,-0.337060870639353));
#2036=CARTESIAN_POINT('',(-2.52363364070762,15.3628427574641,-0.128938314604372));
#2037=CARTESIAN_POINT('',(-2.70101445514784,15.4702860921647,0.178294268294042));
#2038=CARTESIAN_POINT('',(-2.75975354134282,15.5091859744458,0.280033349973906));
#2039=CARTESIAN_POINT('',(-2.8764267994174,15.591577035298,0.48211736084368));
#2040=CARTESIAN_POINT('',(-2.93436110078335,15.6350674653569,0.582462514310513));
#2041=CARTESIAN_POINT('',(-3.05047532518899,15.7262415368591,0.783578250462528));
#2042=CARTESIAN_POINT('',(-3.10864392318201,15.7739818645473,0.884329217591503));
#2043=CARTESIAN_POINT('',(-3.22440579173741,15.8721753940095,1.08483465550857));
#2044=CARTESIAN_POINT('',(-3.28199905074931,15.9226286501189,1.18458910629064));
#2045=CARTESIAN_POINT('',(-3.39663195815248,16.025542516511,1.38313912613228));
#2046=CARTESIAN_POINT('',(-3.45367229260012,16.0780000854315,1.48193588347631));
#2047=CARTESIAN_POINT('',(-3.56737126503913,16.1845333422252,1.67886828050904));
#2048=CARTESIAN_POINT('',(-3.62402991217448,16.2386089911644,1.77700393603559));
#2049=CARTESIAN_POINT('',(-3.74476543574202,16.3555227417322,1.986123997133));
#2050=CARTESIAN_POINT('',(-3.80879699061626,16.4185477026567,2.09702990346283));
#2051=CARTESIAN_POINT('',(-3.93653938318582,16.5458860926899,2.31828621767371));
#2052=CARTESIAN_POINT('',(-4.00025021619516,16.6101995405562,2.42863661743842));
#2053=CARTESIAN_POINT('',(-4.19100385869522,16.8046604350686,2.75903161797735));
#2054=CARTESIAN_POINT('',(-4.31766064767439,16.9363214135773,2.97840761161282));
#2055=CARTESIAN_POINT('',(-4.57030689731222,17.2022847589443,3.41600375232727));
#2056=CARTESIAN_POINT('',(-4.69629622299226,17.3365876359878,3.63422366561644));
#2057=CARTESIAN_POINT('',(-4.94778962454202,17.6070020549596,4.06982301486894));
#2058=CARTESIAN_POINT('',(-5.07329369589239,17.7431136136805,4.28720244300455));
#2059=CARTESIAN_POINT('',(-5.32406686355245,18.0167530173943,4.72155431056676));
#2060=CARTESIAN_POINT('',(-5.44933563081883,18.1542820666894,4.93852618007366));
#2061=CARTESIAN_POINT('',(-5.69961043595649,18.4302967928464,5.37201485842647));
#2062=CARTESIAN_POINT('',(-5.82461647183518,18.5687824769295,5.58853166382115));
#2063=CARTESIAN_POINT('',(-6.19930564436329,18.9852755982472,6.23751234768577));
#2064=CARTESIAN_POINT('',(-6.44869117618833,19.2643534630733,6.66946075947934));
#2065=CARTESIAN_POINT('',(-6.94463610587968,19.8216119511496,7.52846257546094));
#2066=CARTESIAN_POINT('',(-7.19120005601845,20.0997764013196,7.95552386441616));
#2067=CARTESIAN_POINT('',(-7.68401611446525,20.657243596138,8.80910631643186));
#2068=CARTESIAN_POINT('',(-7.9302682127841,20.936546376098,9.23562746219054));
#2069=CARTESIAN_POINT('',(-8.42246505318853,21.4958360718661,10.0881373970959));
#2070=CARTESIAN_POINT('',(-8.66840987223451,21.7758227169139,10.5141263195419));
#2071=CARTESIAN_POINT('',(-9.16013707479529,22.336357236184,11.3658228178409));
#2072=CARTESIAN_POINT('',(-9.40591945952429,22.6169051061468,11.7915303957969));
#2073=CARTESIAN_POINT('',(-9.79618538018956,23.0628156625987,12.4674907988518));
#2074=CARTESIAN_POINT('',(-9.94070814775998,23.2280410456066,12.7178115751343));
#2075=CARTESIAN_POINT('',(-10.2297271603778,23.5586264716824,13.2184071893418));
#2076=CARTESIAN_POINT('',(-10.3742234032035,23.7239865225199,13.4686820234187));
#2077=CARTESIAN_POINT('',(-10.6637244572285,24.0554300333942,13.9701125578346));
#2078=CARTESIAN_POINT('',(-10.8087291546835,24.2215138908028,14.2212680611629));
#2079=CARTESIAN_POINT('',(-11.0987027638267,24.5537641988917,14.7235170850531));
#2080=CARTESIAN_POINT('',(-11.2436716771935,24.7199306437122,14.9746106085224));
#2081=CARTESIAN_POINT('',(-11.3886292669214,24.8861365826,15.2256845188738));
#2082=B_SPLINE_CURVE_WITH_KNOTS('',3,(#2002,#2003,#2004,#2005,#2006,#2007,#2008,#2009,#2010,
#2011,#2012,#2013,#2014,#2015,#2016,#2017,#2018,#2019,#2020,#2021,#2022,#2023,#2024,#2025,#2026,
#2027,#2028,#2029,#2030,#2031,#2032,#2033,#2034,#2035,#2036,#2037,#2038,#2039,#2040,#2041,#2042,
#2043,#2044,#2045,#2046,#2047,#2048,#2049,#2050,#2051,#2052,#2053,#2054,#2055,#2056,#2057,#2058,
#2059,#2060,#2061,#2062,#2063,#2064,#2065,#2066,#2067,#2068,#2069,#2070,#2071,#2072,#2073,#2074,
#2075,#2076,#2077,#2078,#2079,#2080,#2081),.UNSPECIFIED.,.F.,.F.,(4,2,2,2,2,2,2,2,2,2,2,2,2,2,2,
2,2,2,2,2,2,2,2,2,2,2,2,2,2,2,2,2,2,2,2,2,2,2,2,4),(0.,0.465544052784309,0.931097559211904,
1.39702257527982,1.86294386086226,2.34468921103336,2.82642926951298,3.30801503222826,
3.78957669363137,4.29380542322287,4.79817964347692,5.29796855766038,5.79748751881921,
6.17315850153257,6.54866826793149,6.92354283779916,7.29849507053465,8.03868283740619,
8.40992633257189,8.78110938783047,9.15832827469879,9.53555471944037,9.91222987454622,
10.2888959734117,10.7170812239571,11.1452727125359,12.0017035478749,12.8583014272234,
13.7149072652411,14.5723133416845,15.4297258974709,17.144336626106,18.842850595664,
20.5414176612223,22.2393958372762,23.9373611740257,24.9361708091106,25.9350428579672,
26.9376413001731,27.9401766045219),.UNSPECIFIED.);
#2083=EDGE_CURVE('E855',#1999,#77,#2082,.T.);
#2084=ORIENTED_EDGE('',*,*,#2083,.T.);
#2085=ORIENTED_EDGE('',*,*,#78,.F.);
#2086=EDGE_LOOP('',(#1992,#1993,#2001,#2084,#2085));
#2087=FACE_BOUND('',#2086,.T.);
#2088=ADVANCED_FACE('F845',(#2087),#1986,.F.);
#2089=CARTESIAN_POINT('',(0.,17.95,0.));
#2090=DIRECTION('',(0.,1.,0.));
#2091=DIRECTION('',(0.,0.,1.));
#2092=AXIS2_PLACEMENT_3D('',#2089,#2090,#2091);
#2093=CONICAL_SURFACE('',#2092,7.,1.0471975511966);
#2094=ORIENTED_EDGE('',*,*,#1970,.F.);
#2095=ORIENTED_EDGE('',*,*,#50,.F.);
#2096=ORIENTED_EDGE('',*,*,#1759,.F.);
#2097=CARTESIAN_POINT('',(0.,17.95,0.));
#2098=DIRECTION('',(0.,-1.,0.));
#2099=DIRECTION('',(0.,0.,-1.));
#2100=AXIS2_PLACEMENT_3D('',#2097,#2098,#2099);
#2101=CIRCLE('',#2100,7.);
#2102=EDGE_CURVE('E702',#1969,#1687,#2101,.F.);
#2103=ORIENTED_EDGE('',*,*,#2102,.F.);
#2104=EDGE_LOOP('',(#2094,#2095,#2096,#2103));
#2105=FACE_BOUND('',#2104,.T.);
#2106=ADVANCED_FACE('F885',(#2105),#2093,.F.);
#2107=ORIENTED_EDGE('',*,*,#2083,.F.);
#2108=EDGE_CURVE('E643',#981,#1999,#2101,.F.);
#2109=ORIENTED_EDGE('',*,*,#2108,.F.);
#2110=ORIENTED_EDGE('',*,*,#982,.F.);
#2111=ORIENTED_EDGE('',*,*,#82,.F.);
#2112=EDGE_LOOP('',(#2107,#2109,#2110,#2111));
#2113=FACE_BOUND('',#2112,.T.);
#2114=ADVANCED_FACE('F854',(#2113),#2093,.F.);
#2115=ORIENTED_EDGE('',*,*,#1642,.F.);
#2116=ORIENTED_EDGE('',*,*,#114,.F.);
#2117=ORIENTED_EDGE('',*,*,#1422,.F.);
#2118=EDGE_CURVE('E719',#1641,#1352,#2101,.F.);
#2119=ORIENTED_EDGE('',*,*,#2118,.F.);
#2120=EDGE_LOOP('',(#2115,#2116,#2117,#2119));
#2121=FACE_BOUND('',#2120,.T.);
#2122=ADVANCED_FACE('F1028',(#2121),#2093,.F.);
#2123=ORIENTED_EDGE('',*,*,#1505,.F.);
#2124=ORIENTED_EDGE('',*,*,#146,.F.);
#2125=ORIENTED_EDGE('',*,*,#1183,.F.);
#2126=EDGE_CURVE('E715',#1504,#1121,#2101,.F.);
#2127=ORIENTED_EDGE('',*,*,#2126,.F.);
#2128=EDGE_LOOP('',(#2123,#2124,#2125,#2127));
#2129=FACE_BOUND('',#2128,.T.);
#2130=ADVANCED_FACE('F962',(#2129),#2093,.F.);
#2131=ORIENTED_EDGE('',*,*,#1288,.F.);
#2132=ORIENTED_EDGE('',*,*,#178,.F.);
#2133=ORIENTED_EDGE('',*,*,#1089,.F.);
#2134=EDGE_CURVE('E705',#1287,#1011,#2101,.F.);
#2135=ORIENTED_EDGE('',*,*,#2134,.F.);
#2136=EDGE_LOOP('',(#2131,#2132,#2133,#2135));
#2137=FACE_BOUND('',#2136,.T.);
#2138=ADVANCED_FACE('F1090',(#2137),#2093,.F.);
#2139=CARTESIAN_POINT('',(12.,0.,-6.92820323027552));
#2140=DIRECTION('',(0.,-1.,0.));
#2141=DIRECTION('',(0.,0.,-1.));
#2142=AXIS2_PLACEMENT_3D('',#2139,#2140,#2141);
#2143=PLANE('',#2142);
#2144=CARTESIAN_POINT('',(0.,0.,0.));
#2145=DIRECTION('',(0.,-1.,0.));
#2146=DIRECTION('',(0.,0.,-1.));
#2147=AXIS2_PLACEMENT_3D('',#2144,#2145,#2146);
#2148=CIRCLE('',#2147,8.81865334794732);
#2149=CARTESIAN_POINT('',(0.,0.,-8.81865334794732));
#2150=VERTEX_POINT('',#2149);
#2151=EDGE_CURVE('E645',#2150,#2150,#2148,.F.);
#2152=ORIENTED_EDGE('',*,*,#2151,.T.);
#2153=EDGE_LOOP('',(#2152));
#2154=FACE_BOUND('',#2153,.T.);
#2155=CARTESIAN_POINT('',(0.,0.,0.));
#2156=DIRECTION('',(0.,-1.,0.));
#2157=DIRECTION('',(0.,0.,-1.));
#2158=AXIS2_PLACEMENT_3D('',#2155,#2156,#2157);
#2159=CIRCLE('',#2158,11.5);
#2160=CARTESIAN_POINT('',(0.,0.,-11.5));
#2161=VERTEX_POINT('',#2160);
#2162=EDGE_CURVE('E435',#2161,#2161,#2159,.T.);
#2163=ORIENTED_EDGE('',*,*,#2162,.T.);
#2164=EDGE_LOOP('',(#2163));
#2165=FACE_BOUND('',#2164,.T.);
#2166=ADVANCED_FACE('F465',(#2154,#2165),#2143,.T.);
#2167=CARTESIAN_POINT('',(0.,1.36047190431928,0.));
#2168=DIRECTION('',(0.,1.,0.));
#2169=DIRECTION('',(0.,0.,-1.));
#2170=AXIS2_PLACEMENT_3D('',#2167,#2168,#2169);
#2171=CONICAL_SURFACE('',#2170,13.856406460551,1.0471975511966);
#2172=ORIENTED_EDGE('',*,*,#2162,.F.);
#2173=EDGE_LOOP('',(#2172));
#2174=FACE_BOUND('',#2173,.T.);
#2175=ORIENTED_EDGE('',*,*,#300,.T.);
#2176=ORIENTED_EDGE('',*,*,#849,.T.);
#2177=ORIENTED_EDGE('',*,*,#698,.T.);
#2178=ORIENTED_EDGE('',*,*,#617,.T.);
#2179=ORIENTED_EDGE('',*,*,#536,.T.);
#2180=ORIENTED_EDGE('',*,*,#381,.T.);
#2181=EDGE_LOOP('',(#2175,#2176,#2177,#2178,#2179,#2180));
#2182=FACE_BOUND('',#2181,.T.);
#2183=ADVANCED_FACE('F457',(#2174,#2182),#2171,.T.);
#2184=CARTESIAN_POINT('',(0.,19.,0.));
#2185=DIRECTION('',(0.,-1.,0.));
#2186=DIRECTION('',(0.,0.,-1.));
#2187=AXIS2_PLACEMENT_3D('',#2184,#2185,#2186);
#2188=CYLINDRICAL_SURFACE('',#2187,7.);
#2189=ORIENTED_EDGE('',*,*,#1976,.F.);
#2190=ORIENTED_EDGE('',*,*,#2102,.T.);
#2191=ORIENTED_EDGE('',*,*,#1688,.F.);
#2192=ORIENTED_EDGE('',*,*,#1862,.F.);
#2193=ORIENTED_EDGE('',*,*,#1848,.F.);
#2194=EDGE_CURVE('E709',#1839,#1559,#2101,.F.);
#2195=ORIENTED_EDGE('',*,*,#2194,.T.);
#2196=ORIENTED_EDGE('',*,*,#1560,.F.);
#2197=ORIENTED_EDGE('',*,*,#1664,.F.);
#2198=ORIENTED_EDGE('',*,*,#1650,.F.);
#2199=ORIENTED_EDGE('',*,*,#2118,.T.);
#2200=ORIENTED_EDGE('',*,*,#1353,.F.);
#2201=ORIENTED_EDGE('',*,*,#1527,.F.);
#2202=ORIENTED_EDGE('',*,*,#1513,.F.);
#2203=ORIENTED_EDGE('',*,*,#2126,.T.);
#2204=ORIENTED_EDGE('',*,*,#1122,.F.);
#2205=ORIENTED_EDGE('',*,*,#1320,.F.);
#2206=ORIENTED_EDGE('',*,*,#1296,.F.);
#2207=ORIENTED_EDGE('',*,*,#2134,.T.);
#2208=ORIENTED_EDGE('',*,*,#1012,.F.);
#2209=ORIENTED_EDGE('',*,*,#886,.F.);
#2210=ORIENTED_EDGE('',*,*,#988,.F.);
#2211=ORIENTED_EDGE('',*,*,#2108,.T.);
#2212=ORIENTED_EDGE('',*,*,#2000,.F.);
#2213=ORIENTED_EDGE('',*,*,#1884,.F.);
#2214=EDGE_LOOP('',(#2189,#2190,#2191,#2192,#2193,#2195,#2196,#2197,#2198,#2199,#2200,#2201,
#2202,#2203,#2204,#2205,#2206,#2207,#2208,#2209,#2210,#2211,#2212,#2213));
#2215=FACE_BOUND('',#2214,.T.);
#2216=CARTESIAN_POINT('',(0.,1.05,0.));
#2217=DIRECTION('',(0.,-1.,0.));
#2218=DIRECTION('',(0.,0.,-1.));
#2219=AXIS2_PLACEMENT_3D('',#2216,#2217,#2218);
#2220=CIRCLE('',#2219,7.);
#2221=CARTESIAN_POINT('',(0.,1.05,-7.));
#2222=VERTEX_POINT('',#2221);
#2223=EDGE_CURVE('E711',#2222,#2222,#2220,.T.);
#2224=ORIENTED_EDGE('',*,*,#2223,.T.);
#2225=EDGE_LOOP('',(#2224));
#2226=FACE_BOUND('',#2225,.T.);
#2227=ADVANCED_FACE('F462',(#2215,#2226),#2188,.F.);
#2228=ORIENTED_EDGE('',*,*,#1840,.F.);
#2229=ORIENTED_EDGE('',*,*,#210,.F.);
#2230=ORIENTED_EDGE('',*,*,#1591,.F.);
#2231=ORIENTED_EDGE('',*,*,#2194,.F.);
#2232=EDGE_LOOP('',(#2228,#2229,#2230,#2231));
#2233=FACE_BOUND('',#2232,.T.);
#2234=ADVANCED_FACE('F624',(#2233),#2093,.F.);
#2235=CARTESIAN_POINT('',(0.,0.,0.));
#2236=DIRECTION('',(0.,-1.,0.));
#2237=DIRECTION('',(0.,0.,-1.));
#2238=AXIS2_PLACEMENT_3D('',#2235,#2236,#2237);
#2239=CONICAL_SURFACE('',#2238,8.81865334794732,1.0471975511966);
#2240=ORIENTED_EDGE('',*,*,#2223,.F.);
#2241=EDGE_LOOP('',(#2240));
#2242=FACE_BOUND('',#2241,.T.);
#2243=ORIENTED_EDGE('',*,*,#2151,.F.);
#2244=EDGE_LOOP('',(#2243));
#2245=FACE_BOUND('',#2244,.T.);
#2246=ADVANCED_FACE('F44',(#2242,#2245),#2239,.F.);
#2247=CARTESIAN_POINT('',(0.,0.,0.));
#2248=DIRECTION('',(0.,-1.,0.));
#2249=DIRECTION('',(0.,0.,-1.));
#2250=AXIS2_PLACEMENT_3D('',#2247,#2248,#2249);
#2251=CONICAL_SURFACE('',#2250,33.5166604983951,1.04719755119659);
#2252=ORIENTED_EDGE('',*,*,#1524,.T.);
#2253=EDGE_CURVE('E312',#1336,#1607,#864,.T.);
#2254=ORIENTED_EDGE('',*,*,#2253,.T.);
#2255=ORIENTED_EDGE('',*,*,#1661,.T.);
#2256=EDGE_CURVE('E926',#1543,#1775,#864,.T.);
#2257=ORIENTED_EDGE('',*,*,#2256,.T.);
#2258=ORIENTED_EDGE('',*,*,#1859,.T.);
#2259=EDGE_CURVE('E1110',#1675,#1869,#864,.T.);
#2260=ORIENTED_EDGE('',*,*,#2259,.T.);
#2261=ORIENTED_EDGE('',*,*,#1872,.T.);
#2262=EDGE_CURVE('E836',#1871,#866,#864,.T.);
#2263=ORIENTED_EDGE('',*,*,#2262,.T.);
#2264=ORIENTED_EDGE('',*,*,#869,.T.);
#2265=EDGE_CURVE('E1075',#868,#1199,#864,.T.);
#2266=ORIENTED_EDGE('',*,*,#2265,.T.);
#2267=ORIENTED_EDGE('',*,*,#1312,.T.);
#2268=EDGE_CURVE('E279',#1105,#1438,#864,.T.);
#2269=ORIENTED_EDGE('',*,*,#2268,.T.);
#2270=EDGE_LOOP('',(#2252,#2254,#2255,#2257,#2258,#2260,#2261,#2263,#2264,#2266,#2267,#2269));
#2271=FACE_BOUND('',#2270,.T.);
#2272=ORIENTED_EDGE('',*,*,#259,.T.);
#2273=ORIENTED_EDGE('',*,*,#347,.T.);
#2274=ORIENTED_EDGE('',*,*,#478,.T.);
#2275=ORIENTED_EDGE('',*,*,#583,.T.);
#2276=ORIENTED_EDGE('',*,*,#664,.T.);
#2277=ORIENTED_EDGE('',*,*,#793,.T.);
#2278=EDGE_LOOP('',(#2272,#2273,#2274,#2275,#2276,#2277));
#2279=FACE_BOUND('',#2278,.T.);
#2280=ADVANCED_FACE('F295',(#2271,#2279),#2251,.T.);
#2281=CARTESIAN_POINT('',(0.,0.,0.));
#2282=DIRECTION('',(0.,-1.,0.));
#2283=DIRECTION('',(0.,0.,-1.));
#2284=AXIS2_PLACEMENT_3D('',#2281,#2282,#2283);
#2285=CYLINDRICAL_SURFACE('',#2284,11.);
#2286=ORIENTED_EDGE('',*,*,#1003,.T.);
#2287=ORIENTED_EDGE('',*,*,#166,.T.);
#2288=ORIENTED_EDGE('',*,*,#1200,.T.);
#2289=ORIENTED_EDGE('',*,*,#2265,.F.);
#2290=EDGE_LOOP('',(#2286,#2287,#2288,#2289));
#2291=FACE_BOUND('',#2290,.T.);
#2292=ADVANCED_FACE('F531',(#2291),#2285,.T.);
#2293=ORIENTED_EDGE('',*,*,#1106,.T.);
#2294=ORIENTED_EDGE('',*,*,#134,.T.);
#2295=ORIENTED_EDGE('',*,*,#1439,.T.);
#2296=ORIENTED_EDGE('',*,*,#2268,.F.);
#2297=EDGE_LOOP('',(#2293,#2294,#2295,#2296));
#2298=FACE_BOUND('',#2297,.T.);
#2299=ADVANCED_FACE('F278',(#2298),#2285,.T.);
#2300=ORIENTED_EDGE('',*,*,#1337,.T.);
#2301=ORIENTED_EDGE('',*,*,#102,.T.);
#2302=ORIENTED_EDGE('',*,*,#1608,.T.);
#2303=ORIENTED_EDGE('',*,*,#2253,.F.);
#2304=EDGE_LOOP('',(#2300,#2301,#2302,#2303));
#2305=FACE_BOUND('',#2304,.T.);
#2306=ADVANCED_FACE('F1031',(#2305),#2285,.T.);
#2307=ORIENTED_EDGE('',*,*,#1544,.T.);
#2308=ORIENTED_EDGE('',*,*,#198,.T.);
#2309=ORIENTED_EDGE('',*,*,#1776,.T.);
#2310=ORIENTED_EDGE('',*,*,#2256,.F.);
#2311=EDGE_LOOP('',(#2307,#2308,#2309,#2310));
#2312=FACE_BOUND('',#2311,.T.);
#2313=ADVANCED_FACE('F1099',(#2312),#2285,.T.);
#2314=ORIENTED_EDGE('',*,*,#1676,.T.);
#2315=ORIENTED_EDGE('',*,*,#33,.T.);
#2316=ORIENTED_EDGE('',*,*,#1904,.T.);
#2317=ORIENTED_EDGE('',*,*,#2259,.F.);
#2318=EDGE_LOOP('',(#2314,#2315,#2316,#2317));
#2319=FACE_BOUND('',#2318,.T.);
#2320=ADVANCED_FACE('F1096',(#2319),#2285,.T.);
#2321=ORIENTED_EDGE('',*,*,#906,.T.);
#2322=ORIENTED_EDGE('',*,*,#2262,.F.);
#2323=ORIENTED_EDGE('',*,*,#1991,.T.);
#2324=ORIENTED_EDGE('',*,*,#70,.T.);
#2325=EDGE_LOOP('',(#2321,#2322,#2323,#2324));
#2326=FACE_BOUND('',#2325,.T.);
#2327=ADVANCED_FACE('F840',(#2326),#2285,.T.);
#2328=CLOSED_SHELL('',(#60,#92,#124,#156,#188,#220,#310,#391,#546,#627,#708,#854,#896,#993,
#1094,#1188,#1306,#1325,#1427,#1523,#1532,#1596,#1660,#1669,#1764,#1858,#1867,#1894,#1981,#2088,
#2106,#2114,#2122,#2130,#2138,#2166,#2183,#2227,#2234,#2246,#2280,#2292,#2299,#2306,#2313,#2320,#2327));
#2329=MANIFOLD_SOLID_BREP('B2',#2328);
#2330=ADVANCED_BREP_SHAPE_REPRESENTATION('',(#18,#2329),#14);
#2331=SHAPE_DEFINITION_REPRESENTATION(#9,#2330);
ENDSEC;
END-ISO-10303-21;
